VERSION 5.8 ;
BUSBITCHARS "[]" ;
DIVIDERCHAR "/" ;
UNITS
    DATABASE MICRONS 1000 ;
END UNITS

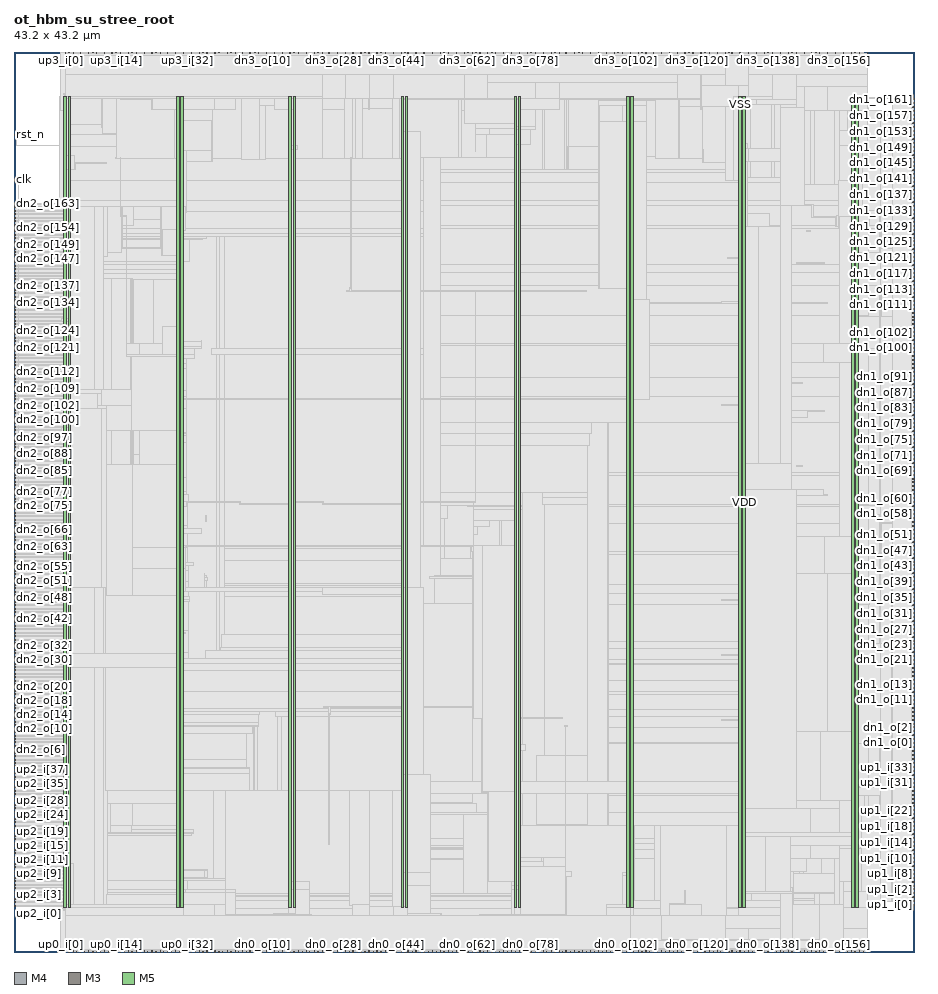
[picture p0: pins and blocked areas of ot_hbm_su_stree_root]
MACRO ot_hbm_su_stree_root
  FOREIGN ot_hbm_su_stree_root 0 0 ;
  CLASS BLOCK ;
  SIZE 43.2 BY 43.2 ;
  PIN clk
    DIRECTION INPUT ;
    USE SIGNAL ;
    PORT
      LAYER M4 ;
        RECT  0 37.056 0.084 37.08 ;
    END
    PORT
      LAYER M4 ;
        RECT  0.06 37.056 0.227 37.08 ;
    END
  END clk
  PIN dn0_o[0]
    DIRECTION OUTPUT ;
    USE SIGNAL ;
    PORT
      LAYER M3 ;
        RECT  10.008 0 10.026 0.038 ;
    END
  END dn0_o[0]
  PIN dn0_o[100]
    DIRECTION OUTPUT ;
    USE SIGNAL ;
    PORT
      LAYER M3 ;
        RECT  28.98 0 28.998 0.038 ;
    END
  END dn0_o[100]
  PIN dn0_o[101]
    DIRECTION OUTPUT ;
    USE SIGNAL ;
    PORT
      LAYER M5 ;
        RECT  29.184 0 29.208 0.084 ;
    END
  END dn0_o[101]
  PIN dn0_o[102]
    DIRECTION OUTPUT ;
    USE SIGNAL ;
    PORT
      LAYER M3 ;
        RECT  29.376 0 29.394 0.038 ;
    END
  END dn0_o[102]
  PIN dn0_o[103]
    DIRECTION OUTPUT ;
    USE SIGNAL ;
    PORT
      LAYER M5 ;
        RECT  29.568 0 29.592 0.084 ;
    END
  END dn0_o[103]
  PIN dn0_o[104]
    DIRECTION OUTPUT ;
    USE SIGNAL ;
    PORT
      LAYER M3 ;
        RECT  29.736 0 29.754 0.038 ;
    END
  END dn0_o[104]
  PIN dn0_o[105]
    DIRECTION OUTPUT ;
    USE SIGNAL ;
    PORT
      LAYER M5 ;
        RECT  29.952 0 29.976 0.084 ;
    END
  END dn0_o[105]
  PIN dn0_o[106]
    DIRECTION OUTPUT ;
    USE SIGNAL ;
    PORT
      LAYER M3 ;
        RECT  30.132 0 30.15 0.038 ;
    END
  END dn0_o[106]
  PIN dn0_o[107]
    DIRECTION OUTPUT ;
    USE SIGNAL ;
    PORT
      LAYER M5 ;
        RECT  30.336 0 30.36 0.084 ;
    END
  END dn0_o[107]
  PIN dn0_o[108]
    DIRECTION OUTPUT ;
    USE SIGNAL ;
    PORT
      LAYER M3 ;
        RECT  30.492 0 30.51 0.038 ;
    END
  END dn0_o[108]
  PIN dn0_o[109]
    DIRECTION OUTPUT ;
    USE SIGNAL ;
    PORT
      LAYER M5 ;
        RECT  30.672 0 30.696 0.084 ;
    END
  END dn0_o[109]
  PIN dn0_o[10]
    DIRECTION OUTPUT ;
    USE SIGNAL ;
    PORT
      LAYER M3 ;
        RECT  11.916 0 11.934 0.038 ;
    END
  END dn0_o[10]
  PIN dn0_o[110]
    DIRECTION OUTPUT ;
    USE SIGNAL ;
    PORT
      LAYER M3 ;
        RECT  30.888 0 30.906 0.038 ;
    END
  END dn0_o[110]
  PIN dn0_o[111]
    DIRECTION OUTPUT ;
    USE SIGNAL ;
    PORT
      LAYER M5 ;
        RECT  31.056 0 31.08 0.084 ;
    END
  END dn0_o[111]
  PIN dn0_o[112]
    DIRECTION OUTPUT ;
    USE SIGNAL ;
    PORT
      LAYER M3 ;
        RECT  31.248 0 31.266 0.038 ;
    END
  END dn0_o[112]
  PIN dn0_o[113]
    DIRECTION OUTPUT ;
    USE SIGNAL ;
    PORT
      LAYER M5 ;
        RECT  31.44 0 31.464 0.084 ;
    END
  END dn0_o[113]
  PIN dn0_o[114]
    DIRECTION OUTPUT ;
    USE SIGNAL ;
    PORT
      LAYER M3 ;
        RECT  31.644 0 31.662 0.038 ;
    END
  END dn0_o[114]
  PIN dn0_o[115]
    DIRECTION OUTPUT ;
    USE SIGNAL ;
    PORT
      LAYER M5 ;
        RECT  31.824 0 31.848 0.084 ;
    END
  END dn0_o[115]
  PIN dn0_o[116]
    DIRECTION OUTPUT ;
    USE SIGNAL ;
    PORT
      LAYER M3 ;
        RECT  32.04 0 32.058 0.038 ;
    END
  END dn0_o[116]
  PIN dn0_o[117]
    DIRECTION OUTPUT ;
    USE SIGNAL ;
    PORT
      LAYER M5 ;
        RECT  32.208 0 32.232 0.084 ;
    END
  END dn0_o[117]
  PIN dn0_o[118]
    DIRECTION OUTPUT ;
    USE SIGNAL ;
    PORT
      LAYER M3 ;
        RECT  32.4 0 32.418 0.038 ;
    END
  END dn0_o[118]
  PIN dn0_o[119]
    DIRECTION OUTPUT ;
    USE SIGNAL ;
    PORT
      LAYER M5 ;
        RECT  32.592 0 32.616 0.084 ;
    END
  END dn0_o[119]
  PIN dn0_o[11]
    DIRECTION OUTPUT ;
    USE SIGNAL ;
    PORT
      LAYER M5 ;
        RECT  12.096 0 12.12 0.084 ;
    END
  END dn0_o[11]
  PIN dn0_o[120]
    DIRECTION OUTPUT ;
    USE SIGNAL ;
    PORT
      LAYER M3 ;
        RECT  32.796 0 32.814 0.038 ;
    END
  END dn0_o[120]
  PIN dn0_o[121]
    DIRECTION OUTPUT ;
    USE SIGNAL ;
    PORT
      LAYER M5 ;
        RECT  32.976 0 33 0.084 ;
    END
  END dn0_o[121]
  PIN dn0_o[122]
    DIRECTION OUTPUT ;
    USE SIGNAL ;
    PORT
      LAYER M3 ;
        RECT  33.156 0 33.174 0.038 ;
    END
  END dn0_o[122]
  PIN dn0_o[123]
    DIRECTION OUTPUT ;
    USE SIGNAL ;
    PORT
      LAYER M5 ;
        RECT  33.36 0 33.384 0.084 ;
    END
  END dn0_o[123]
  PIN dn0_o[124]
    DIRECTION OUTPUT ;
    USE SIGNAL ;
    PORT
      LAYER M3 ;
        RECT  33.552 0 33.57 0.038 ;
    END
  END dn0_o[124]
  PIN dn0_o[125]
    DIRECTION OUTPUT ;
    USE SIGNAL ;
    PORT
      LAYER M5 ;
        RECT  33.744 0 33.768 0.084 ;
    END
  END dn0_o[125]
  PIN dn0_o[126]
    DIRECTION OUTPUT ;
    USE SIGNAL ;
    PORT
      LAYER M3 ;
        RECT  33.912 0 33.93 0.038 ;
    END
  END dn0_o[126]
  PIN dn0_o[127]
    DIRECTION OUTPUT ;
    USE SIGNAL ;
    PORT
      LAYER M5 ;
        RECT  34.128 0 34.152 0.084 ;
    END
  END dn0_o[127]
  PIN dn0_o[128]
    DIRECTION OUTPUT ;
    USE SIGNAL ;
    PORT
      LAYER M3 ;
        RECT  34.308 0 34.326 0.038 ;
    END
  END dn0_o[128]
  PIN dn0_o[129]
    DIRECTION OUTPUT ;
    USE SIGNAL ;
    PORT
      LAYER M5 ;
        RECT  34.464 0 34.488 0.084 ;
    END
  END dn0_o[129]
  PIN dn0_o[12]
    DIRECTION OUTPUT ;
    USE SIGNAL ;
    PORT
      LAYER M3 ;
        RECT  12.312 0 12.33 0.038 ;
    END
  END dn0_o[12]
  PIN dn0_o[130]
    DIRECTION OUTPUT ;
    USE SIGNAL ;
    PORT
      LAYER M3 ;
        RECT  34.668 0 34.686 0.038 ;
    END
  END dn0_o[130]
  PIN dn0_o[131]
    DIRECTION OUTPUT ;
    USE SIGNAL ;
    PORT
      LAYER M5 ;
        RECT  34.848 0 34.872 0.084 ;
    END
  END dn0_o[131]
  PIN dn0_o[132]
    DIRECTION OUTPUT ;
    USE SIGNAL ;
    PORT
      LAYER M3 ;
        RECT  35.064 0 35.082 0.038 ;
    END
  END dn0_o[132]
  PIN dn0_o[133]
    DIRECTION OUTPUT ;
    USE SIGNAL ;
    PORT
      LAYER M5 ;
        RECT  35.232 0 35.256 0.084 ;
    END
  END dn0_o[133]
  PIN dn0_o[134]
    DIRECTION OUTPUT ;
    USE SIGNAL ;
    PORT
      LAYER M3 ;
        RECT  35.424 0 35.442 0.038 ;
    END
  END dn0_o[134]
  PIN dn0_o[135]
    DIRECTION OUTPUT ;
    USE SIGNAL ;
    PORT
      LAYER M5 ;
        RECT  35.616 0 35.64 0.084 ;
    END
  END dn0_o[135]
  PIN dn0_o[136]
    DIRECTION OUTPUT ;
    USE SIGNAL ;
    PORT
      LAYER M3 ;
        RECT  35.82 0 35.838 0.038 ;
    END
  END dn0_o[136]
  PIN dn0_o[137]
    DIRECTION OUTPUT ;
    USE SIGNAL ;
    PORT
      LAYER M5 ;
        RECT  36 0 36.024 0.084 ;
    END
  END dn0_o[137]
  PIN dn0_o[138]
    DIRECTION OUTPUT ;
    USE SIGNAL ;
    PORT
      LAYER M3 ;
        RECT  36.18 0 36.198 0.038 ;
    END
  END dn0_o[138]
  PIN dn0_o[139]
    DIRECTION OUTPUT ;
    USE SIGNAL ;
    PORT
      LAYER M5 ;
        RECT  36.384 0 36.408 0.084 ;
    END
  END dn0_o[139]
  PIN dn0_o[13]
    DIRECTION OUTPUT ;
    USE SIGNAL ;
    PORT
      LAYER M5 ;
        RECT  12.48 0 12.504 0.084 ;
    END
  END dn0_o[13]
  PIN dn0_o[140]
    DIRECTION OUTPUT ;
    USE SIGNAL ;
    PORT
      LAYER M3 ;
        RECT  36.576 0 36.594 0.038 ;
    END
  END dn0_o[140]
  PIN dn0_o[141]
    DIRECTION OUTPUT ;
    USE SIGNAL ;
    PORT
      LAYER M5 ;
        RECT  36.768 0 36.792 0.084 ;
    END
  END dn0_o[141]
  PIN dn0_o[142]
    DIRECTION OUTPUT ;
    USE SIGNAL ;
    PORT
      LAYER M3 ;
        RECT  36.936 0 36.954 0.038 ;
    END
  END dn0_o[142]
  PIN dn0_o[143]
    DIRECTION OUTPUT ;
    USE SIGNAL ;
    PORT
      LAYER M5 ;
        RECT  37.152 0 37.176 0.084 ;
    END
  END dn0_o[143]
  PIN dn0_o[144]
    DIRECTION OUTPUT ;
    USE SIGNAL ;
    PORT
      LAYER M3 ;
        RECT  37.332 0 37.35 0.038 ;
    END
  END dn0_o[144]
  PIN dn0_o[145]
    DIRECTION OUTPUT ;
    USE SIGNAL ;
    PORT
      LAYER M5 ;
        RECT  37.536 0 37.56 0.084 ;
    END
  END dn0_o[145]
  PIN dn0_o[146]
    DIRECTION OUTPUT ;
    USE SIGNAL ;
    PORT
      LAYER M3 ;
        RECT  37.728 0 37.746 0.038 ;
    END
  END dn0_o[146]
  PIN dn0_o[147]
    DIRECTION OUTPUT ;
    USE SIGNAL ;
    PORT
      LAYER M5 ;
        RECT  37.92 0 37.944 0.084 ;
    END
  END dn0_o[147]
  PIN dn0_o[148]
    DIRECTION OUTPUT ;
    USE SIGNAL ;
    PORT
      LAYER M3 ;
        RECT  38.088 0 38.106 0.038 ;
    END
  END dn0_o[148]
  PIN dn0_o[149]
    DIRECTION OUTPUT ;
    USE SIGNAL ;
    PORT
      LAYER M5 ;
        RECT  38.256 0 38.28 0.084 ;
    END
  END dn0_o[149]
  PIN dn0_o[14]
    DIRECTION OUTPUT ;
    USE SIGNAL ;
    PORT
      LAYER M3 ;
        RECT  12.672 0 12.69 0.038 ;
    END
  END dn0_o[14]
  PIN dn0_o[150]
    DIRECTION OUTPUT ;
    USE SIGNAL ;
    PORT
      LAYER M3 ;
        RECT  38.484 0 38.502 0.038 ;
    END
  END dn0_o[150]
  PIN dn0_o[151]
    DIRECTION OUTPUT ;
    USE SIGNAL ;
    PORT
      LAYER M5 ;
        RECT  38.64 0 38.664 0.084 ;
    END
  END dn0_o[151]
  PIN dn0_o[152]
    DIRECTION OUTPUT ;
    USE SIGNAL ;
    PORT
      LAYER M3 ;
        RECT  38.844 0 38.862 0.038 ;
    END
  END dn0_o[152]
  PIN dn0_o[153]
    DIRECTION OUTPUT ;
    USE SIGNAL ;
    PORT
      LAYER M5 ;
        RECT  39.024 0 39.048 0.084 ;
    END
  END dn0_o[153]
  PIN dn0_o[154]
    DIRECTION OUTPUT ;
    USE SIGNAL ;
    PORT
      LAYER M3 ;
        RECT  39.24 0 39.258 0.038 ;
    END
  END dn0_o[154]
  PIN dn0_o[155]
    DIRECTION OUTPUT ;
    USE SIGNAL ;
    PORT
      LAYER M5 ;
        RECT  39.408 0 39.432 0.084 ;
    END
  END dn0_o[155]
  PIN dn0_o[156]
    DIRECTION OUTPUT ;
    USE SIGNAL ;
    PORT
      LAYER M3 ;
        RECT  39.6 0 39.618 0.038 ;
    END
  END dn0_o[156]
  PIN dn0_o[157]
    DIRECTION OUTPUT ;
    USE SIGNAL ;
    PORT
      LAYER M5 ;
        RECT  39.792 0 39.816 0.084 ;
    END
  END dn0_o[157]
  PIN dn0_o[158]
    DIRECTION OUTPUT ;
    USE SIGNAL ;
    PORT
      LAYER M3 ;
        RECT  39.996 0 40.014 0.038 ;
    END
  END dn0_o[158]
  PIN dn0_o[159]
    DIRECTION OUTPUT ;
    USE SIGNAL ;
    PORT
      LAYER M5 ;
        RECT  40.176 0 40.2 0.084 ;
    END
  END dn0_o[159]
  PIN dn0_o[15]
    DIRECTION OUTPUT ;
    USE SIGNAL ;
    PORT
      LAYER M5 ;
        RECT  12.864 0 12.888 0.084 ;
    END
  END dn0_o[15]
  PIN dn0_o[160]
    DIRECTION OUTPUT ;
    USE SIGNAL ;
    PORT
      LAYER M3 ;
        RECT  40.356 0 40.374 0.038 ;
    END
  END dn0_o[160]
  PIN dn0_o[161]
    DIRECTION OUTPUT ;
    USE SIGNAL ;
    PORT
      LAYER M5 ;
        RECT  40.56 0 40.584 0.084 ;
    END
  END dn0_o[161]
  PIN dn0_o[162]
    DIRECTION OUTPUT ;
    USE SIGNAL ;
    PORT
      LAYER M3 ;
        RECT  40.752 0 40.77 0.038 ;
    END
  END dn0_o[162]
  PIN dn0_o[163]
    DIRECTION OUTPUT ;
    USE SIGNAL ;
    PORT
      LAYER M5 ;
        RECT  40.944 0 40.968 0.084 ;
    END
  END dn0_o[163]
  PIN dn0_o[16]
    DIRECTION OUTPUT ;
    USE SIGNAL ;
    PORT
      LAYER M3 ;
        RECT  13.068 0 13.086 0.038 ;
    END
  END dn0_o[16]
  PIN dn0_o[17]
    DIRECTION OUTPUT ;
    USE SIGNAL ;
    PORT
      LAYER M5 ;
        RECT  13.248 0 13.272 0.084 ;
    END
  END dn0_o[17]
  PIN dn0_o[18]
    DIRECTION OUTPUT ;
    USE SIGNAL ;
    PORT
      LAYER M3 ;
        RECT  13.428 0 13.446 0.038 ;
    END
  END dn0_o[18]
  PIN dn0_o[19]
    DIRECTION OUTPUT ;
    USE SIGNAL ;
    PORT
      LAYER M5 ;
        RECT  13.632 0 13.656 0.084 ;
    END
  END dn0_o[19]
  PIN dn0_o[1]
    DIRECTION OUTPUT ;
    USE SIGNAL ;
    PORT
      LAYER M5 ;
        RECT  10.224 0 10.248 0.084 ;
    END
  END dn0_o[1]
  PIN dn0_o[20]
    DIRECTION OUTPUT ;
    USE SIGNAL ;
    PORT
      LAYER M3 ;
        RECT  13.824 0 13.842 0.038 ;
    END
  END dn0_o[20]
  PIN dn0_o[21]
    DIRECTION OUTPUT ;
    USE SIGNAL ;
    PORT
      LAYER M5 ;
        RECT  14.016 0 14.04 0.084 ;
    END
  END dn0_o[21]
  PIN dn0_o[22]
    DIRECTION OUTPUT ;
    USE SIGNAL ;
    PORT
      LAYER M3 ;
        RECT  14.184 0 14.202 0.038 ;
    END
  END dn0_o[22]
  PIN dn0_o[23]
    DIRECTION OUTPUT ;
    USE SIGNAL ;
    PORT
      LAYER M5 ;
        RECT  14.4 0 14.424 0.084 ;
    END
  END dn0_o[23]
  PIN dn0_o[24]
    DIRECTION OUTPUT ;
    USE SIGNAL ;
    PORT
      LAYER M3 ;
        RECT  14.58 0 14.598 0.038 ;
    END
  END dn0_o[24]
  PIN dn0_o[25]
    DIRECTION OUTPUT ;
    USE SIGNAL ;
    PORT
      LAYER M5 ;
        RECT  14.784 0 14.808 0.084 ;
    END
  END dn0_o[25]
  PIN dn0_o[26]
    DIRECTION OUTPUT ;
    USE SIGNAL ;
    PORT
      LAYER M3 ;
        RECT  14.94 0 14.958 0.038 ;
    END
  END dn0_o[26]
  PIN dn0_o[27]
    DIRECTION OUTPUT ;
    USE SIGNAL ;
    PORT
      LAYER M5 ;
        RECT  15.12 0 15.144 0.084 ;
    END
  END dn0_o[27]
  PIN dn0_o[28]
    DIRECTION OUTPUT ;
    USE SIGNAL ;
    PORT
      LAYER M3 ;
        RECT  15.336 0 15.354 0.038 ;
    END
  END dn0_o[28]
  PIN dn0_o[29]
    DIRECTION OUTPUT ;
    USE SIGNAL ;
    PORT
      LAYER M5 ;
        RECT  15.504 0 15.528 0.084 ;
    END
  END dn0_o[29]
  PIN dn0_o[2]
    DIRECTION OUTPUT ;
    USE SIGNAL ;
    PORT
      LAYER M3 ;
        RECT  10.404 0 10.422 0.038 ;
    END
  END dn0_o[2]
  PIN dn0_o[30]
    DIRECTION OUTPUT ;
    USE SIGNAL ;
    PORT
      LAYER M3 ;
        RECT  15.696 0 15.714 0.038 ;
    END
  END dn0_o[30]
  PIN dn0_o[31]
    DIRECTION OUTPUT ;
    USE SIGNAL ;
    PORT
      LAYER M5 ;
        RECT  15.888 0 15.912 0.084 ;
    END
  END dn0_o[31]
  PIN dn0_o[32]
    DIRECTION OUTPUT ;
    USE SIGNAL ;
    PORT
      LAYER M3 ;
        RECT  16.092 0 16.11 0.038 ;
    END
  END dn0_o[32]
  PIN dn0_o[33]
    DIRECTION OUTPUT ;
    USE SIGNAL ;
    PORT
      LAYER M5 ;
        RECT  16.272 0 16.296 0.084 ;
    END
  END dn0_o[33]
  PIN dn0_o[34]
    DIRECTION OUTPUT ;
    USE SIGNAL ;
    PORT
      LAYER M3 ;
        RECT  16.488 0 16.506 0.038 ;
    END
  END dn0_o[34]
  PIN dn0_o[35]
    DIRECTION OUTPUT ;
    USE SIGNAL ;
    PORT
      LAYER M5 ;
        RECT  16.656 0 16.68 0.084 ;
    END
  END dn0_o[35]
  PIN dn0_o[36]
    DIRECTION OUTPUT ;
    USE SIGNAL ;
    PORT
      LAYER M3 ;
        RECT  16.848 0 16.866 0.038 ;
    END
  END dn0_o[36]
  PIN dn0_o[37]
    DIRECTION OUTPUT ;
    USE SIGNAL ;
    PORT
      LAYER M5 ;
        RECT  17.04 0 17.064 0.084 ;
    END
  END dn0_o[37]
  PIN dn0_o[38]
    DIRECTION OUTPUT ;
    USE SIGNAL ;
    PORT
      LAYER M3 ;
        RECT  17.244 0 17.262 0.038 ;
    END
  END dn0_o[38]
  PIN dn0_o[39]
    DIRECTION OUTPUT ;
    USE SIGNAL ;
    PORT
      LAYER M5 ;
        RECT  17.424 0 17.448 0.084 ;
    END
  END dn0_o[39]
  PIN dn0_o[3]
    DIRECTION OUTPUT ;
    USE SIGNAL ;
    PORT
      LAYER M5 ;
        RECT  10.608 0 10.632 0.084 ;
    END
  END dn0_o[3]
  PIN dn0_o[40]
    DIRECTION OUTPUT ;
    USE SIGNAL ;
    PORT
      LAYER M3 ;
        RECT  17.604 0 17.622 0.038 ;
    END
  END dn0_o[40]
  PIN dn0_o[41]
    DIRECTION OUTPUT ;
    USE SIGNAL ;
    PORT
      LAYER M5 ;
        RECT  17.808 0 17.832 0.084 ;
    END
  END dn0_o[41]
  PIN dn0_o[42]
    DIRECTION OUTPUT ;
    USE SIGNAL ;
    PORT
      LAYER M3 ;
        RECT  18 0 18.018 0.038 ;
    END
  END dn0_o[42]
  PIN dn0_o[43]
    DIRECTION OUTPUT ;
    USE SIGNAL ;
    PORT
      LAYER M5 ;
        RECT  18.192 0 18.216 0.084 ;
    END
  END dn0_o[43]
  PIN dn0_o[44]
    DIRECTION OUTPUT ;
    USE SIGNAL ;
    PORT
      LAYER M3 ;
        RECT  18.36 0 18.378 0.038 ;
    END
  END dn0_o[44]
  PIN dn0_o[45]
    DIRECTION OUTPUT ;
    USE SIGNAL ;
    PORT
      LAYER M5 ;
        RECT  18.576 0 18.6 0.084 ;
    END
  END dn0_o[45]
  PIN dn0_o[46]
    DIRECTION OUTPUT ;
    USE SIGNAL ;
    PORT
      LAYER M3 ;
        RECT  18.756 0 18.774 0.038 ;
    END
  END dn0_o[46]
  PIN dn0_o[47]
    DIRECTION OUTPUT ;
    USE SIGNAL ;
    PORT
      LAYER M5 ;
        RECT  18.912 0 18.936 0.084 ;
    END
  END dn0_o[47]
  PIN dn0_o[48]
    DIRECTION OUTPUT ;
    USE SIGNAL ;
    PORT
      LAYER M3 ;
        RECT  19.116 0 19.134 0.038 ;
    END
  END dn0_o[48]
  PIN dn0_o[49]
    DIRECTION OUTPUT ;
    USE SIGNAL ;
    PORT
      LAYER M5 ;
        RECT  19.296 0 19.32 0.084 ;
    END
  END dn0_o[49]
  PIN dn0_o[4]
    DIRECTION OUTPUT ;
    USE SIGNAL ;
    PORT
      LAYER M3 ;
        RECT  10.764 0 10.782 0.038 ;
    END
  END dn0_o[4]
  PIN dn0_o[50]
    DIRECTION OUTPUT ;
    USE SIGNAL ;
    PORT
      LAYER M3 ;
        RECT  19.512 0 19.53 0.038 ;
    END
  END dn0_o[50]
  PIN dn0_o[51]
    DIRECTION OUTPUT ;
    USE SIGNAL ;
    PORT
      LAYER M5 ;
        RECT  19.68 0 19.704 0.084 ;
    END
  END dn0_o[51]
  PIN dn0_o[52]
    DIRECTION OUTPUT ;
    USE SIGNAL ;
    PORT
      LAYER M3 ;
        RECT  19.872 0 19.89 0.038 ;
    END
  END dn0_o[52]
  PIN dn0_o[53]
    DIRECTION OUTPUT ;
    USE SIGNAL ;
    PORT
      LAYER M5 ;
        RECT  20.064 0 20.088 0.084 ;
    END
  END dn0_o[53]
  PIN dn0_o[54]
    DIRECTION OUTPUT ;
    USE SIGNAL ;
    PORT
      LAYER M3 ;
        RECT  20.268 0 20.286 0.038 ;
    END
  END dn0_o[54]
  PIN dn0_o[55]
    DIRECTION OUTPUT ;
    USE SIGNAL ;
    PORT
      LAYER M5 ;
        RECT  20.448 0 20.472 0.084 ;
    END
  END dn0_o[55]
  PIN dn0_o[56]
    DIRECTION OUTPUT ;
    USE SIGNAL ;
    PORT
      LAYER M3 ;
        RECT  20.628 0 20.646 0.038 ;
    END
  END dn0_o[56]
  PIN dn0_o[57]
    DIRECTION OUTPUT ;
    USE SIGNAL ;
    PORT
      LAYER M5 ;
        RECT  20.832 0 20.856 0.084 ;
    END
  END dn0_o[57]
  PIN dn0_o[58]
    DIRECTION OUTPUT ;
    USE SIGNAL ;
    PORT
      LAYER M3 ;
        RECT  21.024 0 21.042 0.038 ;
    END
  END dn0_o[58]
  PIN dn0_o[59]
    DIRECTION OUTPUT ;
    USE SIGNAL ;
    PORT
      LAYER M5 ;
        RECT  21.216 0 21.24 0.084 ;
    END
  END dn0_o[59]
  PIN dn0_o[5]
    DIRECTION OUTPUT ;
    USE SIGNAL ;
    PORT
      LAYER M5 ;
        RECT  10.944 0 10.968 0.084 ;
    END
  END dn0_o[5]
  PIN dn0_o[60]
    DIRECTION OUTPUT ;
    USE SIGNAL ;
    PORT
      LAYER M3 ;
        RECT  21.384 0 21.402 0.038 ;
    END
  END dn0_o[60]
  PIN dn0_o[61]
    DIRECTION OUTPUT ;
    USE SIGNAL ;
    PORT
      LAYER M5 ;
        RECT  21.6 0 21.624 0.084 ;
    END
  END dn0_o[61]
  PIN dn0_o[62]
    DIRECTION OUTPUT ;
    USE SIGNAL ;
    PORT
      LAYER M3 ;
        RECT  21.78 0 21.798 0.038 ;
    END
  END dn0_o[62]
  PIN dn0_o[63]
    DIRECTION OUTPUT ;
    USE SIGNAL ;
    PORT
      LAYER M5 ;
        RECT  21.984 0 22.008 0.084 ;
    END
  END dn0_o[63]
  PIN dn0_o[64]
    DIRECTION OUTPUT ;
    USE SIGNAL ;
    PORT
      LAYER M3 ;
        RECT  22.176 0 22.194 0.038 ;
    END
  END dn0_o[64]
  PIN dn0_o[65]
    DIRECTION OUTPUT ;
    USE SIGNAL ;
    PORT
      LAYER M5 ;
        RECT  22.368 0 22.392 0.084 ;
    END
  END dn0_o[65]
  PIN dn0_o[66]
    DIRECTION OUTPUT ;
    USE SIGNAL ;
    PORT
      LAYER M3 ;
        RECT  22.536 0 22.554 0.038 ;
    END
  END dn0_o[66]
  PIN dn0_o[67]
    DIRECTION OUTPUT ;
    USE SIGNAL ;
    PORT
      LAYER M5 ;
        RECT  22.704 0 22.728 0.084 ;
    END
  END dn0_o[67]
  PIN dn0_o[68]
    DIRECTION OUTPUT ;
    USE SIGNAL ;
    PORT
      LAYER M3 ;
        RECT  22.932 0 22.95 0.038 ;
    END
  END dn0_o[68]
  PIN dn0_o[69]
    DIRECTION OUTPUT ;
    USE SIGNAL ;
    PORT
      LAYER M5 ;
        RECT  23.088 0 23.112 0.084 ;
    END
  END dn0_o[69]
  PIN dn0_o[6]
    DIRECTION OUTPUT ;
    USE SIGNAL ;
    PORT
      LAYER M3 ;
        RECT  11.16 0 11.178 0.038 ;
    END
  END dn0_o[6]
  PIN dn0_o[70]
    DIRECTION OUTPUT ;
    USE SIGNAL ;
    PORT
      LAYER M3 ;
        RECT  23.292 0 23.31 0.038 ;
    END
  END dn0_o[70]
  PIN dn0_o[71]
    DIRECTION OUTPUT ;
    USE SIGNAL ;
    PORT
      LAYER M5 ;
        RECT  23.472 0 23.496 0.084 ;
    END
  END dn0_o[71]
  PIN dn0_o[72]
    DIRECTION OUTPUT ;
    USE SIGNAL ;
    PORT
      LAYER M3 ;
        RECT  23.688 0 23.706 0.038 ;
    END
  END dn0_o[72]
  PIN dn0_o[73]
    DIRECTION OUTPUT ;
    USE SIGNAL ;
    PORT
      LAYER M5 ;
        RECT  23.856 0 23.88 0.084 ;
    END
  END dn0_o[73]
  PIN dn0_o[74]
    DIRECTION OUTPUT ;
    USE SIGNAL ;
    PORT
      LAYER M3 ;
        RECT  24.048 0 24.066 0.038 ;
    END
  END dn0_o[74]
  PIN dn0_o[75]
    DIRECTION OUTPUT ;
    USE SIGNAL ;
    PORT
      LAYER M5 ;
        RECT  24.24 0 24.264 0.084 ;
    END
  END dn0_o[75]
  PIN dn0_o[76]
    DIRECTION OUTPUT ;
    USE SIGNAL ;
    PORT
      LAYER M3 ;
        RECT  24.444 0 24.462 0.038 ;
    END
  END dn0_o[76]
  PIN dn0_o[77]
    DIRECTION OUTPUT ;
    USE SIGNAL ;
    PORT
      LAYER M5 ;
        RECT  24.624 0 24.648 0.084 ;
    END
  END dn0_o[77]
  PIN dn0_o[78]
    DIRECTION OUTPUT ;
    USE SIGNAL ;
    PORT
      LAYER M3 ;
        RECT  24.804 0 24.822 0.038 ;
    END
  END dn0_o[78]
  PIN dn0_o[79]
    DIRECTION OUTPUT ;
    USE SIGNAL ;
    PORT
      LAYER M5 ;
        RECT  25.008 0 25.032 0.084 ;
    END
  END dn0_o[79]
  PIN dn0_o[7]
    DIRECTION OUTPUT ;
    USE SIGNAL ;
    PORT
      LAYER M5 ;
        RECT  11.328 0 11.352 0.084 ;
    END
  END dn0_o[7]
  PIN dn0_o[80]
    DIRECTION OUTPUT ;
    USE SIGNAL ;
    PORT
      LAYER M3 ;
        RECT  25.2 0 25.218 0.038 ;
    END
  END dn0_o[80]
  PIN dn0_o[81]
    DIRECTION OUTPUT ;
    USE SIGNAL ;
    PORT
      LAYER M5 ;
        RECT  25.392 0 25.416 0.084 ;
    END
  END dn0_o[81]
  PIN dn0_o[82]
    DIRECTION OUTPUT ;
    USE SIGNAL ;
    PORT
      LAYER M3 ;
        RECT  25.56 0 25.578 0.038 ;
    END
  END dn0_o[82]
  PIN dn0_o[83]
    DIRECTION OUTPUT ;
    USE SIGNAL ;
    PORT
      LAYER M5 ;
        RECT  25.776 0 25.8 0.084 ;
    END
  END dn0_o[83]
  PIN dn0_o[84]
    DIRECTION OUTPUT ;
    USE SIGNAL ;
    PORT
      LAYER M3 ;
        RECT  25.956 0 25.974 0.038 ;
    END
  END dn0_o[84]
  PIN dn0_o[85]
    DIRECTION OUTPUT ;
    USE SIGNAL ;
    PORT
      LAYER M5 ;
        RECT  26.16 0 26.184 0.084 ;
    END
  END dn0_o[85]
  PIN dn0_o[86]
    DIRECTION OUTPUT ;
    USE SIGNAL ;
    PORT
      LAYER M3 ;
        RECT  26.316 0 26.334 0.038 ;
    END
  END dn0_o[86]
  PIN dn0_o[87]
    DIRECTION OUTPUT ;
    USE SIGNAL ;
    PORT
      LAYER M5 ;
        RECT  26.496 0 26.52 0.084 ;
    END
  END dn0_o[87]
  PIN dn0_o[88]
    DIRECTION OUTPUT ;
    USE SIGNAL ;
    PORT
      LAYER M3 ;
        RECT  26.712 0 26.73 0.038 ;
    END
  END dn0_o[88]
  PIN dn0_o[89]
    DIRECTION OUTPUT ;
    USE SIGNAL ;
    PORT
      LAYER M5 ;
        RECT  26.88 0 26.904 0.084 ;
    END
  END dn0_o[89]
  PIN dn0_o[8]
    DIRECTION OUTPUT ;
    USE SIGNAL ;
    PORT
      LAYER M3 ;
        RECT  11.556 0 11.574 0.038 ;
    END
  END dn0_o[8]
  PIN dn0_o[90]
    DIRECTION OUTPUT ;
    USE SIGNAL ;
    PORT
      LAYER M3 ;
        RECT  27.108 0 27.126 0.038 ;
    END
  END dn0_o[90]
  PIN dn0_o[91]
    DIRECTION OUTPUT ;
    USE SIGNAL ;
    PORT
      LAYER M5 ;
        RECT  27.264 0 27.288 0.084 ;
    END
  END dn0_o[91]
  PIN dn0_o[92]
    DIRECTION OUTPUT ;
    USE SIGNAL ;
    PORT
      LAYER M3 ;
        RECT  27.468 0 27.486 0.038 ;
    END
  END dn0_o[92]
  PIN dn0_o[93]
    DIRECTION OUTPUT ;
    USE SIGNAL ;
    PORT
      LAYER M5 ;
        RECT  27.648 0 27.672 0.084 ;
    END
  END dn0_o[93]
  PIN dn0_o[94]
    DIRECTION OUTPUT ;
    USE SIGNAL ;
    PORT
      LAYER M3 ;
        RECT  27.864 0 27.882 0.038 ;
    END
  END dn0_o[94]
  PIN dn0_o[95]
    DIRECTION OUTPUT ;
    USE SIGNAL ;
    PORT
      LAYER M5 ;
        RECT  28.032 0 28.056 0.084 ;
    END
  END dn0_o[95]
  PIN dn0_o[96]
    DIRECTION OUTPUT ;
    USE SIGNAL ;
    PORT
      LAYER M3 ;
        RECT  28.224 0 28.242 0.038 ;
    END
  END dn0_o[96]
  PIN dn0_o[97]
    DIRECTION OUTPUT ;
    USE SIGNAL ;
    PORT
      LAYER M5 ;
        RECT  28.416 0 28.44 0.084 ;
    END
  END dn0_o[97]
  PIN dn0_o[98]
    DIRECTION OUTPUT ;
    USE SIGNAL ;
    PORT
      LAYER M3 ;
        RECT  28.62 0 28.638 0.038 ;
    END
  END dn0_o[98]
  PIN dn0_o[99]
    DIRECTION OUTPUT ;
    USE SIGNAL ;
    PORT
      LAYER M5 ;
        RECT  28.8 0 28.824 0.084 ;
    END
  END dn0_o[99]
  PIN dn0_o[9]
    DIRECTION OUTPUT ;
    USE SIGNAL ;
    PORT
      LAYER M5 ;
        RECT  11.712 0 11.736 0.084 ;
    END
  END dn0_o[9]
  PIN dn1_o[0]
    DIRECTION OUTPUT ;
    USE SIGNAL ;
    PORT
      LAYER M4 ;
        RECT  43.116 10.032 43.2 10.056 ;
    END
  END dn1_o[0]
  PIN dn1_o[100]
    DIRECTION OUTPUT ;
    USE SIGNAL ;
    PORT
      LAYER M4 ;
        RECT  43.116 28.992 43.2 29.016 ;
    END
  END dn1_o[100]
  PIN dn1_o[101]
    DIRECTION OUTPUT ;
    USE SIGNAL ;
    PORT
      LAYER M4 ;
        RECT  43.116 29.184 43.2 29.208 ;
    END
  END dn1_o[101]
  PIN dn1_o[102]
    DIRECTION OUTPUT ;
    USE SIGNAL ;
    PORT
      LAYER M4 ;
        RECT  43.116 29.376 43.2 29.4 ;
    END
  END dn1_o[102]
  PIN dn1_o[103]
    DIRECTION OUTPUT ;
    USE SIGNAL ;
    PORT
      LAYER M4 ;
        RECT  43.116 29.568 43.2 29.592 ;
    END
  END dn1_o[103]
  PIN dn1_o[104]
    DIRECTION OUTPUT ;
    USE SIGNAL ;
    PORT
      LAYER M4 ;
        RECT  43.116 29.76 43.2 29.784 ;
    END
  END dn1_o[104]
  PIN dn1_o[105]
    DIRECTION OUTPUT ;
    USE SIGNAL ;
    PORT
      LAYER M4 ;
        RECT  43.116 29.952 43.2 29.976 ;
    END
  END dn1_o[105]
  PIN dn1_o[106]
    DIRECTION OUTPUT ;
    USE SIGNAL ;
    PORT
      LAYER M4 ;
        RECT  43.116 30.144 43.2 30.168 ;
    END
  END dn1_o[106]
  PIN dn1_o[107]
    DIRECTION OUTPUT ;
    USE SIGNAL ;
    PORT
      LAYER M4 ;
        RECT  43.116 30.336 43.2 30.36 ;
    END
  END dn1_o[107]
  PIN dn1_o[108]
    DIRECTION OUTPUT ;
    USE SIGNAL ;
    PORT
      LAYER M4 ;
        RECT  43.116 30.48 43.2 30.504 ;
    END
  END dn1_o[108]
  PIN dn1_o[109]
    DIRECTION OUTPUT ;
    USE SIGNAL ;
    PORT
      LAYER M4 ;
        RECT  43.116 30.672 43.2 30.696 ;
    END
  END dn1_o[109]
  PIN dn1_o[10]
    DIRECTION OUTPUT ;
    USE SIGNAL ;
    PORT
      LAYER M4 ;
        RECT  43.116 11.904 43.2 11.928 ;
    END
  END dn1_o[10]
  PIN dn1_o[110]
    DIRECTION OUTPUT ;
    USE SIGNAL ;
    PORT
      LAYER M4 ;
        RECT  43.116 30.864 43.2 30.888 ;
    END
  END dn1_o[110]
  PIN dn1_o[111]
    DIRECTION OUTPUT ;
    USE SIGNAL ;
    PORT
      LAYER M4 ;
        RECT  43.116 31.056 43.2 31.08 ;
    END
  END dn1_o[111]
  PIN dn1_o[112]
    DIRECTION OUTPUT ;
    USE SIGNAL ;
    PORT
      LAYER M4 ;
        RECT  43.116 31.248 43.2 31.272 ;
    END
  END dn1_o[112]
  PIN dn1_o[113]
    DIRECTION OUTPUT ;
    USE SIGNAL ;
    PORT
      LAYER M4 ;
        RECT  43.116 31.44 43.2 31.464 ;
    END
  END dn1_o[113]
  PIN dn1_o[114]
    DIRECTION OUTPUT ;
    USE SIGNAL ;
    PORT
      LAYER M4 ;
        RECT  43.116 31.632 43.2 31.656 ;
    END
  END dn1_o[114]
  PIN dn1_o[115]
    DIRECTION OUTPUT ;
    USE SIGNAL ;
    PORT
      LAYER M4 ;
        RECT  43.116 31.824 43.2 31.848 ;
    END
  END dn1_o[115]
  PIN dn1_o[116]
    DIRECTION OUTPUT ;
    USE SIGNAL ;
    PORT
      LAYER M4 ;
        RECT  43.116 32.016 43.2 32.04 ;
    END
  END dn1_o[116]
  PIN dn1_o[117]
    DIRECTION OUTPUT ;
    USE SIGNAL ;
    PORT
      LAYER M4 ;
        RECT  43.116 32.208 43.2 32.232 ;
    END
  END dn1_o[117]
  PIN dn1_o[118]
    DIRECTION OUTPUT ;
    USE SIGNAL ;
    PORT
      LAYER M4 ;
        RECT  43.116 32.4 43.2 32.424 ;
    END
  END dn1_o[118]
  PIN dn1_o[119]
    DIRECTION OUTPUT ;
    USE SIGNAL ;
    PORT
      LAYER M4 ;
        RECT  43.116 32.592 43.2 32.616 ;
    END
  END dn1_o[119]
  PIN dn1_o[11]
    DIRECTION OUTPUT ;
    USE SIGNAL ;
    PORT
      LAYER M4 ;
        RECT  43.116 12.096 43.2 12.12 ;
    END
  END dn1_o[11]
  PIN dn1_o[120]
    DIRECTION OUTPUT ;
    USE SIGNAL ;
    PORT
      LAYER M4 ;
        RECT  43.116 32.784 43.2 32.808 ;
    END
  END dn1_o[120]
  PIN dn1_o[121]
    DIRECTION OUTPUT ;
    USE SIGNAL ;
    PORT
      LAYER M4 ;
        RECT  43.116 32.976 43.2 33 ;
    END
  END dn1_o[121]
  PIN dn1_o[122]
    DIRECTION OUTPUT ;
    USE SIGNAL ;
    PORT
      LAYER M4 ;
        RECT  43.116 33.168 43.2 33.192 ;
    END
  END dn1_o[122]
  PIN dn1_o[123]
    DIRECTION OUTPUT ;
    USE SIGNAL ;
    PORT
      LAYER M4 ;
        RECT  43.116 33.36 43.2 33.384 ;
    END
  END dn1_o[123]
  PIN dn1_o[124]
    DIRECTION OUTPUT ;
    USE SIGNAL ;
    PORT
      LAYER M4 ;
        RECT  43.116 33.552 43.2 33.576 ;
    END
  END dn1_o[124]
  PIN dn1_o[125]
    DIRECTION OUTPUT ;
    USE SIGNAL ;
    PORT
      LAYER M4 ;
        RECT  43.116 33.744 43.2 33.768 ;
    END
  END dn1_o[125]
  PIN dn1_o[126]
    DIRECTION OUTPUT ;
    USE SIGNAL ;
    PORT
      LAYER M4 ;
        RECT  43.116 33.936 43.2 33.96 ;
    END
  END dn1_o[126]
  PIN dn1_o[127]
    DIRECTION OUTPUT ;
    USE SIGNAL ;
    PORT
      LAYER M4 ;
        RECT  43.116 34.128 43.2 34.152 ;
    END
  END dn1_o[127]
  PIN dn1_o[128]
    DIRECTION OUTPUT ;
    USE SIGNAL ;
    PORT
      LAYER M4 ;
        RECT  43.116 34.272 43.2 34.296 ;
    END
  END dn1_o[128]
  PIN dn1_o[129]
    DIRECTION OUTPUT ;
    USE SIGNAL ;
    PORT
      LAYER M4 ;
        RECT  43.116 34.464 43.2 34.488 ;
    END
  END dn1_o[129]
  PIN dn1_o[12]
    DIRECTION OUTPUT ;
    USE SIGNAL ;
    PORT
      LAYER M4 ;
        RECT  43.116 12.288 43.2 12.312 ;
    END
  END dn1_o[12]
  PIN dn1_o[130]
    DIRECTION OUTPUT ;
    USE SIGNAL ;
    PORT
      LAYER M4 ;
        RECT  43.116 34.656 43.2 34.68 ;
    END
  END dn1_o[130]
  PIN dn1_o[131]
    DIRECTION OUTPUT ;
    USE SIGNAL ;
    PORT
      LAYER M4 ;
        RECT  43.116 34.848 43.2 34.872 ;
    END
  END dn1_o[131]
  PIN dn1_o[132]
    DIRECTION OUTPUT ;
    USE SIGNAL ;
    PORT
      LAYER M4 ;
        RECT  43.116 35.04 43.2 35.064 ;
    END
  END dn1_o[132]
  PIN dn1_o[133]
    DIRECTION OUTPUT ;
    USE SIGNAL ;
    PORT
      LAYER M4 ;
        RECT  43.116 35.232 43.2 35.256 ;
    END
  END dn1_o[133]
  PIN dn1_o[134]
    DIRECTION OUTPUT ;
    USE SIGNAL ;
    PORT
      LAYER M4 ;
        RECT  43.116 35.424 43.2 35.448 ;
    END
  END dn1_o[134]
  PIN dn1_o[135]
    DIRECTION OUTPUT ;
    USE SIGNAL ;
    PORT
      LAYER M4 ;
        RECT  43.116 35.616 43.2 35.64 ;
    END
  END dn1_o[135]
  PIN dn1_o[136]
    DIRECTION OUTPUT ;
    USE SIGNAL ;
    PORT
      LAYER M4 ;
        RECT  43.116 35.808 43.2 35.832 ;
    END
  END dn1_o[136]
  PIN dn1_o[137]
    DIRECTION OUTPUT ;
    USE SIGNAL ;
    PORT
      LAYER M4 ;
        RECT  43.116 36 43.2 36.024 ;
    END
  END dn1_o[137]
  PIN dn1_o[138]
    DIRECTION OUTPUT ;
    USE SIGNAL ;
    PORT
      LAYER M4 ;
        RECT  43.116 36.192 43.2 36.216 ;
    END
  END dn1_o[138]
  PIN dn1_o[139]
    DIRECTION OUTPUT ;
    USE SIGNAL ;
    PORT
      LAYER M4 ;
        RECT  43.116 36.384 43.2 36.408 ;
    END
  END dn1_o[139]
  PIN dn1_o[13]
    DIRECTION OUTPUT ;
    USE SIGNAL ;
    PORT
      LAYER M4 ;
        RECT  43.116 12.48 43.2 12.504 ;
    END
  END dn1_o[13]
  PIN dn1_o[140]
    DIRECTION OUTPUT ;
    USE SIGNAL ;
    PORT
      LAYER M4 ;
        RECT  43.116 36.576 43.2 36.6 ;
    END
  END dn1_o[140]
  PIN dn1_o[141]
    DIRECTION OUTPUT ;
    USE SIGNAL ;
    PORT
      LAYER M4 ;
        RECT  43.116 36.768 43.2 36.792 ;
    END
  END dn1_o[141]
  PIN dn1_o[142]
    DIRECTION OUTPUT ;
    USE SIGNAL ;
    PORT
      LAYER M4 ;
        RECT  43.116 36.96 43.2 36.984 ;
    END
  END dn1_o[142]
  PIN dn1_o[143]
    DIRECTION OUTPUT ;
    USE SIGNAL ;
    PORT
      LAYER M4 ;
        RECT  43.116 37.152 43.2 37.176 ;
    END
  END dn1_o[143]
  PIN dn1_o[144]
    DIRECTION OUTPUT ;
    USE SIGNAL ;
    PORT
      LAYER M4 ;
        RECT  43.116 37.344 43.2 37.368 ;
    END
  END dn1_o[144]
  PIN dn1_o[145]
    DIRECTION OUTPUT ;
    USE SIGNAL ;
    PORT
      LAYER M4 ;
        RECT  43.116 37.536 43.2 37.56 ;
    END
  END dn1_o[145]
  PIN dn1_o[146]
    DIRECTION OUTPUT ;
    USE SIGNAL ;
    PORT
      LAYER M4 ;
        RECT  43.116 37.728 43.2 37.752 ;
    END
  END dn1_o[146]
  PIN dn1_o[147]
    DIRECTION OUTPUT ;
    USE SIGNAL ;
    PORT
      LAYER M4 ;
        RECT  43.116 37.92 43.2 37.944 ;
    END
  END dn1_o[147]
  PIN dn1_o[148]
    DIRECTION OUTPUT ;
    USE SIGNAL ;
    PORT
      LAYER M4 ;
        RECT  43.116 38.112 43.2 38.136 ;
    END
  END dn1_o[148]
  PIN dn1_o[149]
    DIRECTION OUTPUT ;
    USE SIGNAL ;
    PORT
      LAYER M4 ;
        RECT  43.116 38.256 43.2 38.28 ;
    END
  END dn1_o[149]
  PIN dn1_o[14]
    DIRECTION OUTPUT ;
    USE SIGNAL ;
    PORT
      LAYER M4 ;
        RECT  43.116 12.672 43.2 12.696 ;
    END
  END dn1_o[14]
  PIN dn1_o[150]
    DIRECTION OUTPUT ;
    USE SIGNAL ;
    PORT
      LAYER M4 ;
        RECT  43.116 38.448 43.2 38.472 ;
    END
  END dn1_o[150]
  PIN dn1_o[151]
    DIRECTION OUTPUT ;
    USE SIGNAL ;
    PORT
      LAYER M4 ;
        RECT  43.116 38.64 43.2 38.664 ;
    END
  END dn1_o[151]
  PIN dn1_o[152]
    DIRECTION OUTPUT ;
    USE SIGNAL ;
    PORT
      LAYER M4 ;
        RECT  43.116 38.832 43.2 38.856 ;
    END
  END dn1_o[152]
  PIN dn1_o[153]
    DIRECTION OUTPUT ;
    USE SIGNAL ;
    PORT
      LAYER M4 ;
        RECT  43.116 39.024 43.2 39.048 ;
    END
  END dn1_o[153]
  PIN dn1_o[154]
    DIRECTION OUTPUT ;
    USE SIGNAL ;
    PORT
      LAYER M4 ;
        RECT  43.116 39.216 43.2 39.24 ;
    END
  END dn1_o[154]
  PIN dn1_o[155]
    DIRECTION OUTPUT ;
    USE SIGNAL ;
    PORT
      LAYER M4 ;
        RECT  43.116 39.408 43.2 39.432 ;
    END
  END dn1_o[155]
  PIN dn1_o[156]
    DIRECTION OUTPUT ;
    USE SIGNAL ;
    PORT
      LAYER M4 ;
        RECT  43.116 39.6 43.2 39.624 ;
    END
  END dn1_o[156]
  PIN dn1_o[157]
    DIRECTION OUTPUT ;
    USE SIGNAL ;
    PORT
      LAYER M4 ;
        RECT  43.116 39.792 43.2 39.816 ;
    END
  END dn1_o[157]
  PIN dn1_o[158]
    DIRECTION OUTPUT ;
    USE SIGNAL ;
    PORT
      LAYER M4 ;
        RECT  43.116 39.984 43.2 40.008 ;
    END
  END dn1_o[158]
  PIN dn1_o[159]
    DIRECTION OUTPUT ;
    USE SIGNAL ;
    PORT
      LAYER M4 ;
        RECT  43.116 40.176 43.2 40.2 ;
    END
  END dn1_o[159]
  PIN dn1_o[15]
    DIRECTION OUTPUT ;
    USE SIGNAL ;
    PORT
      LAYER M4 ;
        RECT  43.116 12.864 43.2 12.888 ;
    END
  END dn1_o[15]
  PIN dn1_o[160]
    DIRECTION OUTPUT ;
    USE SIGNAL ;
    PORT
      LAYER M4 ;
        RECT  43.116 40.368 43.2 40.392 ;
    END
  END dn1_o[160]
  PIN dn1_o[161]
    DIRECTION OUTPUT ;
    USE SIGNAL ;
    PORT
      LAYER M4 ;
        RECT  43.116 40.56 43.2 40.584 ;
    END
  END dn1_o[161]
  PIN dn1_o[162]
    DIRECTION OUTPUT ;
    USE SIGNAL ;
    PORT
      LAYER M4 ;
        RECT  43.116 40.752 43.2 40.776 ;
    END
  END dn1_o[162]
  PIN dn1_o[163]
    DIRECTION OUTPUT ;
    USE SIGNAL ;
    PORT
      LAYER M4 ;
        RECT  43.116 40.944 43.2 40.968 ;
    END
  END dn1_o[163]
  PIN dn1_o[16]
    DIRECTION OUTPUT ;
    USE SIGNAL ;
    PORT
      LAYER M4 ;
        RECT  43.116 13.056 43.2 13.08 ;
    END
  END dn1_o[16]
  PIN dn1_o[17]
    DIRECTION OUTPUT ;
    USE SIGNAL ;
    PORT
      LAYER M4 ;
        RECT  43.116 13.248 43.2 13.272 ;
    END
  END dn1_o[17]
  PIN dn1_o[18]
    DIRECTION OUTPUT ;
    USE SIGNAL ;
    PORT
      LAYER M4 ;
        RECT  43.116 13.44 43.2 13.464 ;
    END
  END dn1_o[18]
  PIN dn1_o[19]
    DIRECTION OUTPUT ;
    USE SIGNAL ;
    PORT
      LAYER M4 ;
        RECT  43.116 13.632 43.2 13.656 ;
    END
  END dn1_o[19]
  PIN dn1_o[1]
    DIRECTION OUTPUT ;
    USE SIGNAL ;
    PORT
      LAYER M4 ;
        RECT  43.116 10.224 43.2 10.248 ;
    END
  END dn1_o[1]
  PIN dn1_o[20]
    DIRECTION OUTPUT ;
    USE SIGNAL ;
    PORT
      LAYER M4 ;
        RECT  43.116 13.824 43.2 13.848 ;
    END
  END dn1_o[20]
  PIN dn1_o[21]
    DIRECTION OUTPUT ;
    USE SIGNAL ;
    PORT
      LAYER M4 ;
        RECT  43.116 14.016 43.2 14.04 ;
    END
  END dn1_o[21]
  PIN dn1_o[22]
    DIRECTION OUTPUT ;
    USE SIGNAL ;
    PORT
      LAYER M4 ;
        RECT  43.116 14.208 43.2 14.232 ;
    END
  END dn1_o[22]
  PIN dn1_o[23]
    DIRECTION OUTPUT ;
    USE SIGNAL ;
    PORT
      LAYER M4 ;
        RECT  43.116 14.4 43.2 14.424 ;
    END
  END dn1_o[23]
  PIN dn1_o[24]
    DIRECTION OUTPUT ;
    USE SIGNAL ;
    PORT
      LAYER M4 ;
        RECT  43.116 14.592 43.2 14.616 ;
    END
  END dn1_o[24]
  PIN dn1_o[25]
    DIRECTION OUTPUT ;
    USE SIGNAL ;
    PORT
      LAYER M4 ;
        RECT  43.116 14.784 43.2 14.808 ;
    END
  END dn1_o[25]
  PIN dn1_o[26]
    DIRECTION OUTPUT ;
    USE SIGNAL ;
    PORT
      LAYER M4 ;
        RECT  43.116 14.928 43.2 14.952 ;
    END
  END dn1_o[26]
  PIN dn1_o[27]
    DIRECTION OUTPUT ;
    USE SIGNAL ;
    PORT
      LAYER M4 ;
        RECT  43.116 15.12 43.2 15.144 ;
    END
  END dn1_o[27]
  PIN dn1_o[28]
    DIRECTION OUTPUT ;
    USE SIGNAL ;
    PORT
      LAYER M4 ;
        RECT  43.116 15.312 43.2 15.336 ;
    END
  END dn1_o[28]
  PIN dn1_o[29]
    DIRECTION OUTPUT ;
    USE SIGNAL ;
    PORT
      LAYER M4 ;
        RECT  43.116 15.504 43.2 15.528 ;
    END
  END dn1_o[29]
  PIN dn1_o[2]
    DIRECTION OUTPUT ;
    USE SIGNAL ;
    PORT
      LAYER M4 ;
        RECT  43.116 10.416 43.2 10.44 ;
    END
  END dn1_o[2]
  PIN dn1_o[30]
    DIRECTION OUTPUT ;
    USE SIGNAL ;
    PORT
      LAYER M4 ;
        RECT  43.116 15.696 43.2 15.72 ;
    END
  END dn1_o[30]
  PIN dn1_o[31]
    DIRECTION OUTPUT ;
    USE SIGNAL ;
    PORT
      LAYER M4 ;
        RECT  43.116 15.888 43.2 15.912 ;
    END
  END dn1_o[31]
  PIN dn1_o[32]
    DIRECTION OUTPUT ;
    USE SIGNAL ;
    PORT
      LAYER M4 ;
        RECT  43.116 16.08 43.2 16.104 ;
    END
  END dn1_o[32]
  PIN dn1_o[33]
    DIRECTION OUTPUT ;
    USE SIGNAL ;
    PORT
      LAYER M4 ;
        RECT  43.116 16.272 43.2 16.296 ;
    END
  END dn1_o[33]
  PIN dn1_o[34]
    DIRECTION OUTPUT ;
    USE SIGNAL ;
    PORT
      LAYER M4 ;
        RECT  43.116 16.464 43.2 16.488 ;
    END
  END dn1_o[34]
  PIN dn1_o[35]
    DIRECTION OUTPUT ;
    USE SIGNAL ;
    PORT
      LAYER M4 ;
        RECT  43.116 16.656 43.2 16.68 ;
    END
  END dn1_o[35]
  PIN dn1_o[36]
    DIRECTION OUTPUT ;
    USE SIGNAL ;
    PORT
      LAYER M4 ;
        RECT  43.116 16.848 43.2 16.872 ;
    END
  END dn1_o[36]
  PIN dn1_o[37]
    DIRECTION OUTPUT ;
    USE SIGNAL ;
    PORT
      LAYER M4 ;
        RECT  43.116 17.04 43.2 17.064 ;
    END
  END dn1_o[37]
  PIN dn1_o[38]
    DIRECTION OUTPUT ;
    USE SIGNAL ;
    PORT
      LAYER M4 ;
        RECT  43.116 17.232 43.2 17.256 ;
    END
  END dn1_o[38]
  PIN dn1_o[39]
    DIRECTION OUTPUT ;
    USE SIGNAL ;
    PORT
      LAYER M4 ;
        RECT  43.116 17.424 43.2 17.448 ;
    END
  END dn1_o[39]
  PIN dn1_o[3]
    DIRECTION OUTPUT ;
    USE SIGNAL ;
    PORT
      LAYER M4 ;
        RECT  43.116 10.608 43.2 10.632 ;
    END
  END dn1_o[3]
  PIN dn1_o[40]
    DIRECTION OUTPUT ;
    USE SIGNAL ;
    PORT
      LAYER M4 ;
        RECT  43.116 17.616 43.2 17.64 ;
    END
  END dn1_o[40]
  PIN dn1_o[41]
    DIRECTION OUTPUT ;
    USE SIGNAL ;
    PORT
      LAYER M4 ;
        RECT  43.116 17.808 43.2 17.832 ;
    END
  END dn1_o[41]
  PIN dn1_o[42]
    DIRECTION OUTPUT ;
    USE SIGNAL ;
    PORT
      LAYER M4 ;
        RECT  43.116 18 43.2 18.024 ;
    END
  END dn1_o[42]
  PIN dn1_o[43]
    DIRECTION OUTPUT ;
    USE SIGNAL ;
    PORT
      LAYER M4 ;
        RECT  43.116 18.192 43.2 18.216 ;
    END
  END dn1_o[43]
  PIN dn1_o[44]
    DIRECTION OUTPUT ;
    USE SIGNAL ;
    PORT
      LAYER M4 ;
        RECT  43.116 18.384 43.2 18.408 ;
    END
  END dn1_o[44]
  PIN dn1_o[45]
    DIRECTION OUTPUT ;
    USE SIGNAL ;
    PORT
      LAYER M4 ;
        RECT  43.116 18.576 43.2 18.6 ;
    END
  END dn1_o[45]
  PIN dn1_o[46]
    DIRECTION OUTPUT ;
    USE SIGNAL ;
    PORT
      LAYER M4 ;
        RECT  43.116 18.72 43.2 18.744 ;
    END
  END dn1_o[46]
  PIN dn1_o[47]
    DIRECTION OUTPUT ;
    USE SIGNAL ;
    PORT
      LAYER M4 ;
        RECT  43.116 18.912 43.2 18.936 ;
    END
  END dn1_o[47]
  PIN dn1_o[48]
    DIRECTION OUTPUT ;
    USE SIGNAL ;
    PORT
      LAYER M4 ;
        RECT  43.116 19.104 43.2 19.128 ;
    END
  END dn1_o[48]
  PIN dn1_o[49]
    DIRECTION OUTPUT ;
    USE SIGNAL ;
    PORT
      LAYER M4 ;
        RECT  43.116 19.296 43.2 19.32 ;
    END
  END dn1_o[49]
  PIN dn1_o[4]
    DIRECTION OUTPUT ;
    USE SIGNAL ;
    PORT
      LAYER M4 ;
        RECT  43.116 10.8 43.2 10.824 ;
    END
  END dn1_o[4]
  PIN dn1_o[50]
    DIRECTION OUTPUT ;
    USE SIGNAL ;
    PORT
      LAYER M4 ;
        RECT  43.116 19.488 43.2 19.512 ;
    END
  END dn1_o[50]
  PIN dn1_o[51]
    DIRECTION OUTPUT ;
    USE SIGNAL ;
    PORT
      LAYER M4 ;
        RECT  43.116 19.68 43.2 19.704 ;
    END
  END dn1_o[51]
  PIN dn1_o[52]
    DIRECTION OUTPUT ;
    USE SIGNAL ;
    PORT
      LAYER M4 ;
        RECT  43.116 19.872 43.2 19.896 ;
    END
  END dn1_o[52]
  PIN dn1_o[53]
    DIRECTION OUTPUT ;
    USE SIGNAL ;
    PORT
      LAYER M4 ;
        RECT  43.116 20.064 43.2 20.088 ;
    END
  END dn1_o[53]
  PIN dn1_o[54]
    DIRECTION OUTPUT ;
    USE SIGNAL ;
    PORT
      LAYER M4 ;
        RECT  43.116 20.256 43.2 20.28 ;
    END
  END dn1_o[54]
  PIN dn1_o[55]
    DIRECTION OUTPUT ;
    USE SIGNAL ;
    PORT
      LAYER M4 ;
        RECT  43.116 20.448 43.2 20.472 ;
    END
  END dn1_o[55]
  PIN dn1_o[56]
    DIRECTION OUTPUT ;
    USE SIGNAL ;
    PORT
      LAYER M4 ;
        RECT  43.116 20.64 43.2 20.664 ;
    END
  END dn1_o[56]
  PIN dn1_o[57]
    DIRECTION OUTPUT ;
    USE SIGNAL ;
    PORT
      LAYER M4 ;
        RECT  43.116 20.832 43.2 20.856 ;
    END
  END dn1_o[57]
  PIN dn1_o[58]
    DIRECTION OUTPUT ;
    USE SIGNAL ;
    PORT
      LAYER M4 ;
        RECT  43.116 21.024 43.2 21.048 ;
    END
  END dn1_o[58]
  PIN dn1_o[59]
    DIRECTION OUTPUT ;
    USE SIGNAL ;
    PORT
      LAYER M4 ;
        RECT  43.116 21.216 43.2 21.24 ;
    END
  END dn1_o[59]
  PIN dn1_o[5]
    DIRECTION OUTPUT ;
    USE SIGNAL ;
    PORT
      LAYER M4 ;
        RECT  43.116 10.944 43.2 10.968 ;
    END
  END dn1_o[5]
  PIN dn1_o[60]
    DIRECTION OUTPUT ;
    USE SIGNAL ;
    PORT
      LAYER M4 ;
        RECT  43.116 21.408 43.2 21.432 ;
    END
  END dn1_o[60]
  PIN dn1_o[61]
    DIRECTION OUTPUT ;
    USE SIGNAL ;
    PORT
      LAYER M4 ;
        RECT  43.116 21.6 43.2 21.624 ;
    END
  END dn1_o[61]
  PIN dn1_o[62]
    DIRECTION OUTPUT ;
    USE SIGNAL ;
    PORT
      LAYER M4 ;
        RECT  43.116 21.792 43.2 21.816 ;
    END
  END dn1_o[62]
  PIN dn1_o[63]
    DIRECTION OUTPUT ;
    USE SIGNAL ;
    PORT
      LAYER M4 ;
        RECT  43.116 21.984 43.2 22.008 ;
    END
  END dn1_o[63]
  PIN dn1_o[64]
    DIRECTION OUTPUT ;
    USE SIGNAL ;
    PORT
      LAYER M4 ;
        RECT  43.116 22.176 43.2 22.2 ;
    END
  END dn1_o[64]
  PIN dn1_o[65]
    DIRECTION OUTPUT ;
    USE SIGNAL ;
    PORT
      LAYER M4 ;
        RECT  43.116 22.368 43.2 22.392 ;
    END
  END dn1_o[65]
  PIN dn1_o[66]
    DIRECTION OUTPUT ;
    USE SIGNAL ;
    PORT
      LAYER M4 ;
        RECT  43.116 22.56 43.2 22.584 ;
    END
  END dn1_o[66]
  PIN dn1_o[67]
    DIRECTION OUTPUT ;
    USE SIGNAL ;
    PORT
      LAYER M4 ;
        RECT  43.116 22.704 43.2 22.728 ;
    END
  END dn1_o[67]
  PIN dn1_o[68]
    DIRECTION OUTPUT ;
    USE SIGNAL ;
    PORT
      LAYER M4 ;
        RECT  43.116 22.896 43.2 22.92 ;
    END
  END dn1_o[68]
  PIN dn1_o[69]
    DIRECTION OUTPUT ;
    USE SIGNAL ;
    PORT
      LAYER M4 ;
        RECT  43.116 23.088 43.2 23.112 ;
    END
  END dn1_o[69]
  PIN dn1_o[6]
    DIRECTION OUTPUT ;
    USE SIGNAL ;
    PORT
      LAYER M4 ;
        RECT  43.116 11.136 43.2 11.16 ;
    END
  END dn1_o[6]
  PIN dn1_o[70]
    DIRECTION OUTPUT ;
    USE SIGNAL ;
    PORT
      LAYER M4 ;
        RECT  43.116 23.28 43.2 23.304 ;
    END
  END dn1_o[70]
  PIN dn1_o[71]
    DIRECTION OUTPUT ;
    USE SIGNAL ;
    PORT
      LAYER M4 ;
        RECT  43.116 23.472 43.2 23.496 ;
    END
  END dn1_o[71]
  PIN dn1_o[72]
    DIRECTION OUTPUT ;
    USE SIGNAL ;
    PORT
      LAYER M4 ;
        RECT  43.116 23.664 43.2 23.688 ;
    END
  END dn1_o[72]
  PIN dn1_o[73]
    DIRECTION OUTPUT ;
    USE SIGNAL ;
    PORT
      LAYER M4 ;
        RECT  43.116 23.856 43.2 23.88 ;
    END
  END dn1_o[73]
  PIN dn1_o[74]
    DIRECTION OUTPUT ;
    USE SIGNAL ;
    PORT
      LAYER M4 ;
        RECT  43.116 24.048 43.2 24.072 ;
    END
  END dn1_o[74]
  PIN dn1_o[75]
    DIRECTION OUTPUT ;
    USE SIGNAL ;
    PORT
      LAYER M4 ;
        RECT  43.116 24.24 43.2 24.264 ;
    END
  END dn1_o[75]
  PIN dn1_o[76]
    DIRECTION OUTPUT ;
    USE SIGNAL ;
    PORT
      LAYER M4 ;
        RECT  43.116 24.432 43.2 24.456 ;
    END
  END dn1_o[76]
  PIN dn1_o[77]
    DIRECTION OUTPUT ;
    USE SIGNAL ;
    PORT
      LAYER M4 ;
        RECT  43.116 24.624 43.2 24.648 ;
    END
  END dn1_o[77]
  PIN dn1_o[78]
    DIRECTION OUTPUT ;
    USE SIGNAL ;
    PORT
      LAYER M4 ;
        RECT  43.116 24.816 43.2 24.84 ;
    END
  END dn1_o[78]
  PIN dn1_o[79]
    DIRECTION OUTPUT ;
    USE SIGNAL ;
    PORT
      LAYER M4 ;
        RECT  43.116 25.008 43.2 25.032 ;
    END
  END dn1_o[79]
  PIN dn1_o[7]
    DIRECTION OUTPUT ;
    USE SIGNAL ;
    PORT
      LAYER M4 ;
        RECT  43.116 11.328 43.2 11.352 ;
    END
  END dn1_o[7]
  PIN dn1_o[80]
    DIRECTION OUTPUT ;
    USE SIGNAL ;
    PORT
      LAYER M4 ;
        RECT  43.116 25.2 43.2 25.224 ;
    END
  END dn1_o[80]
  PIN dn1_o[81]
    DIRECTION OUTPUT ;
    USE SIGNAL ;
    PORT
      LAYER M4 ;
        RECT  43.116 25.392 43.2 25.416 ;
    END
  END dn1_o[81]
  PIN dn1_o[82]
    DIRECTION OUTPUT ;
    USE SIGNAL ;
    PORT
      LAYER M4 ;
        RECT  43.116 25.584 43.2 25.608 ;
    END
  END dn1_o[82]
  PIN dn1_o[83]
    DIRECTION OUTPUT ;
    USE SIGNAL ;
    PORT
      LAYER M4 ;
        RECT  43.116 25.776 43.2 25.8 ;
    END
  END dn1_o[83]
  PIN dn1_o[84]
    DIRECTION OUTPUT ;
    USE SIGNAL ;
    PORT
      LAYER M4 ;
        RECT  43.116 25.968 43.2 25.992 ;
    END
  END dn1_o[84]
  PIN dn1_o[85]
    DIRECTION OUTPUT ;
    USE SIGNAL ;
    PORT
      LAYER M4 ;
        RECT  43.116 26.16 43.2 26.184 ;
    END
  END dn1_o[85]
  PIN dn1_o[86]
    DIRECTION OUTPUT ;
    USE SIGNAL ;
    PORT
      LAYER M4 ;
        RECT  43.116 26.352 43.2 26.376 ;
    END
  END dn1_o[86]
  PIN dn1_o[87]
    DIRECTION OUTPUT ;
    USE SIGNAL ;
    PORT
      LAYER M4 ;
        RECT  43.116 26.496 43.2 26.52 ;
    END
  END dn1_o[87]
  PIN dn1_o[88]
    DIRECTION OUTPUT ;
    USE SIGNAL ;
    PORT
      LAYER M4 ;
        RECT  43.116 26.688 43.2 26.712 ;
    END
  END dn1_o[88]
  PIN dn1_o[89]
    DIRECTION OUTPUT ;
    USE SIGNAL ;
    PORT
      LAYER M4 ;
        RECT  43.116 26.88 43.2 26.904 ;
    END
  END dn1_o[89]
  PIN dn1_o[8]
    DIRECTION OUTPUT ;
    USE SIGNAL ;
    PORT
      LAYER M4 ;
        RECT  43.116 11.52 43.2 11.544 ;
    END
  END dn1_o[8]
  PIN dn1_o[90]
    DIRECTION OUTPUT ;
    USE SIGNAL ;
    PORT
      LAYER M4 ;
        RECT  43.116 27.072 43.2 27.096 ;
    END
  END dn1_o[90]
  PIN dn1_o[91]
    DIRECTION OUTPUT ;
    USE SIGNAL ;
    PORT
      LAYER M4 ;
        RECT  43.116 27.264 43.2 27.288 ;
    END
  END dn1_o[91]
  PIN dn1_o[92]
    DIRECTION OUTPUT ;
    USE SIGNAL ;
    PORT
      LAYER M4 ;
        RECT  43.116 27.456 43.2 27.48 ;
    END
  END dn1_o[92]
  PIN dn1_o[93]
    DIRECTION OUTPUT ;
    USE SIGNAL ;
    PORT
      LAYER M4 ;
        RECT  43.116 27.648 43.2 27.672 ;
    END
  END dn1_o[93]
  PIN dn1_o[94]
    DIRECTION OUTPUT ;
    USE SIGNAL ;
    PORT
      LAYER M4 ;
        RECT  43.116 27.84 43.2 27.864 ;
    END
  END dn1_o[94]
  PIN dn1_o[95]
    DIRECTION OUTPUT ;
    USE SIGNAL ;
    PORT
      LAYER M4 ;
        RECT  43.116 28.032 43.2 28.056 ;
    END
  END dn1_o[95]
  PIN dn1_o[96]
    DIRECTION OUTPUT ;
    USE SIGNAL ;
    PORT
      LAYER M4 ;
        RECT  43.116 28.224 43.2 28.248 ;
    END
  END dn1_o[96]
  PIN dn1_o[97]
    DIRECTION OUTPUT ;
    USE SIGNAL ;
    PORT
      LAYER M4 ;
        RECT  43.116 28.416 43.2 28.44 ;
    END
  END dn1_o[97]
  PIN dn1_o[98]
    DIRECTION OUTPUT ;
    USE SIGNAL ;
    PORT
      LAYER M4 ;
        RECT  43.116 28.608 43.2 28.632 ;
    END
  END dn1_o[98]
  PIN dn1_o[99]
    DIRECTION OUTPUT ;
    USE SIGNAL ;
    PORT
      LAYER M4 ;
        RECT  43.116 28.8 43.2 28.824 ;
    END
  END dn1_o[99]
  PIN dn1_o[9]
    DIRECTION OUTPUT ;
    USE SIGNAL ;
    PORT
      LAYER M4 ;
        RECT  43.116 11.712 43.2 11.736 ;
    END
  END dn1_o[9]
  PIN dn2_o[0]
    DIRECTION OUTPUT ;
    USE SIGNAL ;
    PORT
      LAYER M4 ;
        RECT  0 9.072 0.084 9.096 ;
    END
  END dn2_o[0]
  PIN dn2_o[100]
    DIRECTION OUTPUT ;
    USE SIGNAL ;
    PORT
      LAYER M4 ;
        RECT  0 25.536 0.084 25.56 ;
    END
  END dn2_o[100]
  PIN dn2_o[101]
    DIRECTION OUTPUT ;
    USE SIGNAL ;
    PORT
      LAYER M4 ;
        RECT  0 25.68 0.084 25.704 ;
    END
  END dn2_o[101]
  PIN dn2_o[102]
    DIRECTION OUTPUT ;
    USE SIGNAL ;
    PORT
      LAYER M4 ;
        RECT  0 25.872 0.084 25.896 ;
    END
  END dn2_o[102]
  PIN dn2_o[103]
    DIRECTION OUTPUT ;
    USE SIGNAL ;
    PORT
      LAYER M4 ;
        RECT  0 26.016 0.084 26.04 ;
    END
  END dn2_o[103]
  PIN dn2_o[104]
    DIRECTION OUTPUT ;
    USE SIGNAL ;
    PORT
      LAYER M4 ;
        RECT  0 26.208 0.084 26.232 ;
    END
  END dn2_o[104]
  PIN dn2_o[105]
    DIRECTION OUTPUT ;
    USE SIGNAL ;
    PORT
      LAYER M4 ;
        RECT  0 26.352 0.084 26.376 ;
    END
  END dn2_o[105]
  PIN dn2_o[106]
    DIRECTION OUTPUT ;
    USE SIGNAL ;
    PORT
      LAYER M4 ;
        RECT  0 26.544 0.084 26.568 ;
    END
  END dn2_o[106]
  PIN dn2_o[107]
    DIRECTION OUTPUT ;
    USE SIGNAL ;
    PORT
      LAYER M4 ;
        RECT  0 26.688 0.084 26.712 ;
    END
  END dn2_o[107]
  PIN dn2_o[108]
    DIRECTION OUTPUT ;
    USE SIGNAL ;
    PORT
      LAYER M4 ;
        RECT  0 26.832 0.084 26.856 ;
    END
  END dn2_o[108]
  PIN dn2_o[109]
    DIRECTION OUTPUT ;
    USE SIGNAL ;
    PORT
      LAYER M4 ;
        RECT  0 27.024 0.084 27.048 ;
    END
  END dn2_o[109]
  PIN dn2_o[10]
    DIRECTION OUTPUT ;
    USE SIGNAL ;
    PORT
      LAYER M4 ;
        RECT  0 10.704 0.084 10.728 ;
    END
  END dn2_o[10]
  PIN dn2_o[110]
    DIRECTION OUTPUT ;
    USE SIGNAL ;
    PORT
      LAYER M4 ;
        RECT  0 27.168 0.084 27.192 ;
    END
  END dn2_o[110]
  PIN dn2_o[111]
    DIRECTION OUTPUT ;
    USE SIGNAL ;
    PORT
      LAYER M4 ;
        RECT  0 27.36 0.084 27.384 ;
    END
  END dn2_o[111]
  PIN dn2_o[112]
    DIRECTION OUTPUT ;
    USE SIGNAL ;
    PORT
      LAYER M4 ;
        RECT  0 27.504 0.084 27.528 ;
    END
  END dn2_o[112]
  PIN dn2_o[113]
    DIRECTION OUTPUT ;
    USE SIGNAL ;
    PORT
      LAYER M4 ;
        RECT  0 27.696 0.084 27.72 ;
    END
  END dn2_o[113]
  PIN dn2_o[114]
    DIRECTION OUTPUT ;
    USE SIGNAL ;
    PORT
      LAYER M4 ;
        RECT  0 27.84 0.084 27.864 ;
    END
  END dn2_o[114]
  PIN dn2_o[115]
    DIRECTION OUTPUT ;
    USE SIGNAL ;
    PORT
      LAYER M4 ;
        RECT  0 27.984 0.084 28.008 ;
    END
  END dn2_o[115]
  PIN dn2_o[116]
    DIRECTION OUTPUT ;
    USE SIGNAL ;
    PORT
      LAYER M4 ;
        RECT  0 28.176 0.084 28.2 ;
    END
  END dn2_o[116]
  PIN dn2_o[117]
    DIRECTION OUTPUT ;
    USE SIGNAL ;
    PORT
      LAYER M4 ;
        RECT  0 28.32 0.084 28.344 ;
    END
  END dn2_o[117]
  PIN dn2_o[118]
    DIRECTION OUTPUT ;
    USE SIGNAL ;
    PORT
      LAYER M4 ;
        RECT  0 28.512 0.084 28.536 ;
    END
  END dn2_o[118]
  PIN dn2_o[119]
    DIRECTION OUTPUT ;
    USE SIGNAL ;
    PORT
      LAYER M4 ;
        RECT  0 28.656 0.084 28.68 ;
    END
  END dn2_o[119]
  PIN dn2_o[11]
    DIRECTION OUTPUT ;
    USE SIGNAL ;
    PORT
      LAYER M4 ;
        RECT  0 10.896 0.084 10.92 ;
    END
  END dn2_o[11]
  PIN dn2_o[120]
    DIRECTION OUTPUT ;
    USE SIGNAL ;
    PORT
      LAYER M4 ;
        RECT  0 28.848 0.084 28.872 ;
    END
  END dn2_o[120]
  PIN dn2_o[121]
    DIRECTION OUTPUT ;
    USE SIGNAL ;
    PORT
      LAYER M4 ;
        RECT  0 28.992 0.084 29.016 ;
    END
  END dn2_o[121]
  PIN dn2_o[122]
    DIRECTION OUTPUT ;
    USE SIGNAL ;
    PORT
      LAYER M4 ;
        RECT  0 29.136 0.084 29.16 ;
    END
  END dn2_o[122]
  PIN dn2_o[123]
    DIRECTION OUTPUT ;
    USE SIGNAL ;
    PORT
      LAYER M4 ;
        RECT  0 29.328 0.084 29.352 ;
    END
  END dn2_o[123]
  PIN dn2_o[124]
    DIRECTION OUTPUT ;
    USE SIGNAL ;
    PORT
      LAYER M4 ;
        RECT  0 29.472 0.084 29.496 ;
    END
  END dn2_o[124]
  PIN dn2_o[125]
    DIRECTION OUTPUT ;
    USE SIGNAL ;
    PORT
      LAYER M4 ;
        RECT  0 29.664 0.084 29.688 ;
    END
  END dn2_o[125]
  PIN dn2_o[126]
    DIRECTION OUTPUT ;
    USE SIGNAL ;
    PORT
      LAYER M4 ;
        RECT  0 29.808 0.084 29.832 ;
    END
  END dn2_o[126]
  PIN dn2_o[127]
    DIRECTION OUTPUT ;
    USE SIGNAL ;
    PORT
      LAYER M4 ;
        RECT  0 30 0.084 30.024 ;
    END
  END dn2_o[127]
  PIN dn2_o[128]
    DIRECTION OUTPUT ;
    USE SIGNAL ;
    PORT
      LAYER M4 ;
        RECT  0 30.144 0.084 30.168 ;
    END
  END dn2_o[128]
  PIN dn2_o[129]
    DIRECTION OUTPUT ;
    USE SIGNAL ;
    PORT
      LAYER M4 ;
        RECT  0 30.288 0.084 30.312 ;
    END
  END dn2_o[129]
  PIN dn2_o[12]
    DIRECTION OUTPUT ;
    USE SIGNAL ;
    PORT
      LAYER M4 ;
        RECT  0 11.04 0.084 11.064 ;
    END
  END dn2_o[12]
  PIN dn2_o[130]
    DIRECTION OUTPUT ;
    USE SIGNAL ;
    PORT
      LAYER M4 ;
        RECT  0 30.48 0.084 30.504 ;
    END
  END dn2_o[130]
  PIN dn2_o[131]
    DIRECTION OUTPUT ;
    USE SIGNAL ;
    PORT
      LAYER M4 ;
        RECT  0 30.624 0.084 30.648 ;
    END
  END dn2_o[131]
  PIN dn2_o[132]
    DIRECTION OUTPUT ;
    USE SIGNAL ;
    PORT
      LAYER M4 ;
        RECT  0 30.816 0.084 30.84 ;
    END
  END dn2_o[132]
  PIN dn2_o[133]
    DIRECTION OUTPUT ;
    USE SIGNAL ;
    PORT
      LAYER M4 ;
        RECT  0 30.96 0.084 30.984 ;
    END
  END dn2_o[133]
  PIN dn2_o[134]
    DIRECTION OUTPUT ;
    USE SIGNAL ;
    PORT
      LAYER M4 ;
        RECT  0 31.152 0.084 31.176 ;
    END
  END dn2_o[134]
  PIN dn2_o[135]
    DIRECTION OUTPUT ;
    USE SIGNAL ;
    PORT
      LAYER M4 ;
        RECT  0 31.296 0.084 31.32 ;
    END
  END dn2_o[135]
  PIN dn2_o[136]
    DIRECTION OUTPUT ;
    USE SIGNAL ;
    PORT
      LAYER M4 ;
        RECT  0 31.44 0.084 31.464 ;
    END
  END dn2_o[136]
  PIN dn2_o[137]
    DIRECTION OUTPUT ;
    USE SIGNAL ;
    PORT
      LAYER M4 ;
        RECT  0 31.632 0.084 31.656 ;
    END
  END dn2_o[137]
  PIN dn2_o[138]
    DIRECTION OUTPUT ;
    USE SIGNAL ;
    PORT
      LAYER M4 ;
        RECT  0 31.776 0.084 31.8 ;
    END
  END dn2_o[138]
  PIN dn2_o[139]
    DIRECTION OUTPUT ;
    USE SIGNAL ;
    PORT
      LAYER M4 ;
        RECT  0 31.968 0.084 31.992 ;
    END
  END dn2_o[139]
  PIN dn2_o[13]
    DIRECTION OUTPUT ;
    USE SIGNAL ;
    PORT
      LAYER M4 ;
        RECT  0 11.232 0.084 11.256 ;
    END
  END dn2_o[13]
  PIN dn2_o[140]
    DIRECTION OUTPUT ;
    USE SIGNAL ;
    PORT
      LAYER M4 ;
        RECT  0 32.112 0.084 32.136 ;
    END
  END dn2_o[140]
  PIN dn2_o[141]
    DIRECTION OUTPUT ;
    USE SIGNAL ;
    PORT
      LAYER M4 ;
        RECT  0 32.304 0.084 32.328 ;
    END
  END dn2_o[141]
  PIN dn2_o[142]
    DIRECTION OUTPUT ;
    USE SIGNAL ;
    PORT
      LAYER M4 ;
        RECT  0 32.448 0.084 32.472 ;
    END
  END dn2_o[142]
  PIN dn2_o[143]
    DIRECTION OUTPUT ;
    USE SIGNAL ;
    PORT
      LAYER M4 ;
        RECT  0 32.592 0.084 32.616 ;
    END
  END dn2_o[143]
  PIN dn2_o[144]
    DIRECTION OUTPUT ;
    USE SIGNAL ;
    PORT
      LAYER M4 ;
        RECT  0 32.784 0.084 32.808 ;
    END
  END dn2_o[144]
  PIN dn2_o[145]
    DIRECTION OUTPUT ;
    USE SIGNAL ;
    PORT
      LAYER M4 ;
        RECT  0 32.928 0.084 32.952 ;
    END
  END dn2_o[145]
  PIN dn2_o[146]
    DIRECTION OUTPUT ;
    USE SIGNAL ;
    PORT
      LAYER M4 ;
        RECT  0 33.12 0.084 33.144 ;
    END
  END dn2_o[146]
  PIN dn2_o[147]
    DIRECTION OUTPUT ;
    USE SIGNAL ;
    PORT
      LAYER M4 ;
        RECT  0 33.264 0.084 33.288 ;
    END
  END dn2_o[147]
  PIN dn2_o[148]
    DIRECTION OUTPUT ;
    USE SIGNAL ;
    PORT
      LAYER M4 ;
        RECT  0 33.456 0.084 33.48 ;
    END
  END dn2_o[148]
  PIN dn2_o[149]
    DIRECTION OUTPUT ;
    USE SIGNAL ;
    PORT
      LAYER M4 ;
        RECT  0 33.6 0.084 33.624 ;
    END
  END dn2_o[149]
  PIN dn2_o[14]
    DIRECTION OUTPUT ;
    USE SIGNAL ;
    PORT
      LAYER M4 ;
        RECT  0 11.376 0.084 11.4 ;
    END
  END dn2_o[14]
  PIN dn2_o[150]
    DIRECTION OUTPUT ;
    USE SIGNAL ;
    PORT
      LAYER M4 ;
        RECT  0 33.744 0.084 33.768 ;
    END
  END dn2_o[150]
  PIN dn2_o[151]
    DIRECTION OUTPUT ;
    USE SIGNAL ;
    PORT
      LAYER M4 ;
        RECT  0 33.936 0.084 33.96 ;
    END
  END dn2_o[151]
  PIN dn2_o[152]
    DIRECTION OUTPUT ;
    USE SIGNAL ;
    PORT
      LAYER M4 ;
        RECT  0 34.08 0.084 34.104 ;
    END
  END dn2_o[152]
  PIN dn2_o[153]
    DIRECTION OUTPUT ;
    USE SIGNAL ;
    PORT
      LAYER M4 ;
        RECT  0 34.272 0.084 34.296 ;
    END
  END dn2_o[153]
  PIN dn2_o[154]
    DIRECTION OUTPUT ;
    USE SIGNAL ;
    PORT
      LAYER M4 ;
        RECT  0 34.416 0.084 34.44 ;
    END
  END dn2_o[154]
  PIN dn2_o[155]
    DIRECTION OUTPUT ;
    USE SIGNAL ;
    PORT
      LAYER M4 ;
        RECT  0 34.608 0.084 34.632 ;
    END
  END dn2_o[155]
  PIN dn2_o[156]
    DIRECTION OUTPUT ;
    USE SIGNAL ;
    PORT
      LAYER M4 ;
        RECT  0 34.752 0.084 34.776 ;
    END
  END dn2_o[156]
  PIN dn2_o[157]
    DIRECTION OUTPUT ;
    USE SIGNAL ;
    PORT
      LAYER M4 ;
        RECT  0 34.896 0.084 34.92 ;
    END
  END dn2_o[157]
  PIN dn2_o[158]
    DIRECTION OUTPUT ;
    USE SIGNAL ;
    PORT
      LAYER M4 ;
        RECT  0 35.088 0.084 35.112 ;
    END
  END dn2_o[158]
  PIN dn2_o[159]
    DIRECTION OUTPUT ;
    USE SIGNAL ;
    PORT
      LAYER M4 ;
        RECT  0 35.232 0.084 35.256 ;
    END
  END dn2_o[159]
  PIN dn2_o[15]
    DIRECTION OUTPUT ;
    USE SIGNAL ;
    PORT
      LAYER M4 ;
        RECT  0 11.52 0.084 11.544 ;
    END
  END dn2_o[15]
  PIN dn2_o[160]
    DIRECTION OUTPUT ;
    USE SIGNAL ;
    PORT
      LAYER M4 ;
        RECT  0 35.424 0.084 35.448 ;
    END
  END dn2_o[160]
  PIN dn2_o[161]
    DIRECTION OUTPUT ;
    USE SIGNAL ;
    PORT
      LAYER M4 ;
        RECT  0 35.568 0.084 35.592 ;
    END
  END dn2_o[161]
  PIN dn2_o[162]
    DIRECTION OUTPUT ;
    USE SIGNAL ;
    PORT
      LAYER M4 ;
        RECT  0 35.76 0.084 35.784 ;
    END
  END dn2_o[162]
  PIN dn2_o[163]
    DIRECTION OUTPUT ;
    USE SIGNAL ;
    PORT
      LAYER M4 ;
        RECT  0 35.904 0.084 35.928 ;
    END
  END dn2_o[163]
  PIN dn2_o[16]
    DIRECTION OUTPUT ;
    USE SIGNAL ;
    PORT
      LAYER M4 ;
        RECT  0 11.712 0.084 11.736 ;
    END
  END dn2_o[16]
  PIN dn2_o[17]
    DIRECTION OUTPUT ;
    USE SIGNAL ;
    PORT
      LAYER M4 ;
        RECT  0 11.856 0.084 11.88 ;
    END
  END dn2_o[17]
  PIN dn2_o[18]
    DIRECTION OUTPUT ;
    USE SIGNAL ;
    PORT
      LAYER M4 ;
        RECT  0 12.048 0.084 12.072 ;
    END
  END dn2_o[18]
  PIN dn2_o[19]
    DIRECTION OUTPUT ;
    USE SIGNAL ;
    PORT
      LAYER M4 ;
        RECT  0 12.192 0.084 12.216 ;
    END
  END dn2_o[19]
  PIN dn2_o[1]
    DIRECTION OUTPUT ;
    USE SIGNAL ;
    PORT
      LAYER M4 ;
        RECT  0 9.216 0.084 9.24 ;
    END
  END dn2_o[1]
  PIN dn2_o[20]
    DIRECTION OUTPUT ;
    USE SIGNAL ;
    PORT
      LAYER M4 ;
        RECT  0 12.384 0.084 12.408 ;
    END
  END dn2_o[20]
  PIN dn2_o[21]
    DIRECTION OUTPUT ;
    USE SIGNAL ;
    PORT
      LAYER M4 ;
        RECT  0 12.528 0.084 12.552 ;
    END
  END dn2_o[21]
  PIN dn2_o[22]
    DIRECTION OUTPUT ;
    USE SIGNAL ;
    PORT
      LAYER M4 ;
        RECT  0 12.672 0.084 12.696 ;
    END
  END dn2_o[22]
  PIN dn2_o[23]
    DIRECTION OUTPUT ;
    USE SIGNAL ;
    PORT
      LAYER M4 ;
        RECT  0 12.864 0.084 12.888 ;
    END
  END dn2_o[23]
  PIN dn2_o[24]
    DIRECTION OUTPUT ;
    USE SIGNAL ;
    PORT
      LAYER M4 ;
        RECT  0 13.008 0.084 13.032 ;
    END
  END dn2_o[24]
  PIN dn2_o[25]
    DIRECTION OUTPUT ;
    USE SIGNAL ;
    PORT
      LAYER M4 ;
        RECT  0 13.2 0.084 13.224 ;
    END
  END dn2_o[25]
  PIN dn2_o[26]
    DIRECTION OUTPUT ;
    USE SIGNAL ;
    PORT
      LAYER M4 ;
        RECT  0 13.344 0.084 13.368 ;
    END
  END dn2_o[26]
  PIN dn2_o[27]
    DIRECTION OUTPUT ;
    USE SIGNAL ;
    PORT
      LAYER M4 ;
        RECT  0 13.536 0.084 13.56 ;
    END
  END dn2_o[27]
  PIN dn2_o[28]
    DIRECTION OUTPUT ;
    USE SIGNAL ;
    PORT
      LAYER M4 ;
        RECT  0 13.68 0.084 13.704 ;
    END
  END dn2_o[28]
  PIN dn2_o[29]
    DIRECTION OUTPUT ;
    USE SIGNAL ;
    PORT
      LAYER M4 ;
        RECT  0 13.824 0.084 13.848 ;
    END
  END dn2_o[29]
  PIN dn2_o[2]
    DIRECTION OUTPUT ;
    USE SIGNAL ;
    PORT
      LAYER M4 ;
        RECT  0 9.408 0.084 9.432 ;
    END
  END dn2_o[2]
  PIN dn2_o[30]
    DIRECTION OUTPUT ;
    USE SIGNAL ;
    PORT
      LAYER M4 ;
        RECT  0 14.016 0.084 14.04 ;
    END
  END dn2_o[30]
  PIN dn2_o[31]
    DIRECTION OUTPUT ;
    USE SIGNAL ;
    PORT
      LAYER M4 ;
        RECT  0 14.16 0.084 14.184 ;
    END
  END dn2_o[31]
  PIN dn2_o[32]
    DIRECTION OUTPUT ;
    USE SIGNAL ;
    PORT
      LAYER M4 ;
        RECT  0 14.352 0.084 14.376 ;
    END
  END dn2_o[32]
  PIN dn2_o[33]
    DIRECTION OUTPUT ;
    USE SIGNAL ;
    PORT
      LAYER M4 ;
        RECT  0 14.496 0.084 14.52 ;
    END
  END dn2_o[33]
  PIN dn2_o[34]
    DIRECTION OUTPUT ;
    USE SIGNAL ;
    PORT
      LAYER M4 ;
        RECT  0 14.688 0.084 14.712 ;
    END
  END dn2_o[34]
  PIN dn2_o[35]
    DIRECTION OUTPUT ;
    USE SIGNAL ;
    PORT
      LAYER M4 ;
        RECT  0 14.832 0.084 14.856 ;
    END
  END dn2_o[35]
  PIN dn2_o[36]
    DIRECTION OUTPUT ;
    USE SIGNAL ;
    PORT
      LAYER M4 ;
        RECT  0 14.976 0.084 15 ;
    END
  END dn2_o[36]
  PIN dn2_o[37]
    DIRECTION OUTPUT ;
    USE SIGNAL ;
    PORT
      LAYER M4 ;
        RECT  0 15.168 0.084 15.192 ;
    END
  END dn2_o[37]
  PIN dn2_o[38]
    DIRECTION OUTPUT ;
    USE SIGNAL ;
    PORT
      LAYER M4 ;
        RECT  0 15.312 0.084 15.336 ;
    END
  END dn2_o[38]
  PIN dn2_o[39]
    DIRECTION OUTPUT ;
    USE SIGNAL ;
    PORT
      LAYER M4 ;
        RECT  0 15.504 0.084 15.528 ;
    END
  END dn2_o[39]
  PIN dn2_o[3]
    DIRECTION OUTPUT ;
    USE SIGNAL ;
    PORT
      LAYER M4 ;
        RECT  0 9.552 0.084 9.576 ;
    END
  END dn2_o[3]
  PIN dn2_o[40]
    DIRECTION OUTPUT ;
    USE SIGNAL ;
    PORT
      LAYER M4 ;
        RECT  0 15.648 0.084 15.672 ;
    END
  END dn2_o[40]
  PIN dn2_o[41]
    DIRECTION OUTPUT ;
    USE SIGNAL ;
    PORT
      LAYER M4 ;
        RECT  0 15.84 0.084 15.864 ;
    END
  END dn2_o[41]
  PIN dn2_o[42]
    DIRECTION OUTPUT ;
    USE SIGNAL ;
    PORT
      LAYER M4 ;
        RECT  0 15.984 0.084 16.008 ;
    END
  END dn2_o[42]
  PIN dn2_o[43]
    DIRECTION OUTPUT ;
    USE SIGNAL ;
    PORT
      LAYER M4 ;
        RECT  0 16.128 0.084 16.152 ;
    END
  END dn2_o[43]
  PIN dn2_o[44]
    DIRECTION OUTPUT ;
    USE SIGNAL ;
    PORT
      LAYER M4 ;
        RECT  0 16.32 0.084 16.344 ;
    END
  END dn2_o[44]
  PIN dn2_o[45]
    DIRECTION OUTPUT ;
    USE SIGNAL ;
    PORT
      LAYER M4 ;
        RECT  0 16.464 0.084 16.488 ;
    END
  END dn2_o[45]
  PIN dn2_o[46]
    DIRECTION OUTPUT ;
    USE SIGNAL ;
    PORT
      LAYER M4 ;
        RECT  0 16.656 0.084 16.68 ;
    END
  END dn2_o[46]
  PIN dn2_o[47]
    DIRECTION OUTPUT ;
    USE SIGNAL ;
    PORT
      LAYER M4 ;
        RECT  0 16.8 0.084 16.824 ;
    END
  END dn2_o[47]
  PIN dn2_o[48]
    DIRECTION OUTPUT ;
    USE SIGNAL ;
    PORT
      LAYER M4 ;
        RECT  0 16.992 0.084 17.016 ;
    END
  END dn2_o[48]
  PIN dn2_o[49]
    DIRECTION OUTPUT ;
    USE SIGNAL ;
    PORT
      LAYER M4 ;
        RECT  0 17.136 0.084 17.16 ;
    END
  END dn2_o[49]
  PIN dn2_o[4]
    DIRECTION OUTPUT ;
    USE SIGNAL ;
    PORT
      LAYER M4 ;
        RECT  0 9.744 0.084 9.768 ;
    END
  END dn2_o[4]
  PIN dn2_o[50]
    DIRECTION OUTPUT ;
    USE SIGNAL ;
    PORT
      LAYER M4 ;
        RECT  0 17.28 0.084 17.304 ;
    END
  END dn2_o[50]
  PIN dn2_o[51]
    DIRECTION OUTPUT ;
    USE SIGNAL ;
    PORT
      LAYER M4 ;
        RECT  0 17.472 0.084 17.496 ;
    END
  END dn2_o[51]
  PIN dn2_o[52]
    DIRECTION OUTPUT ;
    USE SIGNAL ;
    PORT
      LAYER M4 ;
        RECT  0 17.616 0.084 17.64 ;
    END
  END dn2_o[52]
  PIN dn2_o[53]
    DIRECTION OUTPUT ;
    USE SIGNAL ;
    PORT
      LAYER M4 ;
        RECT  0 17.808 0.084 17.832 ;
    END
  END dn2_o[53]
  PIN dn2_o[54]
    DIRECTION OUTPUT ;
    USE SIGNAL ;
    PORT
      LAYER M4 ;
        RECT  0 17.952 0.084 17.976 ;
    END
  END dn2_o[54]
  PIN dn2_o[55]
    DIRECTION OUTPUT ;
    USE SIGNAL ;
    PORT
      LAYER M4 ;
        RECT  0 18.144 0.084 18.168 ;
    END
  END dn2_o[55]
  PIN dn2_o[56]
    DIRECTION OUTPUT ;
    USE SIGNAL ;
    PORT
      LAYER M4 ;
        RECT  0 18.288 0.084 18.312 ;
    END
  END dn2_o[56]
  PIN dn2_o[57]
    DIRECTION OUTPUT ;
    USE SIGNAL ;
    PORT
      LAYER M4 ;
        RECT  0 18.432 0.084 18.456 ;
    END
  END dn2_o[57]
  PIN dn2_o[58]
    DIRECTION OUTPUT ;
    USE SIGNAL ;
    PORT
      LAYER M4 ;
        RECT  0 18.624 0.084 18.648 ;
    END
  END dn2_o[58]
  PIN dn2_o[59]
    DIRECTION OUTPUT ;
    USE SIGNAL ;
    PORT
      LAYER M4 ;
        RECT  0 18.768 0.084 18.792 ;
    END
  END dn2_o[59]
  PIN dn2_o[5]
    DIRECTION OUTPUT ;
    USE SIGNAL ;
    PORT
      LAYER M4 ;
        RECT  0 9.888 0.084 9.912 ;
    END
  END dn2_o[5]
  PIN dn2_o[60]
    DIRECTION OUTPUT ;
    USE SIGNAL ;
    PORT
      LAYER M4 ;
        RECT  0 18.96 0.084 18.984 ;
    END
  END dn2_o[60]
  PIN dn2_o[61]
    DIRECTION OUTPUT ;
    USE SIGNAL ;
    PORT
      LAYER M4 ;
        RECT  0 19.104 0.084 19.128 ;
    END
  END dn2_o[61]
  PIN dn2_o[62]
    DIRECTION OUTPUT ;
    USE SIGNAL ;
    PORT
      LAYER M4 ;
        RECT  0 19.296 0.084 19.32 ;
    END
  END dn2_o[62]
  PIN dn2_o[63]
    DIRECTION OUTPUT ;
    USE SIGNAL ;
    PORT
      LAYER M4 ;
        RECT  0 19.44 0.084 19.464 ;
    END
  END dn2_o[63]
  PIN dn2_o[64]
    DIRECTION OUTPUT ;
    USE SIGNAL ;
    PORT
      LAYER M4 ;
        RECT  0 19.584 0.084 19.608 ;
    END
  END dn2_o[64]
  PIN dn2_o[65]
    DIRECTION OUTPUT ;
    USE SIGNAL ;
    PORT
      LAYER M4 ;
        RECT  0 19.776 0.084 19.8 ;
    END
  END dn2_o[65]
  PIN dn2_o[66]
    DIRECTION OUTPUT ;
    USE SIGNAL ;
    PORT
      LAYER M4 ;
        RECT  0 19.92 0.084 19.944 ;
    END
  END dn2_o[66]
  PIN dn2_o[67]
    DIRECTION OUTPUT ;
    USE SIGNAL ;
    PORT
      LAYER M4 ;
        RECT  0 20.112 0.084 20.136 ;
    END
  END dn2_o[67]
  PIN dn2_o[68]
    DIRECTION OUTPUT ;
    USE SIGNAL ;
    PORT
      LAYER M4 ;
        RECT  0 20.256 0.084 20.28 ;
    END
  END dn2_o[68]
  PIN dn2_o[69]
    DIRECTION OUTPUT ;
    USE SIGNAL ;
    PORT
      LAYER M4 ;
        RECT  0 20.448 0.084 20.472 ;
    END
  END dn2_o[69]
  PIN dn2_o[6]
    DIRECTION OUTPUT ;
    USE SIGNAL ;
    PORT
      LAYER M4 ;
        RECT  0 10.08 0.084 10.104 ;
    END
  END dn2_o[6]
  PIN dn2_o[70]
    DIRECTION OUTPUT ;
    USE SIGNAL ;
    PORT
      LAYER M4 ;
        RECT  0 20.592 0.084 20.616 ;
    END
  END dn2_o[70]
  PIN dn2_o[71]
    DIRECTION OUTPUT ;
    USE SIGNAL ;
    PORT
      LAYER M4 ;
        RECT  0 20.736 0.084 20.76 ;
    END
  END dn2_o[71]
  PIN dn2_o[72]
    DIRECTION OUTPUT ;
    USE SIGNAL ;
    PORT
      LAYER M4 ;
        RECT  0 20.928 0.084 20.952 ;
    END
  END dn2_o[72]
  PIN dn2_o[73]
    DIRECTION OUTPUT ;
    USE SIGNAL ;
    PORT
      LAYER M4 ;
        RECT  0 21.072 0.084 21.096 ;
    END
  END dn2_o[73]
  PIN dn2_o[74]
    DIRECTION OUTPUT ;
    USE SIGNAL ;
    PORT
      LAYER M4 ;
        RECT  0 21.264 0.084 21.288 ;
    END
  END dn2_o[74]
  PIN dn2_o[75]
    DIRECTION OUTPUT ;
    USE SIGNAL ;
    PORT
      LAYER M4 ;
        RECT  0 21.408 0.084 21.432 ;
    END
  END dn2_o[75]
  PIN dn2_o[76]
    DIRECTION OUTPUT ;
    USE SIGNAL ;
    PORT
      LAYER M4 ;
        RECT  0 21.6 0.084 21.624 ;
    END
  END dn2_o[76]
  PIN dn2_o[77]
    DIRECTION OUTPUT ;
    USE SIGNAL ;
    PORT
      LAYER M4 ;
        RECT  0 21.744 0.084 21.768 ;
    END
  END dn2_o[77]
  PIN dn2_o[78]
    DIRECTION OUTPUT ;
    USE SIGNAL ;
    PORT
      LAYER M4 ;
        RECT  0 21.936 0.084 21.96 ;
    END
  END dn2_o[78]
  PIN dn2_o[79]
    DIRECTION OUTPUT ;
    USE SIGNAL ;
    PORT
      LAYER M4 ;
        RECT  0 22.08 0.084 22.104 ;
    END
  END dn2_o[79]
  PIN dn2_o[7]
    DIRECTION OUTPUT ;
    USE SIGNAL ;
    PORT
      LAYER M4 ;
        RECT  0 10.224 0.084 10.248 ;
    END
  END dn2_o[7]
  PIN dn2_o[80]
    DIRECTION OUTPUT ;
    USE SIGNAL ;
    PORT
      LAYER M4 ;
        RECT  0 22.224 0.084 22.248 ;
    END
  END dn2_o[80]
  PIN dn2_o[81]
    DIRECTION OUTPUT ;
    USE SIGNAL ;
    PORT
      LAYER M4 ;
        RECT  0 22.416 0.084 22.44 ;
    END
  END dn2_o[81]
  PIN dn2_o[82]
    DIRECTION OUTPUT ;
    USE SIGNAL ;
    PORT
      LAYER M4 ;
        RECT  0 22.56 0.084 22.584 ;
    END
  END dn2_o[82]
  PIN dn2_o[83]
    DIRECTION OUTPUT ;
    USE SIGNAL ;
    PORT
      LAYER M4 ;
        RECT  0 22.752 0.084 22.776 ;
    END
  END dn2_o[83]
  PIN dn2_o[84]
    DIRECTION OUTPUT ;
    USE SIGNAL ;
    PORT
      LAYER M4 ;
        RECT  0 22.896 0.084 22.92 ;
    END
  END dn2_o[84]
  PIN dn2_o[85]
    DIRECTION OUTPUT ;
    USE SIGNAL ;
    PORT
      LAYER M4 ;
        RECT  0 23.088 0.084 23.112 ;
    END
  END dn2_o[85]
  PIN dn2_o[86]
    DIRECTION OUTPUT ;
    USE SIGNAL ;
    PORT
      LAYER M4 ;
        RECT  0 23.232 0.084 23.256 ;
    END
  END dn2_o[86]
  PIN dn2_o[87]
    DIRECTION OUTPUT ;
    USE SIGNAL ;
    PORT
      LAYER M4 ;
        RECT  0 23.376 0.084 23.4 ;
    END
  END dn2_o[87]
  PIN dn2_o[88]
    DIRECTION OUTPUT ;
    USE SIGNAL ;
    PORT
      LAYER M4 ;
        RECT  0 23.568 0.084 23.592 ;
    END
  END dn2_o[88]
  PIN dn2_o[89]
    DIRECTION OUTPUT ;
    USE SIGNAL ;
    PORT
      LAYER M4 ;
        RECT  0 23.712 0.084 23.736 ;
    END
  END dn2_o[89]
  PIN dn2_o[8]
    DIRECTION OUTPUT ;
    USE SIGNAL ;
    PORT
      LAYER M4 ;
        RECT  0 10.368 0.084 10.392 ;
    END
  END dn2_o[8]
  PIN dn2_o[90]
    DIRECTION OUTPUT ;
    USE SIGNAL ;
    PORT
      LAYER M4 ;
        RECT  0 23.904 0.084 23.928 ;
    END
  END dn2_o[90]
  PIN dn2_o[91]
    DIRECTION OUTPUT ;
    USE SIGNAL ;
    PORT
      LAYER M4 ;
        RECT  0 24.048 0.084 24.072 ;
    END
  END dn2_o[91]
  PIN dn2_o[92]
    DIRECTION OUTPUT ;
    USE SIGNAL ;
    PORT
      LAYER M4 ;
        RECT  0 24.24 0.084 24.264 ;
    END
  END dn2_o[92]
  PIN dn2_o[93]
    DIRECTION OUTPUT ;
    USE SIGNAL ;
    PORT
      LAYER M4 ;
        RECT  0 24.384 0.084 24.408 ;
    END
  END dn2_o[93]
  PIN dn2_o[94]
    DIRECTION OUTPUT ;
    USE SIGNAL ;
    PORT
      LAYER M4 ;
        RECT  0 24.528 0.084 24.552 ;
    END
  END dn2_o[94]
  PIN dn2_o[95]
    DIRECTION OUTPUT ;
    USE SIGNAL ;
    PORT
      LAYER M4 ;
        RECT  0 24.72 0.084 24.744 ;
    END
  END dn2_o[95]
  PIN dn2_o[96]
    DIRECTION OUTPUT ;
    USE SIGNAL ;
    PORT
      LAYER M4 ;
        RECT  0 24.864 0.084 24.888 ;
    END
  END dn2_o[96]
  PIN dn2_o[97]
    DIRECTION OUTPUT ;
    USE SIGNAL ;
    PORT
      LAYER M4 ;
        RECT  0 25.056 0.084 25.08 ;
    END
  END dn2_o[97]
  PIN dn2_o[98]
    DIRECTION OUTPUT ;
    USE SIGNAL ;
    PORT
      LAYER M4 ;
        RECT  0 25.2 0.084 25.224 ;
    END
  END dn2_o[98]
  PIN dn2_o[99]
    DIRECTION OUTPUT ;
    USE SIGNAL ;
    PORT
      LAYER M4 ;
        RECT  0 25.392 0.084 25.416 ;
    END
  END dn2_o[99]
  PIN dn2_o[9]
    DIRECTION OUTPUT ;
    USE SIGNAL ;
    PORT
      LAYER M4 ;
        RECT  0 10.56 0.084 10.584 ;
    END
  END dn2_o[9]
  PIN dn3_o[0]
    DIRECTION OUTPUT ;
    USE SIGNAL ;
    PORT
      LAYER M3 ;
        RECT  10.008 43.162 10.026 43.2 ;
    END
  END dn3_o[0]
  PIN dn3_o[100]
    DIRECTION OUTPUT ;
    USE SIGNAL ;
    PORT
      LAYER M3 ;
        RECT  28.98 43.162 28.998 43.2 ;
    END
  END dn3_o[100]
  PIN dn3_o[101]
    DIRECTION OUTPUT ;
    USE SIGNAL ;
    PORT
      LAYER M5 ;
        RECT  29.184 43.116 29.208 43.2 ;
    END
  END dn3_o[101]
  PIN dn3_o[102]
    DIRECTION OUTPUT ;
    USE SIGNAL ;
    PORT
      LAYER M3 ;
        RECT  29.376 43.162 29.394 43.2 ;
    END
  END dn3_o[102]
  PIN dn3_o[103]
    DIRECTION OUTPUT ;
    USE SIGNAL ;
    PORT
      LAYER M5 ;
        RECT  29.568 43.116 29.592 43.2 ;
    END
  END dn3_o[103]
  PIN dn3_o[104]
    DIRECTION OUTPUT ;
    USE SIGNAL ;
    PORT
      LAYER M3 ;
        RECT  29.736 43.162 29.754 43.2 ;
    END
  END dn3_o[104]
  PIN dn3_o[105]
    DIRECTION OUTPUT ;
    USE SIGNAL ;
    PORT
      LAYER M5 ;
        RECT  29.952 43.116 29.976 43.2 ;
    END
  END dn3_o[105]
  PIN dn3_o[106]
    DIRECTION OUTPUT ;
    USE SIGNAL ;
    PORT
      LAYER M3 ;
        RECT  30.132 43.162 30.15 43.2 ;
    END
  END dn3_o[106]
  PIN dn3_o[107]
    DIRECTION OUTPUT ;
    USE SIGNAL ;
    PORT
      LAYER M5 ;
        RECT  30.336 43.116 30.36 43.2 ;
    END
  END dn3_o[107]
  PIN dn3_o[108]
    DIRECTION OUTPUT ;
    USE SIGNAL ;
    PORT
      LAYER M3 ;
        RECT  30.492 43.162 30.51 43.2 ;
    END
  END dn3_o[108]
  PIN dn3_o[109]
    DIRECTION OUTPUT ;
    USE SIGNAL ;
    PORT
      LAYER M5 ;
        RECT  30.672 43.116 30.696 43.2 ;
    END
  END dn3_o[109]
  PIN dn3_o[10]
    DIRECTION OUTPUT ;
    USE SIGNAL ;
    PORT
      LAYER M3 ;
        RECT  11.916 43.162 11.934 43.2 ;
    END
  END dn3_o[10]
  PIN dn3_o[110]
    DIRECTION OUTPUT ;
    USE SIGNAL ;
    PORT
      LAYER M3 ;
        RECT  30.888 43.162 30.906 43.2 ;
    END
  END dn3_o[110]
  PIN dn3_o[111]
    DIRECTION OUTPUT ;
    USE SIGNAL ;
    PORT
      LAYER M5 ;
        RECT  31.056 43.116 31.08 43.2 ;
    END
  END dn3_o[111]
  PIN dn3_o[112]
    DIRECTION OUTPUT ;
    USE SIGNAL ;
    PORT
      LAYER M3 ;
        RECT  31.248 43.162 31.266 43.2 ;
    END
  END dn3_o[112]
  PIN dn3_o[113]
    DIRECTION OUTPUT ;
    USE SIGNAL ;
    PORT
      LAYER M5 ;
        RECT  31.44 43.116 31.464 43.2 ;
    END
  END dn3_o[113]
  PIN dn3_o[114]
    DIRECTION OUTPUT ;
    USE SIGNAL ;
    PORT
      LAYER M3 ;
        RECT  31.644 43.162 31.662 43.2 ;
    END
  END dn3_o[114]
  PIN dn3_o[115]
    DIRECTION OUTPUT ;
    USE SIGNAL ;
    PORT
      LAYER M5 ;
        RECT  31.824 43.116 31.848 43.2 ;
    END
  END dn3_o[115]
  PIN dn3_o[116]
    DIRECTION OUTPUT ;
    USE SIGNAL ;
    PORT
      LAYER M3 ;
        RECT  32.04 43.162 32.058 43.2 ;
    END
  END dn3_o[116]
  PIN dn3_o[117]
    DIRECTION OUTPUT ;
    USE SIGNAL ;
    PORT
      LAYER M5 ;
        RECT  32.208 43.116 32.232 43.2 ;
    END
  END dn3_o[117]
  PIN dn3_o[118]
    DIRECTION OUTPUT ;
    USE SIGNAL ;
    PORT
      LAYER M3 ;
        RECT  32.4 43.162 32.418 43.2 ;
    END
  END dn3_o[118]
  PIN dn3_o[119]
    DIRECTION OUTPUT ;
    USE SIGNAL ;
    PORT
      LAYER M5 ;
        RECT  32.592 43.116 32.616 43.2 ;
    END
  END dn3_o[119]
  PIN dn3_o[11]
    DIRECTION OUTPUT ;
    USE SIGNAL ;
    PORT
      LAYER M5 ;
        RECT  12.096 43.116 12.12 43.2 ;
    END
  END dn3_o[11]
  PIN dn3_o[120]
    DIRECTION OUTPUT ;
    USE SIGNAL ;
    PORT
      LAYER M3 ;
        RECT  32.796 43.162 32.814 43.2 ;
    END
  END dn3_o[120]
  PIN dn3_o[121]
    DIRECTION OUTPUT ;
    USE SIGNAL ;
    PORT
      LAYER M5 ;
        RECT  32.976 43.116 33 43.2 ;
    END
  END dn3_o[121]
  PIN dn3_o[122]
    DIRECTION OUTPUT ;
    USE SIGNAL ;
    PORT
      LAYER M3 ;
        RECT  33.156 43.162 33.174 43.2 ;
    END
  END dn3_o[122]
  PIN dn3_o[123]
    DIRECTION OUTPUT ;
    USE SIGNAL ;
    PORT
      LAYER M5 ;
        RECT  33.36 43.116 33.384 43.2 ;
    END
  END dn3_o[123]
  PIN dn3_o[124]
    DIRECTION OUTPUT ;
    USE SIGNAL ;
    PORT
      LAYER M3 ;
        RECT  33.552 43.162 33.57 43.2 ;
    END
  END dn3_o[124]
  PIN dn3_o[125]
    DIRECTION OUTPUT ;
    USE SIGNAL ;
    PORT
      LAYER M5 ;
        RECT  33.744 43.116 33.768 43.2 ;
    END
  END dn3_o[125]
  PIN dn3_o[126]
    DIRECTION OUTPUT ;
    USE SIGNAL ;
    PORT
      LAYER M3 ;
        RECT  33.912 43.162 33.93 43.2 ;
    END
  END dn3_o[126]
  PIN dn3_o[127]
    DIRECTION OUTPUT ;
    USE SIGNAL ;
    PORT
      LAYER M5 ;
        RECT  34.128 43.116 34.152 43.2 ;
    END
  END dn3_o[127]
  PIN dn3_o[128]
    DIRECTION OUTPUT ;
    USE SIGNAL ;
    PORT
      LAYER M3 ;
        RECT  34.308 43.162 34.326 43.2 ;
    END
  END dn3_o[128]
  PIN dn3_o[129]
    DIRECTION OUTPUT ;
    USE SIGNAL ;
    PORT
      LAYER M5 ;
        RECT  34.464 43.116 34.488 43.2 ;
    END
  END dn3_o[129]
  PIN dn3_o[12]
    DIRECTION OUTPUT ;
    USE SIGNAL ;
    PORT
      LAYER M3 ;
        RECT  12.312 43.162 12.33 43.2 ;
    END
  END dn3_o[12]
  PIN dn3_o[130]
    DIRECTION OUTPUT ;
    USE SIGNAL ;
    PORT
      LAYER M3 ;
        RECT  34.668 43.162 34.686 43.2 ;
    END
  END dn3_o[130]
  PIN dn3_o[131]
    DIRECTION OUTPUT ;
    USE SIGNAL ;
    PORT
      LAYER M5 ;
        RECT  34.848 43.116 34.872 43.2 ;
    END
  END dn3_o[131]
  PIN dn3_o[132]
    DIRECTION OUTPUT ;
    USE SIGNAL ;
    PORT
      LAYER M3 ;
        RECT  35.064 43.162 35.082 43.2 ;
    END
  END dn3_o[132]
  PIN dn3_o[133]
    DIRECTION OUTPUT ;
    USE SIGNAL ;
    PORT
      LAYER M5 ;
        RECT  35.232 43.116 35.256 43.2 ;
    END
  END dn3_o[133]
  PIN dn3_o[134]
    DIRECTION OUTPUT ;
    USE SIGNAL ;
    PORT
      LAYER M3 ;
        RECT  35.424 43.162 35.442 43.2 ;
    END
  END dn3_o[134]
  PIN dn3_o[135]
    DIRECTION OUTPUT ;
    USE SIGNAL ;
    PORT
      LAYER M5 ;
        RECT  35.616 43.116 35.64 43.2 ;
    END
  END dn3_o[135]
  PIN dn3_o[136]
    DIRECTION OUTPUT ;
    USE SIGNAL ;
    PORT
      LAYER M3 ;
        RECT  35.82 43.162 35.838 43.2 ;
    END
  END dn3_o[136]
  PIN dn3_o[137]
    DIRECTION OUTPUT ;
    USE SIGNAL ;
    PORT
      LAYER M5 ;
        RECT  36 43.116 36.024 43.2 ;
    END
  END dn3_o[137]
  PIN dn3_o[138]
    DIRECTION OUTPUT ;
    USE SIGNAL ;
    PORT
      LAYER M3 ;
        RECT  36.18 43.162 36.198 43.2 ;
    END
  END dn3_o[138]
  PIN dn3_o[139]
    DIRECTION OUTPUT ;
    USE SIGNAL ;
    PORT
      LAYER M5 ;
        RECT  36.384 43.116 36.408 43.2 ;
    END
  END dn3_o[139]
  PIN dn3_o[13]
    DIRECTION OUTPUT ;
    USE SIGNAL ;
    PORT
      LAYER M5 ;
        RECT  12.48 43.116 12.504 43.2 ;
    END
  END dn3_o[13]
  PIN dn3_o[140]
    DIRECTION OUTPUT ;
    USE SIGNAL ;
    PORT
      LAYER M3 ;
        RECT  36.576 43.162 36.594 43.2 ;
    END
  END dn3_o[140]
  PIN dn3_o[141]
    DIRECTION OUTPUT ;
    USE SIGNAL ;
    PORT
      LAYER M5 ;
        RECT  36.768 43.116 36.792 43.2 ;
    END
  END dn3_o[141]
  PIN dn3_o[142]
    DIRECTION OUTPUT ;
    USE SIGNAL ;
    PORT
      LAYER M3 ;
        RECT  36.936 43.162 36.954 43.2 ;
    END
  END dn3_o[142]
  PIN dn3_o[143]
    DIRECTION OUTPUT ;
    USE SIGNAL ;
    PORT
      LAYER M5 ;
        RECT  37.152 43.116 37.176 43.2 ;
    END
  END dn3_o[143]
  PIN dn3_o[144]
    DIRECTION OUTPUT ;
    USE SIGNAL ;
    PORT
      LAYER M3 ;
        RECT  37.332 43.162 37.35 43.2 ;
    END
  END dn3_o[144]
  PIN dn3_o[145]
    DIRECTION OUTPUT ;
    USE SIGNAL ;
    PORT
      LAYER M5 ;
        RECT  37.536 43.116 37.56 43.2 ;
    END
  END dn3_o[145]
  PIN dn3_o[146]
    DIRECTION OUTPUT ;
    USE SIGNAL ;
    PORT
      LAYER M3 ;
        RECT  37.728 43.162 37.746 43.2 ;
    END
  END dn3_o[146]
  PIN dn3_o[147]
    DIRECTION OUTPUT ;
    USE SIGNAL ;
    PORT
      LAYER M5 ;
        RECT  37.92 43.116 37.944 43.2 ;
    END
  END dn3_o[147]
  PIN dn3_o[148]
    DIRECTION OUTPUT ;
    USE SIGNAL ;
    PORT
      LAYER M3 ;
        RECT  38.088 43.162 38.106 43.2 ;
    END
  END dn3_o[148]
  PIN dn3_o[149]
    DIRECTION OUTPUT ;
    USE SIGNAL ;
    PORT
      LAYER M5 ;
        RECT  38.256 43.116 38.28 43.2 ;
    END
  END dn3_o[149]
  PIN dn3_o[14]
    DIRECTION OUTPUT ;
    USE SIGNAL ;
    PORT
      LAYER M3 ;
        RECT  12.672 43.162 12.69 43.2 ;
    END
  END dn3_o[14]
  PIN dn3_o[150]
    DIRECTION OUTPUT ;
    USE SIGNAL ;
    PORT
      LAYER M3 ;
        RECT  38.484 43.162 38.502 43.2 ;
    END
  END dn3_o[150]
  PIN dn3_o[151]
    DIRECTION OUTPUT ;
    USE SIGNAL ;
    PORT
      LAYER M5 ;
        RECT  38.64 43.116 38.664 43.2 ;
    END
  END dn3_o[151]
  PIN dn3_o[152]
    DIRECTION OUTPUT ;
    USE SIGNAL ;
    PORT
      LAYER M3 ;
        RECT  38.844 43.162 38.862 43.2 ;
    END
  END dn3_o[152]
  PIN dn3_o[153]
    DIRECTION OUTPUT ;
    USE SIGNAL ;
    PORT
      LAYER M5 ;
        RECT  39.024 43.116 39.048 43.2 ;
    END
  END dn3_o[153]
  PIN dn3_o[154]
    DIRECTION OUTPUT ;
    USE SIGNAL ;
    PORT
      LAYER M3 ;
        RECT  39.24 43.162 39.258 43.2 ;
    END
  END dn3_o[154]
  PIN dn3_o[155]
    DIRECTION OUTPUT ;
    USE SIGNAL ;
    PORT
      LAYER M5 ;
        RECT  39.408 43.116 39.432 43.2 ;
    END
  END dn3_o[155]
  PIN dn3_o[156]
    DIRECTION OUTPUT ;
    USE SIGNAL ;
    PORT
      LAYER M3 ;
        RECT  39.6 43.162 39.618 43.2 ;
    END
  END dn3_o[156]
  PIN dn3_o[157]
    DIRECTION OUTPUT ;
    USE SIGNAL ;
    PORT
      LAYER M5 ;
        RECT  39.792 43.116 39.816 43.2 ;
    END
  END dn3_o[157]
  PIN dn3_o[158]
    DIRECTION OUTPUT ;
    USE SIGNAL ;
    PORT
      LAYER M3 ;
        RECT  39.996 43.162 40.014 43.2 ;
    END
  END dn3_o[158]
  PIN dn3_o[159]
    DIRECTION OUTPUT ;
    USE SIGNAL ;
    PORT
      LAYER M5 ;
        RECT  40.176 43.116 40.2 43.2 ;
    END
  END dn3_o[159]
  PIN dn3_o[15]
    DIRECTION OUTPUT ;
    USE SIGNAL ;
    PORT
      LAYER M5 ;
        RECT  12.864 43.116 12.888 43.2 ;
    END
  END dn3_o[15]
  PIN dn3_o[160]
    DIRECTION OUTPUT ;
    USE SIGNAL ;
    PORT
      LAYER M3 ;
        RECT  40.356 43.162 40.374 43.2 ;
    END
  END dn3_o[160]
  PIN dn3_o[161]
    DIRECTION OUTPUT ;
    USE SIGNAL ;
    PORT
      LAYER M5 ;
        RECT  40.56 43.116 40.584 43.2 ;
    END
  END dn3_o[161]
  PIN dn3_o[162]
    DIRECTION OUTPUT ;
    USE SIGNAL ;
    PORT
      LAYER M3 ;
        RECT  40.752 43.162 40.77 43.2 ;
    END
  END dn3_o[162]
  PIN dn3_o[163]
    DIRECTION OUTPUT ;
    USE SIGNAL ;
    PORT
      LAYER M5 ;
        RECT  40.944 43.116 40.968 43.2 ;
    END
  END dn3_o[163]
  PIN dn3_o[16]
    DIRECTION OUTPUT ;
    USE SIGNAL ;
    PORT
      LAYER M3 ;
        RECT  13.068 43.162 13.086 43.2 ;
    END
  END dn3_o[16]
  PIN dn3_o[17]
    DIRECTION OUTPUT ;
    USE SIGNAL ;
    PORT
      LAYER M5 ;
        RECT  13.248 43.116 13.272 43.2 ;
    END
  END dn3_o[17]
  PIN dn3_o[18]
    DIRECTION OUTPUT ;
    USE SIGNAL ;
    PORT
      LAYER M3 ;
        RECT  13.428 43.162 13.446 43.2 ;
    END
  END dn3_o[18]
  PIN dn3_o[19]
    DIRECTION OUTPUT ;
    USE SIGNAL ;
    PORT
      LAYER M5 ;
        RECT  13.632 43.116 13.656 43.2 ;
    END
  END dn3_o[19]
  PIN dn3_o[1]
    DIRECTION OUTPUT ;
    USE SIGNAL ;
    PORT
      LAYER M5 ;
        RECT  10.224 43.116 10.248 43.2 ;
    END
  END dn3_o[1]
  PIN dn3_o[20]
    DIRECTION OUTPUT ;
    USE SIGNAL ;
    PORT
      LAYER M3 ;
        RECT  13.824 43.162 13.842 43.2 ;
    END
  END dn3_o[20]
  PIN dn3_o[21]
    DIRECTION OUTPUT ;
    USE SIGNAL ;
    PORT
      LAYER M5 ;
        RECT  14.016 43.116 14.04 43.2 ;
    END
  END dn3_o[21]
  PIN dn3_o[22]
    DIRECTION OUTPUT ;
    USE SIGNAL ;
    PORT
      LAYER M3 ;
        RECT  14.184 43.162 14.202 43.2 ;
    END
  END dn3_o[22]
  PIN dn3_o[23]
    DIRECTION OUTPUT ;
    USE SIGNAL ;
    PORT
      LAYER M5 ;
        RECT  14.4 43.116 14.424 43.2 ;
    END
  END dn3_o[23]
  PIN dn3_o[24]
    DIRECTION OUTPUT ;
    USE SIGNAL ;
    PORT
      LAYER M3 ;
        RECT  14.58 43.162 14.598 43.2 ;
    END
  END dn3_o[24]
  PIN dn3_o[25]
    DIRECTION OUTPUT ;
    USE SIGNAL ;
    PORT
      LAYER M5 ;
        RECT  14.784 43.116 14.808 43.2 ;
    END
  END dn3_o[25]
  PIN dn3_o[26]
    DIRECTION OUTPUT ;
    USE SIGNAL ;
    PORT
      LAYER M3 ;
        RECT  14.94 43.162 14.958 43.2 ;
    END
  END dn3_o[26]
  PIN dn3_o[27]
    DIRECTION OUTPUT ;
    USE SIGNAL ;
    PORT
      LAYER M5 ;
        RECT  15.12 43.116 15.144 43.2 ;
    END
  END dn3_o[27]
  PIN dn3_o[28]
    DIRECTION OUTPUT ;
    USE SIGNAL ;
    PORT
      LAYER M3 ;
        RECT  15.336 43.162 15.354 43.2 ;
    END
  END dn3_o[28]
  PIN dn3_o[29]
    DIRECTION OUTPUT ;
    USE SIGNAL ;
    PORT
      LAYER M5 ;
        RECT  15.504 43.116 15.528 43.2 ;
    END
  END dn3_o[29]
  PIN dn3_o[2]
    DIRECTION OUTPUT ;
    USE SIGNAL ;
    PORT
      LAYER M3 ;
        RECT  10.404 43.162 10.422 43.2 ;
    END
  END dn3_o[2]
  PIN dn3_o[30]
    DIRECTION OUTPUT ;
    USE SIGNAL ;
    PORT
      LAYER M3 ;
        RECT  15.696 43.162 15.714 43.2 ;
    END
  END dn3_o[30]
  PIN dn3_o[31]
    DIRECTION OUTPUT ;
    USE SIGNAL ;
    PORT
      LAYER M5 ;
        RECT  15.888 43.116 15.912 43.2 ;
    END
  END dn3_o[31]
  PIN dn3_o[32]
    DIRECTION OUTPUT ;
    USE SIGNAL ;
    PORT
      LAYER M3 ;
        RECT  16.092 43.162 16.11 43.2 ;
    END
  END dn3_o[32]
  PIN dn3_o[33]
    DIRECTION OUTPUT ;
    USE SIGNAL ;
    PORT
      LAYER M5 ;
        RECT  16.272 43.116 16.296 43.2 ;
    END
  END dn3_o[33]
  PIN dn3_o[34]
    DIRECTION OUTPUT ;
    USE SIGNAL ;
    PORT
      LAYER M3 ;
        RECT  16.488 43.162 16.506 43.2 ;
    END
  END dn3_o[34]
  PIN dn3_o[35]
    DIRECTION OUTPUT ;
    USE SIGNAL ;
    PORT
      LAYER M5 ;
        RECT  16.656 43.116 16.68 43.2 ;
    END
  END dn3_o[35]
  PIN dn3_o[36]
    DIRECTION OUTPUT ;
    USE SIGNAL ;
    PORT
      LAYER M3 ;
        RECT  16.848 43.162 16.866 43.2 ;
    END
  END dn3_o[36]
  PIN dn3_o[37]
    DIRECTION OUTPUT ;
    USE SIGNAL ;
    PORT
      LAYER M5 ;
        RECT  17.04 43.116 17.064 43.2 ;
    END
  END dn3_o[37]
  PIN dn3_o[38]
    DIRECTION OUTPUT ;
    USE SIGNAL ;
    PORT
      LAYER M3 ;
        RECT  17.244 43.162 17.262 43.2 ;
    END
  END dn3_o[38]
  PIN dn3_o[39]
    DIRECTION OUTPUT ;
    USE SIGNAL ;
    PORT
      LAYER M5 ;
        RECT  17.424 43.116 17.448 43.2 ;
    END
  END dn3_o[39]
  PIN dn3_o[3]
    DIRECTION OUTPUT ;
    USE SIGNAL ;
    PORT
      LAYER M5 ;
        RECT  10.608 43.116 10.632 43.2 ;
    END
  END dn3_o[3]
  PIN dn3_o[40]
    DIRECTION OUTPUT ;
    USE SIGNAL ;
    PORT
      LAYER M3 ;
        RECT  17.604 43.162 17.622 43.2 ;
    END
  END dn3_o[40]
  PIN dn3_o[41]
    DIRECTION OUTPUT ;
    USE SIGNAL ;
    PORT
      LAYER M5 ;
        RECT  17.808 43.116 17.832 43.2 ;
    END
  END dn3_o[41]
  PIN dn3_o[42]
    DIRECTION OUTPUT ;
    USE SIGNAL ;
    PORT
      LAYER M3 ;
        RECT  18 43.162 18.018 43.2 ;
    END
  END dn3_o[42]
  PIN dn3_o[43]
    DIRECTION OUTPUT ;
    USE SIGNAL ;
    PORT
      LAYER M5 ;
        RECT  18.192 43.116 18.216 43.2 ;
    END
  END dn3_o[43]
  PIN dn3_o[44]
    DIRECTION OUTPUT ;
    USE SIGNAL ;
    PORT
      LAYER M3 ;
        RECT  18.36 43.162 18.378 43.2 ;
    END
  END dn3_o[44]
  PIN dn3_o[45]
    DIRECTION OUTPUT ;
    USE SIGNAL ;
    PORT
      LAYER M5 ;
        RECT  18.576 43.116 18.6 43.2 ;
    END
  END dn3_o[45]
  PIN dn3_o[46]
    DIRECTION OUTPUT ;
    USE SIGNAL ;
    PORT
      LAYER M3 ;
        RECT  18.756 43.162 18.774 43.2 ;
    END
  END dn3_o[46]
  PIN dn3_o[47]
    DIRECTION OUTPUT ;
    USE SIGNAL ;
    PORT
      LAYER M5 ;
        RECT  18.912 43.116 18.936 43.2 ;
    END
  END dn3_o[47]
  PIN dn3_o[48]
    DIRECTION OUTPUT ;
    USE SIGNAL ;
    PORT
      LAYER M3 ;
        RECT  19.116 43.162 19.134 43.2 ;
    END
  END dn3_o[48]
  PIN dn3_o[49]
    DIRECTION OUTPUT ;
    USE SIGNAL ;
    PORT
      LAYER M5 ;
        RECT  19.296 43.116 19.32 43.2 ;
    END
  END dn3_o[49]
  PIN dn3_o[4]
    DIRECTION OUTPUT ;
    USE SIGNAL ;
    PORT
      LAYER M3 ;
        RECT  10.764 43.162 10.782 43.2 ;
    END
  END dn3_o[4]
  PIN dn3_o[50]
    DIRECTION OUTPUT ;
    USE SIGNAL ;
    PORT
      LAYER M3 ;
        RECT  19.512 43.162 19.53 43.2 ;
    END
  END dn3_o[50]
  PIN dn3_o[51]
    DIRECTION OUTPUT ;
    USE SIGNAL ;
    PORT
      LAYER M5 ;
        RECT  19.68 43.116 19.704 43.2 ;
    END
  END dn3_o[51]
  PIN dn3_o[52]
    DIRECTION OUTPUT ;
    USE SIGNAL ;
    PORT
      LAYER M3 ;
        RECT  19.872 43.162 19.89 43.2 ;
    END
  END dn3_o[52]
  PIN dn3_o[53]
    DIRECTION OUTPUT ;
    USE SIGNAL ;
    PORT
      LAYER M5 ;
        RECT  20.064 43.116 20.088 43.2 ;
    END
  END dn3_o[53]
  PIN dn3_o[54]
    DIRECTION OUTPUT ;
    USE SIGNAL ;
    PORT
      LAYER M3 ;
        RECT  20.268 43.162 20.286 43.2 ;
    END
  END dn3_o[54]
  PIN dn3_o[55]
    DIRECTION OUTPUT ;
    USE SIGNAL ;
    PORT
      LAYER M5 ;
        RECT  20.448 43.116 20.472 43.2 ;
    END
  END dn3_o[55]
  PIN dn3_o[56]
    DIRECTION OUTPUT ;
    USE SIGNAL ;
    PORT
      LAYER M3 ;
        RECT  20.628 43.162 20.646 43.2 ;
    END
  END dn3_o[56]
  PIN dn3_o[57]
    DIRECTION OUTPUT ;
    USE SIGNAL ;
    PORT
      LAYER M5 ;
        RECT  20.832 43.116 20.856 43.2 ;
    END
  END dn3_o[57]
  PIN dn3_o[58]
    DIRECTION OUTPUT ;
    USE SIGNAL ;
    PORT
      LAYER M3 ;
        RECT  21.024 43.162 21.042 43.2 ;
    END
  END dn3_o[58]
  PIN dn3_o[59]
    DIRECTION OUTPUT ;
    USE SIGNAL ;
    PORT
      LAYER M5 ;
        RECT  21.216 43.116 21.24 43.2 ;
    END
  END dn3_o[59]
  PIN dn3_o[5]
    DIRECTION OUTPUT ;
    USE SIGNAL ;
    PORT
      LAYER M5 ;
        RECT  10.944 43.116 10.968 43.2 ;
    END
  END dn3_o[5]
  PIN dn3_o[60]
    DIRECTION OUTPUT ;
    USE SIGNAL ;
    PORT
      LAYER M3 ;
        RECT  21.384 43.162 21.402 43.2 ;
    END
  END dn3_o[60]
  PIN dn3_o[61]
    DIRECTION OUTPUT ;
    USE SIGNAL ;
    PORT
      LAYER M5 ;
        RECT  21.6 43.116 21.624 43.2 ;
    END
  END dn3_o[61]
  PIN dn3_o[62]
    DIRECTION OUTPUT ;
    USE SIGNAL ;
    PORT
      LAYER M3 ;
        RECT  21.78 43.162 21.798 43.2 ;
    END
  END dn3_o[62]
  PIN dn3_o[63]
    DIRECTION OUTPUT ;
    USE SIGNAL ;
    PORT
      LAYER M5 ;
        RECT  21.984 43.116 22.008 43.2 ;
    END
  END dn3_o[63]
  PIN dn3_o[64]
    DIRECTION OUTPUT ;
    USE SIGNAL ;
    PORT
      LAYER M3 ;
        RECT  22.176 43.162 22.194 43.2 ;
    END
  END dn3_o[64]
  PIN dn3_o[65]
    DIRECTION OUTPUT ;
    USE SIGNAL ;
    PORT
      LAYER M5 ;
        RECT  22.368 43.116 22.392 43.2 ;
    END
  END dn3_o[65]
  PIN dn3_o[66]
    DIRECTION OUTPUT ;
    USE SIGNAL ;
    PORT
      LAYER M3 ;
        RECT  22.536 43.162 22.554 43.2 ;
    END
  END dn3_o[66]
  PIN dn3_o[67]
    DIRECTION OUTPUT ;
    USE SIGNAL ;
    PORT
      LAYER M5 ;
        RECT  22.704 43.116 22.728 43.2 ;
    END
  END dn3_o[67]
  PIN dn3_o[68]
    DIRECTION OUTPUT ;
    USE SIGNAL ;
    PORT
      LAYER M3 ;
        RECT  22.932 43.162 22.95 43.2 ;
    END
  END dn3_o[68]
  PIN dn3_o[69]
    DIRECTION OUTPUT ;
    USE SIGNAL ;
    PORT
      LAYER M5 ;
        RECT  23.088 43.116 23.112 43.2 ;
    END
  END dn3_o[69]
  PIN dn3_o[6]
    DIRECTION OUTPUT ;
    USE SIGNAL ;
    PORT
      LAYER M3 ;
        RECT  11.16 43.162 11.178 43.2 ;
    END
  END dn3_o[6]
  PIN dn3_o[70]
    DIRECTION OUTPUT ;
    USE SIGNAL ;
    PORT
      LAYER M3 ;
        RECT  23.292 43.162 23.31 43.2 ;
    END
  END dn3_o[70]
  PIN dn3_o[71]
    DIRECTION OUTPUT ;
    USE SIGNAL ;
    PORT
      LAYER M5 ;
        RECT  23.472 43.116 23.496 43.2 ;
    END
  END dn3_o[71]
  PIN dn3_o[72]
    DIRECTION OUTPUT ;
    USE SIGNAL ;
    PORT
      LAYER M3 ;
        RECT  23.688 43.162 23.706 43.2 ;
    END
  END dn3_o[72]
  PIN dn3_o[73]
    DIRECTION OUTPUT ;
    USE SIGNAL ;
    PORT
      LAYER M5 ;
        RECT  23.856 43.116 23.88 43.2 ;
    END
  END dn3_o[73]
  PIN dn3_o[74]
    DIRECTION OUTPUT ;
    USE SIGNAL ;
    PORT
      LAYER M3 ;
        RECT  24.048 43.162 24.066 43.2 ;
    END
  END dn3_o[74]
  PIN dn3_o[75]
    DIRECTION OUTPUT ;
    USE SIGNAL ;
    PORT
      LAYER M5 ;
        RECT  24.24 43.116 24.264 43.2 ;
    END
  END dn3_o[75]
  PIN dn3_o[76]
    DIRECTION OUTPUT ;
    USE SIGNAL ;
    PORT
      LAYER M3 ;
        RECT  24.444 43.162 24.462 43.2 ;
    END
  END dn3_o[76]
  PIN dn3_o[77]
    DIRECTION OUTPUT ;
    USE SIGNAL ;
    PORT
      LAYER M5 ;
        RECT  24.624 43.116 24.648 43.2 ;
    END
  END dn3_o[77]
  PIN dn3_o[78]
    DIRECTION OUTPUT ;
    USE SIGNAL ;
    PORT
      LAYER M3 ;
        RECT  24.804 43.162 24.822 43.2 ;
    END
  END dn3_o[78]
  PIN dn3_o[79]
    DIRECTION OUTPUT ;
    USE SIGNAL ;
    PORT
      LAYER M5 ;
        RECT  25.008 43.116 25.032 43.2 ;
    END
  END dn3_o[79]
  PIN dn3_o[7]
    DIRECTION OUTPUT ;
    USE SIGNAL ;
    PORT
      LAYER M5 ;
        RECT  11.328 43.116 11.352 43.2 ;
    END
  END dn3_o[7]
  PIN dn3_o[80]
    DIRECTION OUTPUT ;
    USE SIGNAL ;
    PORT
      LAYER M3 ;
        RECT  25.2 43.162 25.218 43.2 ;
    END
  END dn3_o[80]
  PIN dn3_o[81]
    DIRECTION OUTPUT ;
    USE SIGNAL ;
    PORT
      LAYER M5 ;
        RECT  25.392 43.116 25.416 43.2 ;
    END
  END dn3_o[81]
  PIN dn3_o[82]
    DIRECTION OUTPUT ;
    USE SIGNAL ;
    PORT
      LAYER M3 ;
        RECT  25.56 43.162 25.578 43.2 ;
    END
  END dn3_o[82]
  PIN dn3_o[83]
    DIRECTION OUTPUT ;
    USE SIGNAL ;
    PORT
      LAYER M5 ;
        RECT  25.776 43.116 25.8 43.2 ;
    END
  END dn3_o[83]
  PIN dn3_o[84]
    DIRECTION OUTPUT ;
    USE SIGNAL ;
    PORT
      LAYER M3 ;
        RECT  25.956 43.162 25.974 43.2 ;
    END
  END dn3_o[84]
  PIN dn3_o[85]
    DIRECTION OUTPUT ;
    USE SIGNAL ;
    PORT
      LAYER M5 ;
        RECT  26.16 43.116 26.184 43.2 ;
    END
  END dn3_o[85]
  PIN dn3_o[86]
    DIRECTION OUTPUT ;
    USE SIGNAL ;
    PORT
      LAYER M3 ;
        RECT  26.316 43.162 26.334 43.2 ;
    END
  END dn3_o[86]
  PIN dn3_o[87]
    DIRECTION OUTPUT ;
    USE SIGNAL ;
    PORT
      LAYER M5 ;
        RECT  26.496 43.116 26.52 43.2 ;
    END
  END dn3_o[87]
  PIN dn3_o[88]
    DIRECTION OUTPUT ;
    USE SIGNAL ;
    PORT
      LAYER M3 ;
        RECT  26.712 43.162 26.73 43.2 ;
    END
  END dn3_o[88]
  PIN dn3_o[89]
    DIRECTION OUTPUT ;
    USE SIGNAL ;
    PORT
      LAYER M5 ;
        RECT  26.88 43.116 26.904 43.2 ;
    END
  END dn3_o[89]
  PIN dn3_o[8]
    DIRECTION OUTPUT ;
    USE SIGNAL ;
    PORT
      LAYER M3 ;
        RECT  11.556 43.162 11.574 43.2 ;
    END
  END dn3_o[8]
  PIN dn3_o[90]
    DIRECTION OUTPUT ;
    USE SIGNAL ;
    PORT
      LAYER M3 ;
        RECT  27.108 43.162 27.126 43.2 ;
    END
  END dn3_o[90]
  PIN dn3_o[91]
    DIRECTION OUTPUT ;
    USE SIGNAL ;
    PORT
      LAYER M5 ;
        RECT  27.264 43.116 27.288 43.2 ;
    END
  END dn3_o[91]
  PIN dn3_o[92]
    DIRECTION OUTPUT ;
    USE SIGNAL ;
    PORT
      LAYER M3 ;
        RECT  27.468 43.162 27.486 43.2 ;
    END
  END dn3_o[92]
  PIN dn3_o[93]
    DIRECTION OUTPUT ;
    USE SIGNAL ;
    PORT
      LAYER M5 ;
        RECT  27.648 43.116 27.672 43.2 ;
    END
  END dn3_o[93]
  PIN dn3_o[94]
    DIRECTION OUTPUT ;
    USE SIGNAL ;
    PORT
      LAYER M3 ;
        RECT  27.864 43.162 27.882 43.2 ;
    END
  END dn3_o[94]
  PIN dn3_o[95]
    DIRECTION OUTPUT ;
    USE SIGNAL ;
    PORT
      LAYER M5 ;
        RECT  28.032 43.116 28.056 43.2 ;
    END
  END dn3_o[95]
  PIN dn3_o[96]
    DIRECTION OUTPUT ;
    USE SIGNAL ;
    PORT
      LAYER M3 ;
        RECT  28.224 43.162 28.242 43.2 ;
    END
  END dn3_o[96]
  PIN dn3_o[97]
    DIRECTION OUTPUT ;
    USE SIGNAL ;
    PORT
      LAYER M5 ;
        RECT  28.416 43.116 28.44 43.2 ;
    END
  END dn3_o[97]
  PIN dn3_o[98]
    DIRECTION OUTPUT ;
    USE SIGNAL ;
    PORT
      LAYER M3 ;
        RECT  28.62 43.162 28.638 43.2 ;
    END
  END dn3_o[98]
  PIN dn3_o[99]
    DIRECTION OUTPUT ;
    USE SIGNAL ;
    PORT
      LAYER M5 ;
        RECT  28.8 43.116 28.824 43.2 ;
    END
  END dn3_o[99]
  PIN dn3_o[9]
    DIRECTION OUTPUT ;
    USE SIGNAL ;
    PORT
      LAYER M5 ;
        RECT  11.712 43.116 11.736 43.2 ;
    END
  END dn3_o[9]
  PIN rst_n
    DIRECTION INPUT ;
    USE SIGNAL ;
    PORT
      LAYER M4 ;
        RECT  0 39.216 0.084 39.24 ;
    END
    PORT
      LAYER M4 ;
        RECT  0.06 39.216 0.137 39.24 ;
    END
  END rst_n
  PIN up0_i[0]
    DIRECTION INPUT ;
    USE SIGNAL ;
    PORT
      LAYER M3 ;
        RECT  2.232 0 2.25 0.038 ;
    END
  END up0_i[0]
  PIN up0_i[10]
    DIRECTION INPUT ;
    USE SIGNAL ;
    PORT
      LAYER M3 ;
        RECT  4.14 0 4.158 0.038 ;
    END
  END up0_i[10]
  PIN up0_i[11]
    DIRECTION INPUT ;
    USE SIGNAL ;
    PORT
      LAYER M5 ;
        RECT  4.32 0 4.344 0.084 ;
    END
  END up0_i[11]
  PIN up0_i[12]
    DIRECTION INPUT ;
    USE SIGNAL ;
    PORT
      LAYER M3 ;
        RECT  4.536 0 4.554 0.038 ;
    END
  END up0_i[12]
  PIN up0_i[13]
    DIRECTION INPUT ;
    USE SIGNAL ;
    PORT
      LAYER M5 ;
        RECT  4.704 0 4.728 0.084 ;
    END
  END up0_i[13]
  PIN up0_i[14]
    DIRECTION INPUT ;
    USE SIGNAL ;
    PORT
      LAYER M3 ;
        RECT  4.896 0 4.914 0.038 ;
    END
  END up0_i[14]
  PIN up0_i[15]
    DIRECTION INPUT ;
    USE SIGNAL ;
    PORT
      LAYER M5 ;
        RECT  5.088 0 5.112 0.084 ;
    END
  END up0_i[15]
  PIN up0_i[16]
    DIRECTION INPUT ;
    USE SIGNAL ;
    PORT
      LAYER M3 ;
        RECT  5.292 0 5.31 0.038 ;
    END
  END up0_i[16]
  PIN up0_i[17]
    DIRECTION INPUT ;
    USE SIGNAL ;
    PORT
      LAYER M5 ;
        RECT  5.472 0 5.496 0.084 ;
    END
  END up0_i[17]
  PIN up0_i[18]
    DIRECTION INPUT ;
    USE SIGNAL ;
    PORT
      LAYER M3 ;
        RECT  5.652 0 5.67 0.038 ;
    END
  END up0_i[18]
  PIN up0_i[19]
    DIRECTION INPUT ;
    USE SIGNAL ;
    PORT
      LAYER M5 ;
        RECT  5.856 0 5.88 0.084 ;
    END
  END up0_i[19]
  PIN up0_i[1]
    DIRECTION INPUT ;
    USE SIGNAL ;
    PORT
      LAYER M5 ;
        RECT  2.448 0 2.472 0.084 ;
    END
  END up0_i[1]
  PIN up0_i[20]
    DIRECTION INPUT ;
    USE SIGNAL ;
    PORT
      LAYER M3 ;
        RECT  6.048 0 6.066 0.038 ;
    END
  END up0_i[20]
  PIN up0_i[21]
    DIRECTION INPUT ;
    USE SIGNAL ;
    PORT
      LAYER M5 ;
        RECT  6.24 0 6.264 0.084 ;
    END
  END up0_i[21]
  PIN up0_i[22]
    DIRECTION INPUT ;
    USE SIGNAL ;
    PORT
      LAYER M3 ;
        RECT  6.408 0 6.426 0.038 ;
    END
  END up0_i[22]
  PIN up0_i[23]
    DIRECTION INPUT ;
    USE SIGNAL ;
    PORT
      LAYER M5 ;
        RECT  6.624 0 6.648 0.084 ;
    END
  END up0_i[23]
  PIN up0_i[24]
    DIRECTION INPUT ;
    USE SIGNAL ;
    PORT
      LAYER M3 ;
        RECT  6.804 0 6.822 0.038 ;
    END
  END up0_i[24]
  PIN up0_i[25]
    DIRECTION INPUT ;
    USE SIGNAL ;
    PORT
      LAYER M5 ;
        RECT  7.008 0 7.032 0.084 ;
    END
  END up0_i[25]
  PIN up0_i[26]
    DIRECTION INPUT ;
    USE SIGNAL ;
    PORT
      LAYER M3 ;
        RECT  7.164 0 7.182 0.038 ;
    END
  END up0_i[26]
  PIN up0_i[27]
    DIRECTION INPUT ;
    USE SIGNAL ;
    PORT
      LAYER M5 ;
        RECT  7.344 0 7.368 0.084 ;
    END
  END up0_i[27]
  PIN up0_i[28]
    DIRECTION INPUT ;
    USE SIGNAL ;
    PORT
      LAYER M3 ;
        RECT  7.56 0 7.578 0.038 ;
    END
  END up0_i[28]
  PIN up0_i[29]
    DIRECTION INPUT ;
    USE SIGNAL ;
    PORT
      LAYER M5 ;
        RECT  7.728 0 7.752 0.084 ;
    END
  END up0_i[29]
  PIN up0_i[2]
    DIRECTION INPUT ;
    USE SIGNAL ;
    PORT
      LAYER M3 ;
        RECT  2.628 0 2.646 0.038 ;
    END
  END up0_i[2]
  PIN up0_i[30]
    DIRECTION INPUT ;
    USE SIGNAL ;
    PORT
      LAYER M3 ;
        RECT  7.92 0 7.938 0.038 ;
    END
  END up0_i[30]
  PIN up0_i[31]
    DIRECTION INPUT ;
    USE SIGNAL ;
    PORT
      LAYER M5 ;
        RECT  8.112 0 8.136 0.084 ;
    END
  END up0_i[31]
  PIN up0_i[32]
    DIRECTION INPUT ;
    USE SIGNAL ;
    PORT
      LAYER M3 ;
        RECT  8.316 0 8.334 0.038 ;
    END
  END up0_i[32]
  PIN up0_i[33]
    DIRECTION INPUT ;
    USE SIGNAL ;
    PORT
      LAYER M5 ;
        RECT  8.496 0 8.52 0.084 ;
    END
  END up0_i[33]
  PIN up0_i[34]
    DIRECTION INPUT ;
    USE SIGNAL ;
    PORT
      LAYER M3 ;
        RECT  8.712 0 8.73 0.038 ;
    END
  END up0_i[34]
  PIN up0_i[35]
    DIRECTION INPUT ;
    USE SIGNAL ;
    PORT
      LAYER M5 ;
        RECT  8.88 0 8.904 0.084 ;
    END
  END up0_i[35]
  PIN up0_i[36]
    DIRECTION INPUT ;
    USE SIGNAL ;
    PORT
      LAYER M3 ;
        RECT  9.072 0 9.09 0.038 ;
    END
  END up0_i[36]
  PIN up0_i[37]
    DIRECTION INPUT ;
    USE SIGNAL ;
    PORT
      LAYER M5 ;
        RECT  9.264 0 9.288 0.084 ;
    END
  END up0_i[37]
  PIN up0_i[38]
    DIRECTION INPUT ;
    USE SIGNAL ;
    PORT
      LAYER M3 ;
        RECT  9.468 0 9.486 0.038 ;
    END
  END up0_i[38]
  PIN up0_i[39]
    DIRECTION INPUT ;
    USE SIGNAL ;
    PORT
      LAYER M5 ;
        RECT  9.648 0 9.672 0.084 ;
    END
  END up0_i[39]
  PIN up0_i[3]
    DIRECTION INPUT ;
    USE SIGNAL ;
    PORT
      LAYER M5 ;
        RECT  2.832 0 2.856 0.084 ;
    END
  END up0_i[3]
  PIN up0_i[40]
    DIRECTION INPUT ;
    USE SIGNAL ;
    PORT
      LAYER M3 ;
        RECT  9.828 0 9.846 0.038 ;
    END
  END up0_i[40]
  PIN up0_i[4]
    DIRECTION INPUT ;
    USE SIGNAL ;
    PORT
      LAYER M3 ;
        RECT  2.988 0 3.006 0.038 ;
    END
  END up0_i[4]
  PIN up0_i[5]
    DIRECTION INPUT ;
    USE SIGNAL ;
    PORT
      LAYER M5 ;
        RECT  3.168 0 3.192 0.084 ;
    END
  END up0_i[5]
  PIN up0_i[6]
    DIRECTION INPUT ;
    USE SIGNAL ;
    PORT
      LAYER M3 ;
        RECT  3.384 0 3.402 0.038 ;
    END
  END up0_i[6]
  PIN up0_i[7]
    DIRECTION INPUT ;
    USE SIGNAL ;
    PORT
      LAYER M5 ;
        RECT  3.552 0 3.576 0.084 ;
    END
  END up0_i[7]
  PIN up0_i[8]
    DIRECTION INPUT ;
    USE SIGNAL ;
    PORT
      LAYER M3 ;
        RECT  3.78 0 3.798 0.038 ;
    END
  END up0_i[8]
  PIN up0_i[9]
    DIRECTION INPUT ;
    USE SIGNAL ;
    PORT
      LAYER M5 ;
        RECT  3.936 0 3.96 0.084 ;
    END
  END up0_i[9]
  PIN up1_i[0]
    DIRECTION INPUT ;
    USE SIGNAL ;
    PORT
      LAYER M4 ;
        RECT  43.116 2.256 43.2 2.28 ;
    END
  END up1_i[0]
  PIN up1_i[10]
    DIRECTION INPUT ;
    USE SIGNAL ;
    PORT
      LAYER M4 ;
        RECT  43.116 4.128 43.2 4.152 ;
    END
  END up1_i[10]
  PIN up1_i[11]
    DIRECTION INPUT ;
    USE SIGNAL ;
    PORT
      LAYER M4 ;
        RECT  43.116 4.32 43.2 4.344 ;
    END
  END up1_i[11]
  PIN up1_i[12]
    DIRECTION INPUT ;
    USE SIGNAL ;
    PORT
      LAYER M4 ;
        RECT  43.116 4.512 43.2 4.536 ;
    END
  END up1_i[12]
  PIN up1_i[13]
    DIRECTION INPUT ;
    USE SIGNAL ;
    PORT
      LAYER M4 ;
        RECT  43.116 4.704 43.2 4.728 ;
    END
  END up1_i[13]
  PIN up1_i[14]
    DIRECTION INPUT ;
    USE SIGNAL ;
    PORT
      LAYER M4 ;
        RECT  43.116 4.896 43.2 4.92 ;
    END
  END up1_i[14]
  PIN up1_i[15]
    DIRECTION INPUT ;
    USE SIGNAL ;
    PORT
      LAYER M4 ;
        RECT  43.116 5.088 43.2 5.112 ;
    END
  END up1_i[15]
  PIN up1_i[16]
    DIRECTION INPUT ;
    USE SIGNAL ;
    PORT
      LAYER M4 ;
        RECT  43.116 5.28 43.2 5.304 ;
    END
  END up1_i[16]
  PIN up1_i[17]
    DIRECTION INPUT ;
    USE SIGNAL ;
    PORT
      LAYER M4 ;
        RECT  43.116 5.472 43.2 5.496 ;
    END
  END up1_i[17]
  PIN up1_i[18]
    DIRECTION INPUT ;
    USE SIGNAL ;
    PORT
      LAYER M4 ;
        RECT  43.116 5.664 43.2 5.688 ;
    END
  END up1_i[18]
  PIN up1_i[19]
    DIRECTION INPUT ;
    USE SIGNAL ;
    PORT
      LAYER M4 ;
        RECT  43.116 5.856 43.2 5.88 ;
    END
  END up1_i[19]
  PIN up1_i[1]
    DIRECTION INPUT ;
    USE SIGNAL ;
    PORT
      LAYER M4 ;
        RECT  43.116 2.448 43.2 2.472 ;
    END
  END up1_i[1]
  PIN up1_i[20]
    DIRECTION INPUT ;
    USE SIGNAL ;
    PORT
      LAYER M4 ;
        RECT  43.116 6.048 43.2 6.072 ;
    END
  END up1_i[20]
  PIN up1_i[21]
    DIRECTION INPUT ;
    USE SIGNAL ;
    PORT
      LAYER M4 ;
        RECT  43.116 6.24 43.2 6.264 ;
    END
  END up1_i[21]
  PIN up1_i[22]
    DIRECTION INPUT ;
    USE SIGNAL ;
    PORT
      LAYER M4 ;
        RECT  43.116 6.432 43.2 6.456 ;
    END
  END up1_i[22]
  PIN up1_i[23]
    DIRECTION INPUT ;
    USE SIGNAL ;
    PORT
      LAYER M4 ;
        RECT  43.116 6.624 43.2 6.648 ;
    END
  END up1_i[23]
  PIN up1_i[24]
    DIRECTION INPUT ;
    USE SIGNAL ;
    PORT
      LAYER M4 ;
        RECT  43.116 6.816 43.2 6.84 ;
    END
  END up1_i[24]
  PIN up1_i[25]
    DIRECTION INPUT ;
    USE SIGNAL ;
    PORT
      LAYER M4 ;
        RECT  43.116 7.008 43.2 7.032 ;
    END
  END up1_i[25]
  PIN up1_i[26]
    DIRECTION INPUT ;
    USE SIGNAL ;
    PORT
      LAYER M4 ;
        RECT  43.116 7.152 43.2 7.176 ;
    END
  END up1_i[26]
  PIN up1_i[27]
    DIRECTION INPUT ;
    USE SIGNAL ;
    PORT
      LAYER M4 ;
        RECT  43.116 7.344 43.2 7.368 ;
    END
  END up1_i[27]
  PIN up1_i[28]
    DIRECTION INPUT ;
    USE SIGNAL ;
    PORT
      LAYER M4 ;
        RECT  43.116 7.536 43.2 7.56 ;
    END
  END up1_i[28]
  PIN up1_i[29]
    DIRECTION INPUT ;
    USE SIGNAL ;
    PORT
      LAYER M4 ;
        RECT  43.116 7.728 43.2 7.752 ;
    END
  END up1_i[29]
  PIN up1_i[2]
    DIRECTION INPUT ;
    USE SIGNAL ;
    PORT
      LAYER M4 ;
        RECT  43.116 2.64 43.2 2.664 ;
    END
  END up1_i[2]
  PIN up1_i[30]
    DIRECTION INPUT ;
    USE SIGNAL ;
    PORT
      LAYER M4 ;
        RECT  43.116 7.92 43.2 7.944 ;
    END
  END up1_i[30]
  PIN up1_i[31]
    DIRECTION INPUT ;
    USE SIGNAL ;
    PORT
      LAYER M4 ;
        RECT  43.116 8.112 43.2 8.136 ;
    END
  END up1_i[31]
  PIN up1_i[32]
    DIRECTION INPUT ;
    USE SIGNAL ;
    PORT
      LAYER M4 ;
        RECT  43.116 8.304 43.2 8.328 ;
    END
  END up1_i[32]
  PIN up1_i[33]
    DIRECTION INPUT ;
    USE SIGNAL ;
    PORT
      LAYER M4 ;
        RECT  43.116 8.496 43.2 8.52 ;
    END
  END up1_i[33]
  PIN up1_i[34]
    DIRECTION INPUT ;
    USE SIGNAL ;
    PORT
      LAYER M4 ;
        RECT  43.116 8.688 43.2 8.712 ;
    END
  END up1_i[34]
  PIN up1_i[35]
    DIRECTION INPUT ;
    USE SIGNAL ;
    PORT
      LAYER M4 ;
        RECT  43.116 8.88 43.2 8.904 ;
    END
  END up1_i[35]
  PIN up1_i[36]
    DIRECTION INPUT ;
    USE SIGNAL ;
    PORT
      LAYER M4 ;
        RECT  43.116 9.072 43.2 9.096 ;
    END
  END up1_i[36]
  PIN up1_i[37]
    DIRECTION INPUT ;
    USE SIGNAL ;
    PORT
      LAYER M4 ;
        RECT  43.116 9.264 43.2 9.288 ;
    END
  END up1_i[37]
  PIN up1_i[38]
    DIRECTION INPUT ;
    USE SIGNAL ;
    PORT
      LAYER M4 ;
        RECT  43.116 9.456 43.2 9.48 ;
    END
  END up1_i[38]
  PIN up1_i[39]
    DIRECTION INPUT ;
    USE SIGNAL ;
    PORT
      LAYER M4 ;
        RECT  43.116 9.648 43.2 9.672 ;
    END
  END up1_i[39]
  PIN up1_i[3]
    DIRECTION INPUT ;
    USE SIGNAL ;
    PORT
      LAYER M4 ;
        RECT  43.116 2.832 43.2 2.856 ;
    END
  END up1_i[3]
  PIN up1_i[40]
    DIRECTION INPUT ;
    USE SIGNAL ;
    PORT
      LAYER M4 ;
        RECT  43.116 9.84 43.2 9.864 ;
    END
  END up1_i[40]
  PIN up1_i[4]
    DIRECTION INPUT ;
    USE SIGNAL ;
    PORT
      LAYER M4 ;
        RECT  43.116 3.024 43.2 3.048 ;
    END
  END up1_i[4]
  PIN up1_i[5]
    DIRECTION INPUT ;
    USE SIGNAL ;
    PORT
      LAYER M4 ;
        RECT  43.116 3.168 43.2 3.192 ;
    END
  END up1_i[5]
  PIN up1_i[6]
    DIRECTION INPUT ;
    USE SIGNAL ;
    PORT
      LAYER M4 ;
        RECT  43.116 3.36 43.2 3.384 ;
    END
  END up1_i[6]
  PIN up1_i[7]
    DIRECTION INPUT ;
    USE SIGNAL ;
    PORT
      LAYER M4 ;
        RECT  43.116 3.552 43.2 3.576 ;
    END
  END up1_i[7]
  PIN up1_i[8]
    DIRECTION INPUT ;
    USE SIGNAL ;
    PORT
      LAYER M4 ;
        RECT  43.116 3.744 43.2 3.768 ;
    END
  END up1_i[8]
  PIN up1_i[9]
    DIRECTION INPUT ;
    USE SIGNAL ;
    PORT
      LAYER M4 ;
        RECT  43.116 3.936 43.2 3.96 ;
    END
  END up1_i[9]
  PIN up2_i[0]
    DIRECTION INPUT ;
    USE SIGNAL ;
    PORT
      LAYER M4 ;
        RECT  0 2.208 0.084 2.232 ;
    END
  END up2_i[0]
  PIN up2_i[10]
    DIRECTION INPUT ;
    USE SIGNAL ;
    PORT
      LAYER M4 ;
        RECT  0 3.888 0.084 3.912 ;
    END
  END up2_i[10]
  PIN up2_i[11]
    DIRECTION INPUT ;
    USE SIGNAL ;
    PORT
      LAYER M4 ;
        RECT  0 4.08 0.084 4.104 ;
    END
  END up2_i[11]
  PIN up2_i[12]
    DIRECTION INPUT ;
    USE SIGNAL ;
    PORT
      LAYER M4 ;
        RECT  0 4.224 0.084 4.248 ;
    END
  END up2_i[12]
  PIN up2_i[13]
    DIRECTION INPUT ;
    USE SIGNAL ;
    PORT
      LAYER M4 ;
        RECT  0 4.416 0.084 4.44 ;
    END
  END up2_i[13]
  PIN up2_i[14]
    DIRECTION INPUT ;
    USE SIGNAL ;
    PORT
      LAYER M4 ;
        RECT  0 4.56 0.084 4.584 ;
    END
  END up2_i[14]
  PIN up2_i[15]
    DIRECTION INPUT ;
    USE SIGNAL ;
    PORT
      LAYER M4 ;
        RECT  0 4.752 0.084 4.776 ;
    END
  END up2_i[15]
  PIN up2_i[16]
    DIRECTION INPUT ;
    USE SIGNAL ;
    PORT
      LAYER M4 ;
        RECT  0 4.896 0.084 4.92 ;
    END
  END up2_i[16]
  PIN up2_i[17]
    DIRECTION INPUT ;
    USE SIGNAL ;
    PORT
      LAYER M4 ;
        RECT  0 5.088 0.084 5.112 ;
    END
  END up2_i[17]
  PIN up2_i[18]
    DIRECTION INPUT ;
    USE SIGNAL ;
    PORT
      LAYER M4 ;
        RECT  0 5.232 0.084 5.256 ;
    END
  END up2_i[18]
  PIN up2_i[19]
    DIRECTION INPUT ;
    USE SIGNAL ;
    PORT
      LAYER M4 ;
        RECT  0 5.424 0.084 5.448 ;
    END
  END up2_i[19]
  PIN up2_i[1]
    DIRECTION INPUT ;
    USE SIGNAL ;
    PORT
      LAYER M4 ;
        RECT  0 2.4 0.084 2.424 ;
    END
  END up2_i[1]
  PIN up2_i[20]
    DIRECTION INPUT ;
    USE SIGNAL ;
    PORT
      LAYER M4 ;
        RECT  0 5.568 0.084 5.592 ;
    END
  END up2_i[20]
  PIN up2_i[21]
    DIRECTION INPUT ;
    USE SIGNAL ;
    PORT
      LAYER M4 ;
        RECT  0 5.712 0.084 5.736 ;
    END
  END up2_i[21]
  PIN up2_i[22]
    DIRECTION INPUT ;
    USE SIGNAL ;
    PORT
      LAYER M4 ;
        RECT  0 5.904 0.084 5.928 ;
    END
  END up2_i[22]
  PIN up2_i[23]
    DIRECTION INPUT ;
    USE SIGNAL ;
    PORT
      LAYER M4 ;
        RECT  0 6.048 0.084 6.072 ;
    END
  END up2_i[23]
  PIN up2_i[24]
    DIRECTION INPUT ;
    USE SIGNAL ;
    PORT
      LAYER M4 ;
        RECT  0 6.24 0.084 6.264 ;
    END
  END up2_i[24]
  PIN up2_i[25]
    DIRECTION INPUT ;
    USE SIGNAL ;
    PORT
      LAYER M4 ;
        RECT  0 6.384 0.084 6.408 ;
    END
  END up2_i[25]
  PIN up2_i[26]
    DIRECTION INPUT ;
    USE SIGNAL ;
    PORT
      LAYER M4 ;
        RECT  0 6.576 0.084 6.6 ;
    END
  END up2_i[26]
  PIN up2_i[27]
    DIRECTION INPUT ;
    USE SIGNAL ;
    PORT
      LAYER M4 ;
        RECT  0 6.72 0.084 6.744 ;
    END
  END up2_i[27]
  PIN up2_i[28]
    DIRECTION INPUT ;
    USE SIGNAL ;
    PORT
      LAYER M4 ;
        RECT  0 6.912 0.084 6.936 ;
    END
  END up2_i[28]
  PIN up2_i[29]
    DIRECTION INPUT ;
    USE SIGNAL ;
    PORT
      LAYER M4 ;
        RECT  0 7.056 0.084 7.08 ;
    END
  END up2_i[29]
  PIN up2_i[2]
    DIRECTION INPUT ;
    USE SIGNAL ;
    PORT
      LAYER M4 ;
        RECT  0 2.544 0.084 2.568 ;
    END
  END up2_i[2]
  PIN up2_i[30]
    DIRECTION INPUT ;
    USE SIGNAL ;
    PORT
      LAYER M4 ;
        RECT  0 7.248 0.084 7.272 ;
    END
  END up2_i[30]
  PIN up2_i[31]
    DIRECTION INPUT ;
    USE SIGNAL ;
    PORT
      LAYER M4 ;
        RECT  0 7.392 0.084 7.416 ;
    END
  END up2_i[31]
  PIN up2_i[32]
    DIRECTION INPUT ;
    USE SIGNAL ;
    PORT
      LAYER M4 ;
        RECT  0 7.584 0.084 7.608 ;
    END
  END up2_i[32]
  PIN up2_i[33]
    DIRECTION INPUT ;
    USE SIGNAL ;
    PORT
      LAYER M4 ;
        RECT  0 7.728 0.084 7.752 ;
    END
  END up2_i[33]
  PIN up2_i[34]
    DIRECTION INPUT ;
    USE SIGNAL ;
    PORT
      LAYER M4 ;
        RECT  0 7.92 0.084 7.944 ;
    END
  END up2_i[34]
  PIN up2_i[35]
    DIRECTION INPUT ;
    USE SIGNAL ;
    PORT
      LAYER M4 ;
        RECT  0 8.064 0.084 8.088 ;
    END
  END up2_i[35]
  PIN up2_i[36]
    DIRECTION INPUT ;
    USE SIGNAL ;
    PORT
      LAYER M4 ;
        RECT  0 8.256 0.084 8.28 ;
    END
  END up2_i[36]
  PIN up2_i[37]
    DIRECTION INPUT ;
    USE SIGNAL ;
    PORT
      LAYER M4 ;
        RECT  0 8.4 0.084 8.424 ;
    END
  END up2_i[37]
  PIN up2_i[38]
    DIRECTION INPUT ;
    USE SIGNAL ;
    PORT
      LAYER M4 ;
        RECT  0 8.592 0.084 8.616 ;
    END
  END up2_i[38]
  PIN up2_i[39]
    DIRECTION INPUT ;
    USE SIGNAL ;
    PORT
      LAYER M4 ;
        RECT  0 8.736 0.084 8.76 ;
    END
  END up2_i[39]
  PIN up2_i[3]
    DIRECTION INPUT ;
    USE SIGNAL ;
    PORT
      LAYER M4 ;
        RECT  0 2.736 0.084 2.76 ;
    END
  END up2_i[3]
  PIN up2_i[40]
    DIRECTION INPUT ;
    USE SIGNAL ;
    PORT
      LAYER M4 ;
        RECT  0 8.928 0.084 8.952 ;
    END
  END up2_i[40]
  PIN up2_i[4]
    DIRECTION INPUT ;
    USE SIGNAL ;
    PORT
      LAYER M4 ;
        RECT  0 2.88 0.084 2.904 ;
    END
  END up2_i[4]
  PIN up2_i[5]
    DIRECTION INPUT ;
    USE SIGNAL ;
    PORT
      LAYER M4 ;
        RECT  0 3.072 0.084 3.096 ;
    END
  END up2_i[5]
  PIN up2_i[6]
    DIRECTION INPUT ;
    USE SIGNAL ;
    PORT
      LAYER M4 ;
        RECT  0 3.216 0.084 3.24 ;
    END
  END up2_i[6]
  PIN up2_i[7]
    DIRECTION INPUT ;
    USE SIGNAL ;
    PORT
      LAYER M4 ;
        RECT  0 3.408 0.084 3.432 ;
    END
  END up2_i[7]
  PIN up2_i[8]
    DIRECTION INPUT ;
    USE SIGNAL ;
    PORT
      LAYER M4 ;
        RECT  0 3.552 0.084 3.576 ;
    END
  END up2_i[8]
  PIN up2_i[9]
    DIRECTION INPUT ;
    USE SIGNAL ;
    PORT
      LAYER M4 ;
        RECT  0 3.744 0.084 3.768 ;
    END
  END up2_i[9]
  PIN up3_i[0]
    DIRECTION INPUT ;
    USE SIGNAL ;
    PORT
      LAYER M3 ;
        RECT  2.232 43.162 2.25 43.2 ;
    END
  END up3_i[0]
  PIN up3_i[10]
    DIRECTION INPUT ;
    USE SIGNAL ;
    PORT
      LAYER M3 ;
        RECT  4.14 43.162 4.158 43.2 ;
    END
  END up3_i[10]
  PIN up3_i[11]
    DIRECTION INPUT ;
    USE SIGNAL ;
    PORT
      LAYER M5 ;
        RECT  4.32 43.116 4.344 43.2 ;
    END
  END up3_i[11]
  PIN up3_i[12]
    DIRECTION INPUT ;
    USE SIGNAL ;
    PORT
      LAYER M3 ;
        RECT  4.536 43.162 4.554 43.2 ;
    END
  END up3_i[12]
  PIN up3_i[13]
    DIRECTION INPUT ;
    USE SIGNAL ;
    PORT
      LAYER M5 ;
        RECT  4.704 43.116 4.728 43.2 ;
    END
  END up3_i[13]
  PIN up3_i[14]
    DIRECTION INPUT ;
    USE SIGNAL ;
    PORT
      LAYER M3 ;
        RECT  4.896 43.162 4.914 43.2 ;
    END
  END up3_i[14]
  PIN up3_i[15]
    DIRECTION INPUT ;
    USE SIGNAL ;
    PORT
      LAYER M5 ;
        RECT  5.088 43.116 5.112 43.2 ;
    END
  END up3_i[15]
  PIN up3_i[16]
    DIRECTION INPUT ;
    USE SIGNAL ;
    PORT
      LAYER M3 ;
        RECT  5.292 43.162 5.31 43.2 ;
    END
  END up3_i[16]
  PIN up3_i[17]
    DIRECTION INPUT ;
    USE SIGNAL ;
    PORT
      LAYER M5 ;
        RECT  5.472 43.116 5.496 43.2 ;
    END
  END up3_i[17]
  PIN up3_i[18]
    DIRECTION INPUT ;
    USE SIGNAL ;
    PORT
      LAYER M3 ;
        RECT  5.652 43.162 5.67 43.2 ;
    END
  END up3_i[18]
  PIN up3_i[19]
    DIRECTION INPUT ;
    USE SIGNAL ;
    PORT
      LAYER M5 ;
        RECT  5.856 43.116 5.88 43.2 ;
    END
  END up3_i[19]
  PIN up3_i[1]
    DIRECTION INPUT ;
    USE SIGNAL ;
    PORT
      LAYER M5 ;
        RECT  2.448 43.116 2.472 43.2 ;
    END
  END up3_i[1]
  PIN up3_i[20]
    DIRECTION INPUT ;
    USE SIGNAL ;
    PORT
      LAYER M3 ;
        RECT  6.048 43.162 6.066 43.2 ;
    END
  END up3_i[20]
  PIN up3_i[21]
    DIRECTION INPUT ;
    USE SIGNAL ;
    PORT
      LAYER M5 ;
        RECT  6.24 43.116 6.264 43.2 ;
    END
  END up3_i[21]
  PIN up3_i[22]
    DIRECTION INPUT ;
    USE SIGNAL ;
    PORT
      LAYER M3 ;
        RECT  6.408 43.162 6.426 43.2 ;
    END
  END up3_i[22]
  PIN up3_i[23]
    DIRECTION INPUT ;
    USE SIGNAL ;
    PORT
      LAYER M5 ;
        RECT  6.624 43.116 6.648 43.2 ;
    END
  END up3_i[23]
  PIN up3_i[24]
    DIRECTION INPUT ;
    USE SIGNAL ;
    PORT
      LAYER M3 ;
        RECT  6.804 43.162 6.822 43.2 ;
    END
  END up3_i[24]
  PIN up3_i[25]
    DIRECTION INPUT ;
    USE SIGNAL ;
    PORT
      LAYER M5 ;
        RECT  7.008 43.116 7.032 43.2 ;
    END
  END up3_i[25]
  PIN up3_i[26]
    DIRECTION INPUT ;
    USE SIGNAL ;
    PORT
      LAYER M3 ;
        RECT  7.164 43.162 7.182 43.2 ;
    END
  END up3_i[26]
  PIN up3_i[27]
    DIRECTION INPUT ;
    USE SIGNAL ;
    PORT
      LAYER M5 ;
        RECT  7.344 43.116 7.368 43.2 ;
    END
  END up3_i[27]
  PIN up3_i[28]
    DIRECTION INPUT ;
    USE SIGNAL ;
    PORT
      LAYER M3 ;
        RECT  7.56 43.162 7.578 43.2 ;
    END
  END up3_i[28]
  PIN up3_i[29]
    DIRECTION INPUT ;
    USE SIGNAL ;
    PORT
      LAYER M5 ;
        RECT  7.728 43.116 7.752 43.2 ;
    END
  END up3_i[29]
  PIN up3_i[2]
    DIRECTION INPUT ;
    USE SIGNAL ;
    PORT
      LAYER M3 ;
        RECT  2.628 43.162 2.646 43.2 ;
    END
  END up3_i[2]
  PIN up3_i[30]
    DIRECTION INPUT ;
    USE SIGNAL ;
    PORT
      LAYER M3 ;
        RECT  7.92 43.162 7.938 43.2 ;
    END
  END up3_i[30]
  PIN up3_i[31]
    DIRECTION INPUT ;
    USE SIGNAL ;
    PORT
      LAYER M5 ;
        RECT  8.112 43.116 8.136 43.2 ;
    END
  END up3_i[31]
  PIN up3_i[32]
    DIRECTION INPUT ;
    USE SIGNAL ;
    PORT
      LAYER M3 ;
        RECT  8.316 43.162 8.334 43.2 ;
    END
  END up3_i[32]
  PIN up3_i[33]
    DIRECTION INPUT ;
    USE SIGNAL ;
    PORT
      LAYER M5 ;
        RECT  8.496 43.116 8.52 43.2 ;
    END
  END up3_i[33]
  PIN up3_i[34]
    DIRECTION INPUT ;
    USE SIGNAL ;
    PORT
      LAYER M3 ;
        RECT  8.712 43.162 8.73 43.2 ;
    END
  END up3_i[34]
  PIN up3_i[35]
    DIRECTION INPUT ;
    USE SIGNAL ;
    PORT
      LAYER M5 ;
        RECT  8.88 43.116 8.904 43.2 ;
    END
  END up3_i[35]
  PIN up3_i[36]
    DIRECTION INPUT ;
    USE SIGNAL ;
    PORT
      LAYER M3 ;
        RECT  9.072 43.162 9.09 43.2 ;
    END
  END up3_i[36]
  PIN up3_i[37]
    DIRECTION INPUT ;
    USE SIGNAL ;
    PORT
      LAYER M5 ;
        RECT  9.264 43.116 9.288 43.2 ;
    END
  END up3_i[37]
  PIN up3_i[38]
    DIRECTION INPUT ;
    USE SIGNAL ;
    PORT
      LAYER M3 ;
        RECT  9.468 43.162 9.486 43.2 ;
    END
  END up3_i[38]
  PIN up3_i[39]
    DIRECTION INPUT ;
    USE SIGNAL ;
    PORT
      LAYER M5 ;
        RECT  9.648 43.116 9.672 43.2 ;
    END
  END up3_i[39]
  PIN up3_i[3]
    DIRECTION INPUT ;
    USE SIGNAL ;
    PORT
      LAYER M5 ;
        RECT  2.832 43.116 2.856 43.2 ;
    END
  END up3_i[3]
  PIN up3_i[40]
    DIRECTION INPUT ;
    USE SIGNAL ;
    PORT
      LAYER M3 ;
        RECT  9.828 43.162 9.846 43.2 ;
    END
  END up3_i[40]
  PIN up3_i[4]
    DIRECTION INPUT ;
    USE SIGNAL ;
    PORT
      LAYER M3 ;
        RECT  2.988 43.162 3.006 43.2 ;
    END
  END up3_i[4]
  PIN up3_i[5]
    DIRECTION INPUT ;
    USE SIGNAL ;
    PORT
      LAYER M5 ;
        RECT  3.168 43.116 3.192 43.2 ;
    END
  END up3_i[5]
  PIN up3_i[6]
    DIRECTION INPUT ;
    USE SIGNAL ;
    PORT
      LAYER M3 ;
        RECT  3.384 43.162 3.402 43.2 ;
    END
  END up3_i[6]
  PIN up3_i[7]
    DIRECTION INPUT ;
    USE SIGNAL ;
    PORT
      LAYER M5 ;
        RECT  3.552 43.116 3.576 43.2 ;
    END
  END up3_i[7]
  PIN up3_i[8]
    DIRECTION INPUT ;
    USE SIGNAL ;
    PORT
      LAYER M3 ;
        RECT  3.78 43.162 3.798 43.2 ;
    END
  END up3_i[8]
  PIN up3_i[9]
    DIRECTION INPUT ;
    USE SIGNAL ;
    PORT
      LAYER M5 ;
        RECT  3.936 43.116 3.96 43.2 ;
    END
  END up3_i[9]
  PIN VDD
    DIRECTION INOUT ;
    USE POWER ;
    PORT
      LAYER M5 ;
        RECT  40.392 2.151 40.512 41.049 ;
        RECT  34.992 2.151 35.112 41.049 ;
        RECT  29.592 2.151 29.712 41.049 ;
        RECT  24.192 2.151 24.312 41.049 ;
        RECT  18.792 2.151 18.912 41.049 ;
        RECT  13.392 2.151 13.512 41.049 ;
        RECT  7.992 2.151 8.112 41.049 ;
        RECT  2.592 2.151 2.712 41.049 ;
    END
  END VDD
  PIN VSS
    DIRECTION INOUT ;
    USE GROUND ;
    PORT
      LAYER M5 ;
        RECT  40.2 2.137 40.32 41.063 ;
        RECT  34.8 2.137 34.92 41.063 ;
        RECT  29.4 2.137 29.52 41.063 ;
        RECT  24 2.137 24.12 41.063 ;
        RECT  18.6 2.137 18.72 41.063 ;
        RECT  13.2 2.137 13.32 41.063 ;
        RECT  7.8 2.137 7.92 41.063 ;
        RECT  2.4 2.137 2.52 41.063 ;
    END
  END VSS
  # OT_OBS_CLOSED layer=M5 d_um=1.536 added=99
  OBS
    LAYER RVTN ;
     RECT  2.16 2.16 41.04 2.295 ;
     RECT  2.16 2.565 41.04 2.835 ;
     RECT  2.16 3.105 41.04 3.375 ;
     RECT  2.16 3.645 41.04 3.915 ;
     RECT  2.16 4.185 41.04 4.455 ;
     RECT  2.16 4.725 41.04 4.995 ;
     RECT  2.16 5.265 41.04 5.535 ;
     RECT  2.16 5.805 41.04 6.075 ;
     RECT  2.16 6.345 41.04 6.615 ;
     RECT  2.16 6.885 41.04 7.155 ;
     RECT  2.16 7.425 41.04 7.695 ;
     RECT  2.16 7.965 41.04 8.235 ;
     RECT  2.16 8.505 41.04 8.775 ;
     RECT  2.16 9.045 41.04 9.315 ;
     RECT  2.16 9.585 41.04 9.855 ;
     RECT  2.16 10.125 41.04 10.395 ;
     RECT  2.16 10.665 41.04 10.935 ;
     RECT  2.16 11.205 41.04 11.475 ;
     RECT  2.16 11.745 41.04 12.015 ;
     RECT  2.16 12.285 41.04 12.555 ;
     RECT  2.16 12.825 41.04 13.095 ;
     RECT  2.16 13.365 41.04 13.635 ;
     RECT  2.16 13.905 41.04 14.175 ;
     RECT  2.16 14.445 41.04 14.715 ;
     RECT  2.16 14.985 41.04 15.255 ;
     RECT  2.16 15.525 41.04 15.795 ;
     RECT  2.16 16.065 41.04 16.335 ;
     RECT  2.16 16.605 41.04 16.875 ;
     RECT  2.16 17.145 41.04 17.415 ;
     RECT  2.16 17.685 41.04 17.955 ;
     RECT  2.16 18.225 41.04 18.495 ;
     RECT  2.16 18.765 41.04 19.035 ;
     RECT  2.16 19.305 41.04 19.575 ;
     RECT  2.16 19.845 41.04 20.115 ;
     RECT  2.16 20.385 41.04 20.655 ;
     RECT  2.16 20.925 41.04 21.195 ;
     RECT  2.16 21.465 41.04 21.735 ;
     RECT  2.16 22.005 41.04 22.275 ;
     RECT  2.16 22.545 41.04 22.815 ;
     RECT  2.16 23.085 41.04 23.355 ;
     RECT  2.16 23.625 41.04 23.895 ;
     RECT  2.16 24.165 41.04 24.435 ;
     RECT  2.16 24.705 41.04 24.975 ;
     RECT  2.16 25.245 41.04 25.515 ;
     RECT  2.16 25.785 41.04 26.055 ;
     RECT  2.16 26.325 41.04 26.595 ;
     RECT  2.16 26.865 41.04 27.135 ;
     RECT  2.16 27.405 41.04 27.675 ;
     RECT  2.16 27.945 41.04 28.215 ;
     RECT  2.16 28.485 41.04 28.755 ;
     RECT  2.16 29.025 41.04 29.295 ;
     RECT  2.16 29.565 41.04 29.835 ;
     RECT  2.16 30.105 41.04 30.375 ;
     RECT  2.16 30.645 41.04 30.915 ;
     RECT  2.16 31.185 41.04 31.455 ;
     RECT  2.16 31.725 41.04 31.995 ;
     RECT  2.16 32.265 41.04 32.535 ;
     RECT  2.16 32.805 41.04 33.075 ;
     RECT  2.16 33.345 41.04 33.615 ;
     RECT  2.16 33.885 41.04 34.155 ;
     RECT  2.16 34.425 41.04 34.695 ;
     RECT  2.16 34.965 41.04 35.235 ;
     RECT  2.16 35.505 41.04 35.775 ;
     RECT  2.16 36.045 41.04 36.315 ;
     RECT  2.16 36.585 41.04 36.855 ;
     RECT  2.16 37.125 41.04 37.395 ;
     RECT  2.16 37.665 41.04 37.935 ;
     RECT  2.16 38.205 41.04 38.475 ;
     RECT  2.16 38.745 41.04 39.015 ;
     RECT  2.16 39.285 41.04 39.555 ;
     RECT  2.16 39.825 41.04 40.095 ;
     RECT  2.16 40.365 41.04 40.635 ;
     RECT  2.16 40.905 41.04 41.04 ;
    LAYER RVTP ;
     RECT  2.16 2.295 41.04 2.565 ;
     RECT  2.16 2.835 41.04 3.105 ;
     RECT  2.16 3.375 41.04 3.645 ;
     RECT  2.16 3.915 41.04 4.185 ;
     RECT  2.16 4.455 41.04 4.725 ;
     RECT  2.16 4.995 41.04 5.265 ;
     RECT  2.16 5.535 41.04 5.805 ;
     RECT  2.16 6.075 41.04 6.345 ;
     RECT  2.16 6.615 41.04 6.885 ;
     RECT  2.16 7.155 41.04 7.425 ;
     RECT  2.16 7.695 41.04 7.965 ;
     RECT  2.16 8.235 41.04 8.505 ;
     RECT  2.16 8.775 41.04 9.045 ;
     RECT  2.16 9.315 41.04 9.585 ;
     RECT  2.16 9.855 41.04 10.125 ;
     RECT  2.16 10.395 41.04 10.665 ;
     RECT  2.16 10.935 41.04 11.205 ;
     RECT  2.16 11.475 41.04 11.745 ;
     RECT  2.16 12.015 41.04 12.285 ;
     RECT  2.16 12.555 41.04 12.825 ;
     RECT  2.16 13.095 41.04 13.365 ;
     RECT  2.16 13.635 41.04 13.905 ;
     RECT  2.16 14.175 41.04 14.445 ;
     RECT  2.16 14.715 41.04 14.985 ;
     RECT  2.16 15.255 41.04 15.525 ;
     RECT  2.16 15.795 41.04 16.065 ;
     RECT  2.16 16.335 41.04 16.605 ;
     RECT  2.16 16.875 41.04 17.145 ;
     RECT  2.16 17.415 41.04 17.685 ;
     RECT  2.16 17.955 41.04 18.225 ;
     RECT  2.16 18.495 41.04 18.765 ;
     RECT  2.16 19.035 41.04 19.305 ;
     RECT  2.16 19.575 41.04 19.845 ;
     RECT  2.16 20.115 41.04 20.385 ;
     RECT  2.16 20.655 41.04 20.925 ;
     RECT  2.16 21.195 41.04 21.465 ;
     RECT  2.16 21.735 41.04 22.005 ;
     RECT  2.16 22.275 41.04 22.545 ;
     RECT  2.16 22.815 41.04 23.085 ;
     RECT  2.16 23.355 41.04 23.625 ;
     RECT  2.16 23.895 41.04 24.165 ;
     RECT  2.16 24.435 41.04 24.705 ;
     RECT  2.16 24.975 41.04 25.245 ;
     RECT  2.16 25.515 41.04 25.785 ;
     RECT  2.16 26.055 41.04 26.325 ;
     RECT  2.16 26.595 41.04 26.865 ;
     RECT  2.16 27.135 41.04 27.405 ;
     RECT  2.16 27.675 41.04 27.945 ;
     RECT  2.16 28.215 41.04 28.485 ;
     RECT  2.16 28.755 41.04 29.025 ;
     RECT  2.16 29.295 41.04 29.565 ;
     RECT  2.16 29.835 41.04 30.105 ;
     RECT  2.16 30.375 41.04 30.645 ;
     RECT  2.16 30.915 41.04 31.185 ;
     RECT  2.16 31.455 41.04 31.725 ;
     RECT  2.16 31.995 41.04 32.265 ;
     RECT  2.16 32.535 41.04 32.805 ;
     RECT  2.16 33.075 41.04 33.345 ;
     RECT  2.16 33.615 41.04 33.885 ;
     RECT  2.16 34.155 41.04 34.425 ;
     RECT  2.16 34.695 41.04 34.965 ;
     RECT  2.16 35.235 41.04 35.505 ;
     RECT  2.16 35.775 41.04 36.045 ;
     RECT  2.16 36.315 41.04 36.585 ;
     RECT  2.16 36.855 41.04 37.125 ;
     RECT  2.16 37.395 41.04 37.665 ;
     RECT  2.16 37.935 41.04 38.205 ;
     RECT  2.16 38.475 41.04 38.745 ;
     RECT  2.16 39.015 41.04 39.285 ;
     RECT  2.16 39.555 41.04 39.825 ;
     RECT  2.16 40.095 41.04 40.365 ;
     RECT  2.16 40.635 41.04 40.905 ;
    LAYER M1 ;
     RECT  2.16 2.151 41.04 41.049 ;
    LAYER M2 ;
     RECT  0.103 25.866 0.203 26.244 ;
     RECT  0.175 18.468 0.275 18.486 ;
     RECT  0.499 2.574 0.535 2.592 ;
     RECT  0.103 23.796 0.535 23.814 ;
     RECT  0.103 27.576 0.535 27.594 ;
     RECT  0.103 31.734 0.535 31.752 ;
     RECT  0.535 2.268 2.16 2.826 ;
     RECT  0.103 9.756 2.16 9.774 ;
     RECT  0.535 11.286 2.16 11.304 ;
     RECT  0.103 13.446 2.16 13.464 ;
     RECT  0.103 14.256 2.16 14.274 ;
     RECT  0.535 17.046 2.16 17.064 ;
     RECT  0.103 20.286 2.16 20.304 ;
     RECT  0.535 23.256 2.16 23.814 ;
     RECT  0.203 26.226 2.16 26.244 ;
     RECT  0.535 27.306 2.16 28.476 ;
     RECT  0.535 31.734 2.16 31.914 ;
     RECT  0.535 33.048 2.16 33.066 ;
     RECT  0.103 38.718 2.16 38.736 ;
     RECT  2.623 0.036 2.759 0.054 ;
     RECT  2.623 43.146 2.795 43.164 ;
     RECT  2.16 2.151 2.947 41.049 ;
     RECT  4.063 43.146 4.163 43.164 ;
     RECT  2.947 2.106 4.523 41.049 ;
     RECT  4.523 2.151 5.467 41.049 ;
     RECT  5.575 43.146 5.675 43.164 ;
     RECT  5.467 2.106 6.259 41.049 ;
     RECT  6.331 0.036 6.431 0.054 ;
     RECT  6.259 2.07 6.727 41.049 ;
     RECT  6.727 1.728 6.827 41.049 ;
     RECT  6.827 2.106 7.771 41.049 ;
     RECT  7.771 1.728 7.915 41.049 ;
     RECT  7.915 1.728 7.943 41.13 ;
     RECT  7.943 2.151 8.015 41.13 ;
     RECT  8.311 0.036 8.411 0.054 ;
     RECT  8.015 2.151 9.715 41.049 ;
     RECT  9.715 1.728 9.851 41.049 ;
     RECT  10.363 0.036 10.427 0.054 ;
     RECT  11.155 0.036 11.255 0.054 ;
     RECT  9.851 2.151 11.515 41.049 ;
     RECT  11.515 2.106 11.551 41.049 ;
     RECT  11.551 1.728 11.687 41.049 ;
     RECT  11.687 2.106 12.667 41.049 ;
     RECT  13.423 0.036 13.559 0.054 ;
     RECT  12.667 2.034 13.819 41.049 ;
     RECT  13.819 1.728 13.991 41.049 ;
     RECT  14.935 0.036 15.035 0.054 ;
     RECT  13.991 2.106 15.151 41.049 ;
     RECT  15.151 2.034 16.583 41.049 ;
     RECT  16.583 2.106 17.123 41.049 ;
     RECT  17.123 2.151 18.355 41.049 ;
     RECT  19.111 43.146 19.211 43.164 ;
     RECT  18.355 1.728 19.247 41.049 ;
     RECT  17.167 0.036 19.535 0.054 ;
     RECT  20.263 0.036 20.363 0.054 ;
     RECT  20.263 43.146 20.363 43.164 ;
     RECT  19.247 2.106 20.623 41.049 ;
     RECT  21.775 0.036 21.875 0.054 ;
     RECT  22.099 43.146 22.199 43.164 ;
     RECT  20.623 2.034 23.287 41.049 ;
     RECT  23.287 2.034 23.387 41.094 ;
     RECT  23.387 2.106 24.043 41.094 ;
     RECT  24.043 0.036 24.359 0.054 ;
     RECT  24.043 2.106 24.395 41.13 ;
     RECT  24.331 43.146 24.467 43.164 ;
     RECT  24.395 2.106 25.951 41.049 ;
     RECT  25.951 1.728 26.195 41.049 ;
     RECT  26.195 2.034 27.463 41.049 ;
     RECT  27.463 43.146 27.779 43.164 ;
     RECT  27.463 1.728 28.499 41.049 ;
     RECT  28.507 0.036 29.399 0.054 ;
     RECT  28.499 2.106 29.731 41.049 ;
     RECT  29.731 2.034 30.055 41.049 ;
     RECT  30.883 0.036 31.091 0.054 ;
     RECT  30.055 1.962 31.235 41.049 ;
     RECT  31.235 2.106 32.035 41.049 ;
     RECT  32.035 1.728 32.243 41.049 ;
     RECT  35.059 43.146 35.231 43.164 ;
     RECT  32.243 2.151 35.671 41.049 ;
     RECT  33.547 0.036 36.311 0.054 ;
     RECT  35.671 2.106 36.491 41.049 ;
     RECT  36.491 2.151 36.571 41.049 ;
     RECT  36.571 2.151 36.707 41.094 ;
     RECT  36.707 2.151 38.083 41.049 ;
     RECT  38.083 2.151 38.219 41.094 ;
     RECT  38.219 2.151 38.407 41.049 ;
     RECT  38.479 0.036 38.839 0.054 ;
     RECT  38.839 0.036 39.235 0.09 ;
     RECT  38.407 2.106 39.235 41.049 ;
     RECT  39.235 2.106 39.335 41.094 ;
     RECT  39.335 2.106 39.515 41.049 ;
     RECT  39.235 0.036 40.019 0.279 ;
     RECT  40.019 0.036 40.055 0.234 ;
     RECT  40.171 43.146 40.379 43.164 ;
     RECT  40.055 0.036 40.847 0.198 ;
     RECT  40.847 0.18 40.991 0.198 ;
     RECT  39.515 2.151 41.04 41.049 ;
     RECT  41.04 4.932 41.567 37.458 ;
     RECT  41.567 5.706 41.603 37.458 ;
     RECT  41.04 2.466 41.639 3.402 ;
     RECT  41.603 5.706 41.639 13.662 ;
     RECT  41.603 17.856 41.639 37.458 ;
     RECT  41.639 2.646 41.675 3.402 ;
     RECT  41.567 4.932 42.179 4.95 ;
     RECT  41.639 5.706 42.179 7.722 ;
     RECT  41.639 8.478 42.179 9.306 ;
     RECT  41.639 10.296 42.179 11.232 ;
     RECT  41.639 12.366 42.179 13.662 ;
     RECT  41.603 14.418 42.179 16.794 ;
     RECT  41.639 17.856 42.179 20.574 ;
     RECT  41.639 21.366 42.179 28.134 ;
     RECT  41.639 28.926 42.179 37.458 ;
     RECT  41.04 40.986 42.179 41.004 ;
     RECT  41.675 2.736 42.215 3.402 ;
     RECT  42.179 5.976 42.215 7.722 ;
     RECT  42.179 8.478 42.215 9.072 ;
     RECT  42.179 12.366 42.215 13.464 ;
     RECT  42.179 15.426 42.215 16.164 ;
     RECT  42.179 21.546 42.215 21.564 ;
     RECT  42.179 23.166 42.215 24.93 ;
     RECT  42.179 26.064 42.215 27.504 ;
     RECT  42.179 30.42 42.215 32.868 ;
     RECT  42.179 33.93 42.215 35.154 ;
     RECT  41.04 39.366 42.215 40.194 ;
     RECT  42.215 6.39 42.287 6.84 ;
     RECT  42.179 36.018 42.287 37.458 ;
     RECT  42.215 3.15 43.079 3.402 ;
     RECT  42.287 36.018 43.079 36.774 ;
     RECT  43.079 3.15 43.115 3.168 ;
     RECT  42.287 6.822 43.115 6.84 ;
     RECT  42.215 7.632 43.115 7.65 ;
     RECT  42.215 9.054 43.115 9.072 ;
     RECT  42.179 10.476 43.115 11.232 ;
     RECT  42.215 12.726 43.115 13.464 ;
     RECT  42.179 14.616 43.115 14.634 ;
     RECT  42.215 15.426 43.115 15.444 ;
     RECT  42.179 18.396 43.115 18.414 ;
     RECT  42.179 20.016 43.115 20.484 ;
     RECT  42.215 23.796 43.115 24.93 ;
     RECT  42.215 26.676 43.115 27.162 ;
     RECT  42.179 29.466 43.115 29.484 ;
     RECT  42.215 31.356 43.115 31.374 ;
     RECT  42.215 32.436 43.115 32.832 ;
     RECT  42.215 34.326 43.115 34.344 ;
     RECT  42.215 35.136 43.115 35.154 ;
     RECT  42.215 40.104 43.115 40.122 ;
     RECT  43.079 36.756 43.151 36.774 ;
    LAYER M3 ;
     RECT  2.25 0.012 2.628 0.031 ;
     RECT  2.646 0.012 2.988 0.031 ;
     RECT  3.006 0.012 3.384 0.031 ;
     RECT  3.402 0.012 3.78 0.031 ;
     RECT  3.798 0.012 4.14 0.031 ;
     RECT  4.158 0.012 4.536 0.031 ;
     RECT  4.554 0.012 4.896 0.031 ;
     RECT  4.914 0.012 5.292 0.031 ;
     RECT  5.31 0.012 5.652 0.031 ;
     RECT  5.67 0.012 6.048 0.031 ;
     RECT  6.066 0.012 6.408 0.031 ;
     RECT  6.426 0.012 6.804 0.031 ;
     RECT  6.822 0.012 7.164 0.031 ;
     RECT  7.182 0.012 7.56 0.031 ;
     RECT  7.578 0.012 7.92 0.031 ;
     RECT  7.938 0.012 8.316 0.031 ;
     RECT  8.334 0.012 8.712 0.031 ;
     RECT  8.73 0.012 9.072 0.031 ;
     RECT  9.09 0.012 9.468 0.031 ;
     RECT  9.486 0.012 9.828 0.031 ;
     RECT  9.846 0.012 10.008 0.031 ;
     RECT  10.026 0.012 10.404 0.031 ;
     RECT  10.422 0.012 10.764 0.031 ;
     RECT  10.782 0.012 11.16 0.031 ;
     RECT  11.178 0.012 11.556 0.031 ;
     RECT  11.574 0.012 11.916 0.031 ;
     RECT  11.934 0.012 12.312 0.031 ;
     RECT  12.33 0.012 12.672 0.031 ;
     RECT  12.69 0.012 13.068 0.031 ;
     RECT  13.086 0.012 13.428 0.031 ;
     RECT  13.446 0.012 13.824 0.031 ;
     RECT  13.842 0.012 14.184 0.031 ;
     RECT  14.202 0.012 14.58 0.031 ;
     RECT  14.598 0.012 14.94 0.031 ;
     RECT  14.958 0.012 15.336 0.031 ;
     RECT  15.354 0.012 15.696 0.031 ;
     RECT  15.714 0.012 16.092 0.031 ;
     RECT  16.11 0.012 16.488 0.031 ;
     RECT  16.506 0.012 16.848 0.031 ;
     RECT  16.866 0.012 17.244 0.031 ;
     RECT  17.262 0.012 17.604 0.031 ;
     RECT  17.622 0.012 18 0.031 ;
     RECT  18.018 0.012 18.36 0.031 ;
     RECT  18.378 0.012 18.756 0.031 ;
     RECT  18.774 0.012 19.116 0.031 ;
     RECT  19.134 0.012 19.512 0.031 ;
     RECT  19.53 0.012 19.872 0.031 ;
     RECT  19.89 0.012 20.268 0.031 ;
     RECT  20.286 0.012 20.628 0.031 ;
     RECT  20.646 0.012 21.024 0.031 ;
     RECT  21.042 0.012 21.384 0.031 ;
     RECT  21.402 0.012 21.78 0.031 ;
     RECT  21.798 0.012 22.176 0.031 ;
     RECT  22.194 0.012 22.536 0.031 ;
     RECT  22.554 0.012 22.932 0.031 ;
     RECT  22.95 0.012 23.292 0.031 ;
     RECT  23.31 0.012 23.688 0.031 ;
     RECT  23.706 0.012 24.048 0.031 ;
     RECT  24.066 0.012 24.444 0.031 ;
     RECT  24.462 0.012 24.804 0.031 ;
     RECT  24.822 0.012 25.2 0.031 ;
     RECT  25.218 0.012 25.56 0.031 ;
     RECT  25.578 0.012 25.956 0.031 ;
     RECT  25.974 0.012 26.316 0.031 ;
     RECT  26.334 0.012 26.712 0.031 ;
     RECT  26.73 0.012 27.108 0.031 ;
     RECT  27.126 0.012 27.468 0.031 ;
     RECT  27.486 0.012 27.864 0.031 ;
     RECT  27.882 0.012 28.224 0.031 ;
     RECT  28.242 0.012 28.62 0.031 ;
     RECT  28.638 0.012 28.98 0.031 ;
     RECT  28.998 0.012 29.376 0.031 ;
     RECT  29.394 0.012 29.736 0.031 ;
     RECT  29.754 0.012 30.132 0.031 ;
     RECT  30.15 0.012 30.492 0.031 ;
     RECT  30.51 0.012 30.888 0.031 ;
     RECT  30.906 0.012 31.248 0.031 ;
     RECT  31.266 0.012 31.644 0.031 ;
     RECT  31.662 0.012 32.04 0.031 ;
     RECT  32.058 0.012 32.4 0.031 ;
     RECT  32.418 0.012 32.796 0.031 ;
     RECT  32.814 0.012 33.156 0.031 ;
     RECT  33.174 0.012 33.552 0.031 ;
     RECT  33.57 0.012 33.912 0.031 ;
     RECT  33.93 0.012 34.308 0.031 ;
     RECT  34.326 0.012 34.668 0.031 ;
     RECT  34.686 0.012 35.064 0.031 ;
     RECT  35.082 0.012 35.424 0.031 ;
     RECT  35.442 0.012 35.82 0.031 ;
     RECT  35.838 0.012 36.18 0.031 ;
     RECT  36.198 0.012 36.576 0.031 ;
     RECT  36.594 0.012 36.936 0.031 ;
     RECT  36.954 0.012 37.332 0.031 ;
     RECT  37.35 0.012 37.728 0.031 ;
     RECT  37.746 0.012 38.088 0.031 ;
     RECT  38.106 0.012 38.484 0.031 ;
     RECT  38.502 0.012 38.844 0.031 ;
     RECT  38.862 0.012 39.24 0.031 ;
     RECT  39.258 0.012 39.6 0.031 ;
     RECT  39.618 0.012 39.996 0.031 ;
     RECT  40.014 0.012 40.356 0.031 ;
     RECT  40.374 0.012 40.752 0.031 ;
     RECT  2.25 0.031 2.628 0.038 ;
     RECT  2.646 0.031 2.988 0.038 ;
     RECT  3.006 0.031 3.384 0.038 ;
     RECT  3.402 0.031 3.78 0.038 ;
     RECT  3.798 0.031 4.14 0.038 ;
     RECT  4.158 0.031 4.536 0.038 ;
     RECT  4.554 0.031 4.896 0.038 ;
     RECT  4.914 0.031 5.292 0.038 ;
     RECT  5.31 0.031 5.652 0.038 ;
     RECT  5.67 0.031 6.048 0.038 ;
     RECT  6.066 0.031 6.408 0.038 ;
     RECT  6.426 0.031 6.804 0.038 ;
     RECT  6.822 0.031 7.164 0.038 ;
     RECT  7.182 0.031 7.56 0.038 ;
     RECT  7.578 0.031 7.92 0.038 ;
     RECT  7.938 0.031 8.316 0.038 ;
     RECT  8.334 0.031 8.712 0.038 ;
     RECT  8.73 0.031 9.072 0.038 ;
     RECT  9.09 0.031 9.468 0.038 ;
     RECT  9.486 0.031 9.828 0.038 ;
     RECT  9.846 0.031 10.008 0.038 ;
     RECT  10.026 0.031 10.404 0.038 ;
     RECT  10.422 0.031 10.764 0.038 ;
     RECT  10.782 0.031 11.16 0.038 ;
     RECT  11.178 0.031 11.556 0.038 ;
     RECT  11.574 0.031 11.916 0.038 ;
     RECT  11.934 0.031 12.312 0.038 ;
     RECT  12.33 0.031 12.672 0.038 ;
     RECT  12.69 0.031 13.068 0.038 ;
     RECT  13.086 0.031 13.428 0.038 ;
     RECT  13.446 0.031 13.824 0.038 ;
     RECT  13.842 0.031 14.184 0.038 ;
     RECT  14.202 0.031 14.58 0.038 ;
     RECT  14.598 0.031 14.94 0.038 ;
     RECT  14.958 0.031 15.336 0.038 ;
     RECT  15.354 0.031 15.696 0.038 ;
     RECT  15.714 0.031 16.092 0.038 ;
     RECT  16.11 0.031 16.488 0.038 ;
     RECT  16.506 0.031 16.848 0.038 ;
     RECT  16.866 0.031 17.244 0.038 ;
     RECT  17.262 0.031 17.604 0.038 ;
     RECT  17.622 0.031 18 0.038 ;
     RECT  18.018 0.031 18.36 0.038 ;
     RECT  18.378 0.031 18.756 0.038 ;
     RECT  18.774 0.031 19.116 0.038 ;
     RECT  19.134 0.031 19.512 0.038 ;
     RECT  19.53 0.031 19.872 0.038 ;
     RECT  19.89 0.031 20.268 0.038 ;
     RECT  20.286 0.031 20.628 0.038 ;
     RECT  20.646 0.031 21.024 0.038 ;
     RECT  21.042 0.031 21.384 0.038 ;
     RECT  21.402 0.031 21.78 0.038 ;
     RECT  21.798 0.031 22.176 0.038 ;
     RECT  22.194 0.031 22.536 0.038 ;
     RECT  22.554 0.031 22.932 0.038 ;
     RECT  22.95 0.031 23.292 0.038 ;
     RECT  23.31 0.031 23.688 0.038 ;
     RECT  23.706 0.031 24.048 0.038 ;
     RECT  24.066 0.031 24.444 0.038 ;
     RECT  24.462 0.031 24.804 0.038 ;
     RECT  24.822 0.031 25.2 0.038 ;
     RECT  25.218 0.031 25.56 0.038 ;
     RECT  25.578 0.031 25.956 0.038 ;
     RECT  25.974 0.031 26.316 0.038 ;
     RECT  26.334 0.031 26.712 0.038 ;
     RECT  26.73 0.031 27.108 0.038 ;
     RECT  27.126 0.031 27.468 0.038 ;
     RECT  27.486 0.031 27.864 0.038 ;
     RECT  27.882 0.031 28.224 0.038 ;
     RECT  28.242 0.031 28.62 0.038 ;
     RECT  28.638 0.031 28.98 0.038 ;
     RECT  28.998 0.031 29.376 0.038 ;
     RECT  29.394 0.031 29.736 0.038 ;
     RECT  29.754 0.031 30.132 0.038 ;
     RECT  30.15 0.031 30.492 0.038 ;
     RECT  30.51 0.031 30.888 0.038 ;
     RECT  30.906 0.031 31.248 0.038 ;
     RECT  31.266 0.031 31.644 0.038 ;
     RECT  31.662 0.031 32.04 0.038 ;
     RECT  32.058 0.031 32.4 0.038 ;
     RECT  32.418 0.031 32.796 0.038 ;
     RECT  32.814 0.031 33.156 0.038 ;
     RECT  33.174 0.031 33.552 0.038 ;
     RECT  33.57 0.031 33.912 0.038 ;
     RECT  33.93 0.031 34.308 0.038 ;
     RECT  34.326 0.031 34.668 0.038 ;
     RECT  34.686 0.031 35.064 0.038 ;
     RECT  35.082 0.031 35.424 0.038 ;
     RECT  35.442 0.031 35.82 0.038 ;
     RECT  35.838 0.031 36.18 0.038 ;
     RECT  36.198 0.031 36.576 0.038 ;
     RECT  36.594 0.031 36.936 0.038 ;
     RECT  36.954 0.031 37.332 0.038 ;
     RECT  37.35 0.031 37.728 0.038 ;
     RECT  37.746 0.031 38.088 0.038 ;
     RECT  38.106 0.031 38.484 0.038 ;
     RECT  38.502 0.031 38.844 0.038 ;
     RECT  38.862 0.031 39.24 0.038 ;
     RECT  39.258 0.031 39.6 0.038 ;
     RECT  39.618 0.031 39.996 0.038 ;
     RECT  40.014 0.031 40.356 0.038 ;
     RECT  40.374 0.031 40.752 0.038 ;
     RECT  40.77 0.031 40.842 0.038 ;
     RECT  2.232 0.038 40.842 0.095 ;
     RECT  39.06 0.095 40.842 0.175 ;
     RECT  2.232 0.095 38.286 2.101 ;
     RECT  39.06 0.175 40.986 2.101 ;
     RECT  2.232 2.101 40.986 2.461 ;
     RECT  0.54 2.263 0.558 2.569 ;
     RECT  2.232 2.461 41.634 2.641 ;
     RECT  0.504 2.569 0.558 2.731 ;
     RECT  2.232 2.641 41.67 2.731 ;
     RECT  2.232 2.731 42.21 2.861 ;
     RECT  0.144 2.731 0.558 2.909 ;
     RECT  43.092 2.251 43.11 3.019 ;
     RECT  43.056 3.019 43.11 3.173 ;
     RECT  0.144 2.909 0.522 3.245 ;
     RECT  43.056 3.173 43.074 3.407 ;
     RECT  0.144 3.245 0.198 3.869 ;
     RECT  2.232 2.861 41.67 3.931 ;
     RECT  2.232 3.931 42.174 3.983 ;
     RECT  0.144 3.869 0.162 4.205 ;
     RECT  43.092 4.315 43.11 4.445 ;
     RECT  2.304 3.983 42.174 4.507 ;
     RECT  0.108 4.555 0.126 4.685 ;
     RECT  2.304 4.507 42.21 4.919 ;
     RECT  2.304 4.919 24.318 4.925 ;
     RECT  2.304 4.925 24.297 4.991 ;
     RECT  12.78 4.991 24.297 5.021 ;
     RECT  2.304 4.991 12.006 5.099 ;
     RECT  12.816 5.021 24.297 5.099 ;
     RECT  2.304 5.099 11.826 5.189 ;
     RECT  25.092 4.919 42.21 5.213 ;
     RECT  2.304 5.189 11.754 5.645 ;
     RECT  26.928 5.213 42.21 5.837 ;
     RECT  28.332 5.837 42.21 5.851 ;
     RECT  28.332 5.851 42.93 6.029 ;
     RECT  28.548 6.029 42.93 6.043 ;
     RECT  28.548 6.043 43.11 6.071 ;
     RECT  42.156 6.071 43.11 6.077 ;
     RECT  25.092 5.213 26.082 6.115 ;
     RECT  26.928 5.837 27.522 6.115 ;
     RECT  42.156 6.077 42.282 6.173 ;
     RECT  28.548 6.071 40.986 6.683 ;
     RECT  12.816 5.099 23.13 6.719 ;
     RECT  0.144 5.419 0.162 6.749 ;
     RECT  42.192 6.173 42.282 7.037 ;
     RECT  42.192 7.037 42.21 7.147 ;
     RECT  12.816 6.719 22.194 7.151 ;
     RECT  12.816 7.151 22.014 7.181 ;
     RECT  28.548 6.683 40.842 7.501 ;
     RECT  41.58 7.147 42.21 7.501 ;
     RECT  23.112 6.719 23.13 7.529 ;
     RECT  43.092 6.077 43.11 7.655 ;
     RECT  0.144 7.675 0.162 7.949 ;
     RECT  28.548 7.501 42.21 7.949 ;
     RECT  41.58 7.949 42.21 8.525 ;
     RECT  2.304 5.645 11.322 8.587 ;
     RECT  2.196 8.587 11.322 8.807 ;
     RECT  2.304 8.807 11.322 8.879 ;
     RECT  43.092 8.875 43.11 9.077 ;
     RECT  2.304 8.879 11.142 9.248 ;
     RECT  41.58 8.525 42.174 9.311 ;
     RECT  25.092 6.115 27.522 9.419 ;
     RECT  24.015 5.099 24.297 9.661 ;
     RECT  0.144 9.403 0.162 9.739 ;
     RECT  0.108 9.739 0.162 9.779 ;
     RECT  24.015 9.661 24.534 9.959 ;
     RECT  41.58 9.311 41.634 9.959 ;
     RECT  28.548 7.949 40.497 10.021 ;
     RECT  28.548 10.021 41.022 10.061 ;
     RECT  0.144 9.779 0.162 10.253 ;
     RECT  2.415 9.248 11.142 10.471 ;
     RECT  42.156 10.219 42.174 10.637 ;
     RECT  28.548 10.061 40.497 10.795 ;
     RECT  2.415 10.471 11.466 10.831 ;
     RECT  2.415 10.831 11.718 10.891 ;
     RECT  2.34 10.891 11.718 11.035 ;
     RECT  43.092 10.411 43.11 11.237 ;
     RECT  12.816 7.181 18.897 11.281 ;
     RECT  28.548 10.795 41.022 11.323 ;
     RECT  2.304 11.035 11.718 11.407 ;
     RECT  0.54 11.281 0.558 11.549 ;
     RECT  2.304 11.407 11.79 11.551 ;
     RECT  12.528 11.281 18.897 11.551 ;
     RECT  28.548 11.323 41.598 11.641 ;
     RECT  2.304 11.551 18.897 11.669 ;
     RECT  28.548 11.641 41.634 12.361 ;
     RECT  2.304 11.669 2.697 12.487 ;
     RECT  3.456 11.669 18.897 12.487 ;
     RECT  2.304 12.487 18.897 12.509 ;
     RECT  28.548 12.361 42.21 12.509 ;
     RECT  28.548 12.509 41.598 13.019 ;
     RECT  0.108 12.667 0.126 13.469 ;
     RECT  43.092 12.667 43.11 13.469 ;
     RECT  2.415 12.509 18.897 13.525 ;
     RECT  42.156 13.627 42.174 13.667 ;
     RECT  28.548 13.019 41.058 13.819 ;
     RECT  2.304 13.525 18.897 13.865 ;
     RECT  28.548 13.819 41.598 13.865 ;
     RECT  28.548 13.865 41.058 14.045 ;
     RECT  3.42 13.865 18.897 14.099 ;
     RECT  2.304 13.865 2.697 14.207 ;
     RECT  0.144 14.011 0.162 14.251 ;
     RECT  3.42 14.099 8.37 14.369 ;
     RECT  0.108 14.251 0.162 14.381 ;
     RECT  9.18 14.099 18.897 14.477 ;
     RECT  28.548 14.045 41.022 14.549 ;
     RECT  9.9 14.477 18.897 14.639 ;
     RECT  28.548 14.549 40.59 14.909 ;
     RECT  0.144 14.381 0.162 14.957 ;
     RECT  2.415 14.207 2.697 14.971 ;
     RECT  42.156 14.395 42.174 15.115 ;
     RECT  42.12 15.115 42.174 15.179 ;
     RECT  9.936 14.639 18.897 15.251 ;
     RECT  2.304 14.971 2.697 15.421 ;
     RECT  3.456 14.369 8.37 15.421 ;
     RECT  43.092 14.587 43.11 15.449 ;
     RECT  42.156 15.179 42.174 15.601 ;
     RECT  42.156 15.601 42.21 16.075 ;
     RECT  41.58 16.075 42.21 16.259 ;
     RECT  42.156 16.259 42.21 16.493 ;
     RECT  28.548 14.909 40.497 16.681 ;
     RECT  19.656 7.181 22.014 16.709 ;
     RECT  42.156 16.493 42.174 16.799 ;
     RECT  2.304 15.421 8.37 16.807 ;
     RECT  2.304 16.807 8.442 16.907 ;
     RECT  2.415 16.907 8.442 17.069 ;
     RECT  10.116 15.251 18.897 17.077 ;
     RECT  0.54 17.041 0.558 17.165 ;
     RECT  28.548 16.681 41.058 17.227 ;
     RECT  9.216 17.419 9.234 17.491 ;
     RECT  10.116 17.077 18.954 17.581 ;
     RECT  0.144 17.179 0.162 17.645 ;
     RECT  28.548 17.227 41.598 17.645 ;
     RECT  10.116 17.581 18.99 17.681 ;
     RECT  2.415 17.069 8.37 17.761 ;
     RECT  41.58 17.645 41.598 17.803 ;
     RECT  9.144 17.491 9.234 17.851 ;
     RECT  20.196 16.709 22.014 17.923 ;
     RECT  9.144 17.851 9.306 17.987 ;
     RECT  19.944 17.923 22.014 18.023 ;
     RECT  9.144 17.987 9.234 18.059 ;
     RECT  20.196 18.023 22.014 18.059 ;
     RECT  9.144 18.059 9.162 18.149 ;
     RECT  2.304 17.761 8.37 18.329 ;
     RECT  43.092 18.379 43.11 18.419 ;
     RECT  0.18 18.427 0.198 18.463 ;
     RECT  0.18 18.463 0.27 18.509 ;
     RECT  2.415 18.329 8.37 18.571 ;
     RECT  0.18 18.509 0.198 18.653 ;
     RECT  2.415 18.571 8.622 18.689 ;
     RECT  41.58 17.803 42.174 18.749 ;
     RECT  10.116 17.681 18.954 18.805 ;
     RECT  20.448 18.059 22.014 18.869 ;
     RECT  28.548 17.645 40.497 19.099 ;
     RECT  21.924 18.869 22.014 19.229 ;
     RECT  28.548 19.099 41.022 19.229 ;
     RECT  10.116 18.805 19.026 19.345 ;
     RECT  21.924 19.229 21.942 19.409 ;
     RECT  2.415 18.689 8.334 19.435 ;
     RECT  10.116 19.345 19.422 19.471 ;
     RECT  2.304 19.435 8.334 20.083 ;
     RECT  0.108 20.251 0.126 20.309 ;
     RECT  2.304 20.083 8.982 20.309 ;
     RECT  22.032 20.047 22.266 20.425 ;
     RECT  2.304 20.309 8.334 20.489 ;
     RECT  43.092 19.867 43.11 20.489 ;
     RECT  28.548 19.229 40.497 20.551 ;
     RECT  42.156 18.749 42.174 20.635 ;
     RECT  22.032 20.425 22.842 20.731 ;
     RECT  24.015 9.959 24.297 20.731 ;
     RECT  20.448 18.869 20.682 20.821 ;
     RECT  9.216 20.659 9.234 20.957 ;
     RECT  41.58 20.635 42.174 20.993 ;
     RECT  0.144 20.971 0.162 21.101 ;
     RECT  22.032 20.731 24.297 21.235 ;
     RECT  2.304 20.489 2.697 21.361 ;
     RECT  3.456 20.489 8.334 21.361 ;
     RECT  22.032 21.235 24.426 21.361 ;
     RECT  28.548 20.551 40.518 21.403 ;
     RECT  20.448 20.821 20.79 21.433 ;
     RECT  21.78 21.361 24.426 21.433 ;
     RECT  25.452 9.419 27.522 21.469 ;
     RECT  28.548 21.403 41.022 21.497 ;
     RECT  42.156 20.993 42.174 21.541 ;
     RECT  42.156 21.541 42.21 21.629 ;
     RECT  2.304 21.361 8.334 21.631 ;
     RECT  25.38 21.469 27.522 21.811 ;
     RECT  2.304 21.631 8.37 21.965 ;
     RECT  42.156 21.629 42.174 21.973 ;
     RECT  20.448 21.433 24.426 22.045 ;
     RECT  25.344 21.811 27.522 22.045 ;
     RECT  0.144 21.931 0.162 22.061 ;
     RECT  2.304 21.965 8.262 22.109 ;
     RECT  42.12 21.973 42.174 22.165 ;
     RECT  41.616 22.165 42.174 22.555 ;
     RECT  41.58 22.555 42.174 22.613 ;
     RECT  2.415 22.109 8.262 22.781 ;
     RECT  2.415 22.781 2.697 22.891 ;
     RECT  28.548 21.497 40.497 22.891 ;
     RECT  28.548 22.891 41.022 23.009 ;
     RECT  2.412 22.891 2.697 23.117 ;
     RECT  42.156 22.613 42.174 23.161 ;
     RECT  42.156 23.161 42.21 23.309 ;
     RECT  0.54 23.251 0.558 23.405 ;
     RECT  41.58 23.467 41.634 23.549 ;
     RECT  2.415 23.117 2.697 24.043 ;
     RECT  41.616 23.549 41.634 24.043 ;
     RECT  20.448 22.045 27.522 24.331 ;
     RECT  2.304 24.043 2.697 24.475 ;
     RECT  3.456 22.781 8.262 24.475 ;
     RECT  0.108 23.707 0.126 24.653 ;
     RECT  41.616 24.043 42.174 24.653 ;
     RECT  2.304 24.475 8.262 24.781 ;
     RECT  2.268 24.781 8.262 24.893 ;
     RECT  20.448 24.331 27.63 24.907 ;
     RECT  2.304 24.893 8.262 24.935 ;
     RECT  43.092 23.659 43.11 24.935 ;
     RECT  2.304 24.935 2.826 25.205 ;
     RECT  2.304 25.205 2.754 25.229 ;
     RECT  41.796 24.653 42.174 25.387 ;
     RECT  20.448 24.907 27.738 25.411 ;
     RECT  28.548 23.009 40.497 25.411 ;
     RECT  2.304 25.229 2.697 25.619 ;
     RECT  0.108 25.675 0.126 25.819 ;
     RECT  0.108 25.819 0.198 25.889 ;
     RECT  41.58 25.387 42.174 25.963 ;
     RECT  41.58 25.963 42.21 25.979 ;
     RECT  42.156 25.979 42.21 26.087 ;
     RECT  2.415 25.619 2.697 26.095 ;
     RECT  3.636 24.935 8.262 26.095 ;
     RECT  0.108 25.889 0.126 26.249 ;
     RECT  2.415 26.095 8.262 26.683 ;
     RECT  20.448 25.411 40.497 26.683 ;
     RECT  2.304 26.683 8.262 26.933 ;
     RECT  2.304 26.933 3.654 27.053 ;
     RECT  43.092 26.347 43.11 27.167 ;
     RECT  2.415 27.053 3.654 27.329 ;
     RECT  42.156 26.087 42.174 27.481 ;
     RECT  0.54 27.301 0.558 27.499 ;
     RECT  0.108 27.499 0.558 27.599 ;
     RECT  20.448 26.683 41.022 27.599 ;
     RECT  42.156 27.481 42.21 27.869 ;
     RECT  2.415 27.329 2.862 28.021 ;
     RECT  3.636 27.329 3.654 28.021 ;
     RECT  4.5 26.933 8.262 28.021 ;
     RECT  42.156 27.869 42.174 28.219 ;
     RECT  2.376 28.021 2.862 28.255 ;
     RECT  3.636 28.021 8.262 28.255 ;
     RECT  0.144 27.599 0.558 28.445 ;
     RECT  2.376 28.255 8.262 28.489 ;
     RECT  2.376 28.489 8.658 28.493 ;
     RECT  0.54 28.445 0.558 28.541 ;
     RECT  41.58 28.219 42.174 28.603 ;
     RECT  2.376 28.493 2.697 28.651 ;
     RECT  3.996 28.493 8.658 28.679 ;
     RECT  10.116 19.471 19.674 28.687 ;
     RECT  3.996 28.679 4.518 28.688 ;
     RECT  41.544 28.603 42.174 28.787 ;
     RECT  4.356 28.688 4.518 28.949 ;
     RECT  9.504 28.687 19.674 28.949 ;
     RECT  5.292 28.679 8.658 28.957 ;
     RECT  5.292 28.957 9.018 29.057 ;
     RECT  20.448 27.599 40.497 29.101 ;
     RECT  20.448 29.101 41.058 29.213 ;
     RECT  7.815 29.057 9.018 29.291 ;
     RECT  9 29.291 9.018 29.363 ;
     RECT  2.304 28.651 2.697 29.371 ;
     RECT  2.304 29.371 3.078 29.461 ;
     RECT  5.292 29.057 6.966 29.461 ;
     RECT  43.092 29.371 43.11 29.489 ;
     RECT  5.184 29.461 6.966 29.851 ;
     RECT  0.144 29.659 0.162 29.885 ;
     RECT  4.356 28.949 4.41 29.911 ;
     RECT  5.148 29.851 6.966 29.911 ;
     RECT  4.356 29.911 6.966 29.995 ;
     RECT  7.815 29.291 8.097 29.995 ;
     RECT  2.304 29.461 3.582 30.139 ;
     RECT  4.356 29.995 8.097 30.139 ;
     RECT  42.156 28.787 42.174 30.139 ;
     RECT  2.304 30.139 8.097 30.569 ;
     RECT  20.448 29.213 41.022 30.569 ;
     RECT  2.304 30.569 5.994 30.605 ;
     RECT  42.156 30.139 42.21 30.893 ;
     RECT  6.804 30.569 8.097 30.947 ;
     RECT  43.092 31.243 43.11 31.379 ;
     RECT  3.564 30.605 5.994 31.423 ;
     RECT  2.304 30.605 2.697 31.495 ;
     RECT  3.42 31.423 5.994 31.495 ;
     RECT  2.304 31.495 5.994 31.559 ;
     RECT  42.156 30.893 42.174 31.621 ;
     RECT  2.415 31.559 5.994 31.729 ;
     RECT  0.108 31.627 0.126 31.757 ;
     RECT  2.415 31.729 6.138 31.801 ;
     RECT  6.912 30.947 8.097 31.801 ;
     RECT  0.144 31.891 0.558 31.997 ;
     RECT  20.448 30.569 40.497 32.011 ;
     RECT  2.415 31.801 8.097 32.071 ;
     RECT  0.144 31.997 0.162 32.477 ;
     RECT  2.415 32.071 8.154 32.587 ;
     RECT  20.448 32.011 41.022 32.611 ;
     RECT  2.304 32.587 8.154 32.765 ;
     RECT  43.092 32.395 43.11 32.837 ;
     RECT  3.42 32.765 8.154 32.999 ;
     RECT  20.448 32.611 41.058 33.005 ;
     RECT  0.54 33.043 0.558 33.149 ;
     RECT  3.564 32.999 8.154 33.151 ;
     RECT  42.156 31.621 42.21 33.197 ;
     RECT  0.144 33.451 0.162 33.581 ;
     RECT  42.156 33.197 42.174 33.739 ;
     RECT  2.304 32.765 2.697 33.781 ;
     RECT  41.58 33.739 42.174 33.925 ;
     RECT  41.58 33.925 42.21 33.989 ;
     RECT  3.564 33.151 8.406 34.195 ;
     RECT  3.564 34.195 9.054 34.231 ;
     RECT  43.092 34.267 43.11 34.349 ;
     RECT  3.564 34.231 9.234 34.357 ;
     RECT  10.116 28.949 19.674 34.357 ;
     RECT  2.304 33.781 2.79 34.465 ;
     RECT  3.564 34.357 19.674 34.465 ;
     RECT  41.616 33.989 42.21 34.685 ;
     RECT  2.304 34.465 19.674 34.727 ;
     RECT  20.448 33.005 40.497 34.735 ;
     RECT  41.616 34.685 42.174 34.735 ;
     RECT  20.448 34.735 42.174 34.877 ;
     RECT  42.12 34.877 42.174 35.069 ;
     RECT  0.144 35.083 0.162 35.213 ;
     RECT  43.092 35.131 43.11 35.261 ;
     RECT  2.415 34.727 19.674 35.563 ;
     RECT  20.448 34.877 41.058 35.851 ;
     RECT  42.156 35.069 42.174 35.851 ;
     RECT  20.448 35.851 42.174 36.049 ;
     RECT  2.304 35.563 19.674 36.077 ;
     RECT  43.056 36.013 43.074 36.751 ;
     RECT  20.448 36.049 42.21 36.931 ;
     RECT  2.376 36.077 19.674 37.049 ;
     RECT  20.448 36.931 42.246 37.435 ;
     RECT  20.448 37.435 42.282 37.565 ;
     RECT  42.156 37.565 42.282 38.141 ;
     RECT  20.448 37.565 41.058 38.479 ;
     RECT  2.415 37.049 19.674 38.641 ;
     RECT  20.412 38.479 41.058 38.641 ;
     RECT  2.415 38.641 41.058 39.217 ;
     RECT  0.108 38.713 0.126 39.245 ;
     RECT  42.192 38.141 42.282 39.245 ;
     RECT  2.376 39.217 41.058 39.821 ;
     RECT  43.056 36.751 43.146 39.917 ;
     RECT  43.056 39.917 43.11 40.205 ;
     RECT  2.376 39.821 40.77 40.405 ;
     RECT  42.192 39.245 42.21 40.555 ;
     RECT  42.156 40.555 42.21 40.781 ;
     RECT  43.092 40.205 43.11 40.973 ;
     RECT  42.156 40.781 42.174 41.009 ;
     RECT  2.232 40.405 40.77 43.162 ;
     RECT  2.25 43.162 2.628 43.181 ;
     RECT  2.646 43.162 2.988 43.181 ;
     RECT  3.006 43.162 3.384 43.181 ;
     RECT  3.402 43.162 3.78 43.181 ;
     RECT  3.798 43.162 4.14 43.181 ;
     RECT  4.158 43.162 4.536 43.181 ;
     RECT  4.554 43.162 4.896 43.181 ;
     RECT  4.914 43.162 5.292 43.181 ;
     RECT  5.31 43.162 5.652 43.181 ;
     RECT  5.67 43.162 6.048 43.181 ;
     RECT  6.066 43.162 6.408 43.181 ;
     RECT  6.426 43.162 6.804 43.181 ;
     RECT  6.822 43.162 7.164 43.181 ;
     RECT  7.182 43.162 7.56 43.181 ;
     RECT  7.578 43.162 7.92 43.181 ;
     RECT  7.938 43.162 8.316 43.181 ;
     RECT  8.334 43.162 8.712 43.181 ;
     RECT  8.73 43.162 9.072 43.181 ;
     RECT  9.09 43.162 9.468 43.181 ;
     RECT  9.486 43.162 9.828 43.181 ;
     RECT  9.846 43.162 10.008 43.181 ;
     RECT  10.026 43.162 10.404 43.181 ;
     RECT  10.422 43.162 10.764 43.181 ;
     RECT  10.782 43.162 11.16 43.181 ;
     RECT  11.178 43.162 11.556 43.181 ;
     RECT  11.574 43.162 11.916 43.181 ;
     RECT  11.934 43.162 12.312 43.181 ;
     RECT  12.33 43.162 12.672 43.181 ;
     RECT  12.69 43.162 13.068 43.181 ;
     RECT  13.086 43.162 13.428 43.181 ;
     RECT  13.446 43.162 13.824 43.181 ;
     RECT  13.842 43.162 14.184 43.181 ;
     RECT  14.202 43.162 14.58 43.181 ;
     RECT  14.598 43.162 14.94 43.181 ;
     RECT  14.958 43.162 15.336 43.181 ;
     RECT  15.354 43.162 15.696 43.181 ;
     RECT  15.714 43.162 16.092 43.181 ;
     RECT  16.11 43.162 16.488 43.181 ;
     RECT  16.506 43.162 16.848 43.181 ;
     RECT  16.866 43.162 17.244 43.181 ;
     RECT  17.262 43.162 17.604 43.181 ;
     RECT  17.622 43.162 18 43.181 ;
     RECT  18.018 43.162 18.36 43.181 ;
     RECT  18.378 43.162 18.756 43.181 ;
     RECT  18.774 43.162 19.116 43.181 ;
     RECT  19.134 43.162 19.512 43.181 ;
     RECT  19.53 43.162 19.872 43.181 ;
     RECT  19.89 43.162 20.268 43.181 ;
     RECT  20.286 43.162 20.628 43.181 ;
     RECT  20.646 43.162 21.024 43.181 ;
     RECT  21.042 43.162 21.384 43.181 ;
     RECT  21.402 43.162 21.78 43.181 ;
     RECT  21.798 43.162 22.176 43.181 ;
     RECT  22.194 43.162 22.536 43.181 ;
     RECT  22.554 43.162 22.932 43.181 ;
     RECT  22.95 43.162 23.292 43.181 ;
     RECT  23.31 43.162 23.688 43.181 ;
     RECT  23.706 43.162 24.048 43.181 ;
     RECT  24.066 43.162 24.444 43.181 ;
     RECT  24.462 43.162 24.804 43.181 ;
     RECT  24.822 43.162 25.2 43.181 ;
     RECT  25.218 43.162 25.56 43.181 ;
     RECT  25.578 43.162 25.956 43.181 ;
     RECT  25.974 43.162 26.316 43.181 ;
     RECT  26.334 43.162 26.712 43.181 ;
     RECT  26.73 43.162 27.108 43.181 ;
     RECT  27.126 43.162 27.468 43.181 ;
     RECT  27.486 43.162 27.864 43.181 ;
     RECT  27.882 43.162 28.224 43.181 ;
     RECT  28.242 43.162 28.62 43.181 ;
     RECT  28.638 43.162 28.98 43.181 ;
     RECT  28.998 43.162 29.376 43.181 ;
     RECT  29.394 43.162 29.736 43.181 ;
     RECT  29.754 43.162 30.132 43.181 ;
     RECT  30.15 43.162 30.492 43.181 ;
     RECT  30.51 43.162 30.888 43.181 ;
     RECT  30.906 43.162 31.248 43.181 ;
     RECT  31.266 43.162 31.644 43.181 ;
     RECT  31.662 43.162 32.04 43.181 ;
     RECT  32.058 43.162 32.4 43.181 ;
     RECT  32.418 43.162 32.796 43.181 ;
     RECT  32.814 43.162 33.156 43.181 ;
     RECT  33.174 43.162 33.552 43.181 ;
     RECT  33.57 43.162 33.912 43.181 ;
     RECT  33.93 43.162 34.308 43.181 ;
     RECT  34.326 43.162 34.668 43.181 ;
     RECT  34.686 43.162 35.064 43.181 ;
     RECT  35.082 43.162 35.424 43.181 ;
     RECT  35.442 43.162 35.82 43.181 ;
     RECT  35.838 43.162 36.18 43.181 ;
     RECT  36.198 43.162 36.576 43.181 ;
     RECT  36.594 43.162 36.936 43.181 ;
     RECT  36.954 43.162 37.332 43.181 ;
     RECT  37.35 43.162 37.728 43.181 ;
     RECT  37.746 43.162 38.088 43.181 ;
     RECT  38.106 43.162 38.484 43.181 ;
     RECT  38.502 43.162 38.844 43.181 ;
     RECT  38.862 43.162 39.24 43.181 ;
     RECT  39.258 43.162 39.6 43.181 ;
     RECT  39.618 43.162 39.996 43.181 ;
     RECT  40.014 43.162 40.356 43.181 ;
     RECT  40.374 43.162 40.752 43.181 ;
    LAYER M4 ;
     RECT  0.084 2.208 2.365 2.232 ;
     RECT  0.06 2.232 2.365 2.4 ;
     RECT  0.084 2.4 2.365 2.424 ;
     RECT  0.06 2.424 2.365 2.544 ;
     RECT  0.084 2.544 2.365 2.568 ;
     RECT  0.06 2.568 2.365 2.736 ;
     RECT  0.084 2.736 2.365 2.76 ;
     RECT  0.06 2.76 2.365 2.88 ;
     RECT  0.084 2.88 2.365 2.904 ;
     RECT  0.06 2.904 2.365 3.072 ;
     RECT  0.084 3.072 2.365 3.096 ;
     RECT  0.06 3.096 2.365 3.216 ;
     RECT  0.084 3.216 2.365 3.24 ;
     RECT  0.06 3.24 2.365 3.408 ;
     RECT  0.084 3.408 2.365 3.432 ;
     RECT  0.06 3.432 2.365 3.552 ;
     RECT  0.084 3.552 2.365 3.576 ;
     RECT  0.06 3.576 2.365 3.744 ;
     RECT  0.084 3.744 2.365 3.768 ;
     RECT  0.06 3.768 2.365 3.888 ;
     RECT  0.084 3.888 2.365 3.912 ;
     RECT  0.06 3.912 2.365 4.08 ;
     RECT  0.084 4.08 2.365 4.104 ;
     RECT  0.06 4.104 2.365 4.224 ;
     RECT  0.084 4.224 2.365 4.248 ;
     RECT  0.06 4.248 2.365 4.416 ;
     RECT  0.084 4.416 2.365 4.44 ;
     RECT  0.06 4.44 2.365 4.56 ;
     RECT  0.084 4.56 2.365 4.584 ;
     RECT  0.06 4.584 2.365 4.752 ;
     RECT  0.084 4.752 2.365 4.776 ;
     RECT  0.06 4.776 2.365 4.896 ;
     RECT  0.084 4.896 2.365 4.92 ;
     RECT  0.06 4.92 2.365 5.088 ;
     RECT  0.084 5.088 2.365 5.112 ;
     RECT  0.06 5.112 2.365 5.232 ;
     RECT  0.084 5.232 2.365 5.256 ;
     RECT  0.06 5.256 2.365 5.424 ;
     RECT  0.084 5.424 2.365 5.448 ;
     RECT  0.06 5.448 2.365 5.568 ;
     RECT  0.084 5.568 2.365 5.592 ;
     RECT  0.06 5.592 2.365 5.712 ;
     RECT  0.084 5.712 2.365 5.736 ;
     RECT  0.06 5.736 2.365 5.904 ;
     RECT  0.084 5.904 2.365 5.928 ;
     RECT  0.06 5.928 2.365 6.048 ;
     RECT  0.084 6.048 2.365 6.072 ;
     RECT  0.06 6.072 2.365 6.24 ;
     RECT  0.084 6.24 2.365 6.264 ;
     RECT  0.06 6.264 2.365 6.384 ;
     RECT  0.084 6.384 2.365 6.408 ;
     RECT  0.06 6.408 2.365 6.576 ;
     RECT  0.084 6.576 2.365 6.6 ;
     RECT  0.06 6.6 2.365 6.72 ;
     RECT  0.084 6.72 2.365 6.744 ;
     RECT  0.06 6.744 2.365 6.912 ;
     RECT  0.084 6.912 2.365 6.936 ;
     RECT  0.06 6.936 2.365 7.056 ;
     RECT  0.084 7.056 2.365 7.08 ;
     RECT  0.06 7.08 2.365 7.248 ;
     RECT  0.084 7.248 2.365 7.272 ;
     RECT  0.06 7.272 2.365 7.392 ;
     RECT  0.084 7.392 2.365 7.416 ;
     RECT  0.06 7.416 2.365 7.584 ;
     RECT  0.084 7.584 2.365 7.608 ;
     RECT  0.06 7.608 2.365 7.728 ;
     RECT  0.084 7.728 2.365 7.752 ;
     RECT  0.06 7.752 2.365 7.92 ;
     RECT  0.084 7.92 2.365 7.944 ;
     RECT  0.06 7.944 2.365 8.064 ;
     RECT  0.084 8.064 2.365 8.088 ;
     RECT  0.06 8.088 2.365 8.256 ;
     RECT  0.084 8.256 2.365 8.28 ;
     RECT  0.06 8.28 2.365 8.4 ;
     RECT  0.084 8.4 2.365 8.424 ;
     RECT  0.06 8.424 2.365 8.592 ;
     RECT  0.084 8.592 2.365 8.616 ;
     RECT  0.06 8.616 2.365 8.736 ;
     RECT  0.084 8.736 2.365 8.76 ;
     RECT  0.06 8.76 2.365 8.928 ;
     RECT  0.084 8.928 2.365 8.952 ;
     RECT  0.06 8.952 2.365 9.072 ;
     RECT  0.084 9.072 2.365 9.096 ;
     RECT  0.06 9.096 2.365 9.216 ;
     RECT  0.084 9.216 2.365 9.24 ;
     RECT  0.06 9.24 2.365 9.408 ;
     RECT  0.084 9.408 2.365 9.432 ;
     RECT  0.06 9.432 2.365 9.552 ;
     RECT  0.084 9.552 2.365 9.576 ;
     RECT  0.06 9.576 2.365 9.744 ;
     RECT  0.084 9.744 2.365 9.768 ;
     RECT  0.06 9.768 2.365 9.888 ;
     RECT  0.084 9.888 2.365 9.912 ;
     RECT  0.06 9.912 2.365 10.08 ;
     RECT  0.084 10.08 2.365 10.104 ;
     RECT  0.06 10.104 2.365 10.224 ;
     RECT  0.084 10.224 2.365 10.248 ;
     RECT  0.06 10.248 2.365 10.368 ;
     RECT  0.084 10.368 2.365 10.392 ;
     RECT  0.06 10.392 2.365 10.56 ;
     RECT  0.084 10.56 2.365 10.584 ;
     RECT  0.06 10.584 2.365 10.704 ;
     RECT  0.084 10.704 2.365 10.728 ;
     RECT  0.06 10.728 2.365 10.896 ;
     RECT  0.084 10.896 2.365 10.92 ;
     RECT  0.06 10.92 2.365 11.04 ;
     RECT  0.084 11.04 2.365 11.064 ;
     RECT  0.06 11.064 2.365 11.232 ;
     RECT  0.084 11.232 2.365 11.256 ;
     RECT  0.06 11.256 2.365 11.376 ;
     RECT  0.084 11.376 2.365 11.4 ;
     RECT  0.06 11.4 2.365 11.52 ;
     RECT  0.084 11.52 2.365 11.544 ;
     RECT  0.06 11.544 2.365 11.712 ;
     RECT  0.084 11.712 2.365 11.736 ;
     RECT  0.06 11.736 2.365 11.856 ;
     RECT  0.084 11.856 2.365 11.88 ;
     RECT  0.06 11.88 2.365 12.048 ;
     RECT  0.084 12.048 2.365 12.072 ;
     RECT  0.06 12.072 2.365 12.192 ;
     RECT  0.084 12.192 2.365 12.216 ;
     RECT  0.06 12.216 2.365 12.384 ;
     RECT  0.084 12.384 2.365 12.408 ;
     RECT  0.06 12.408 2.365 12.528 ;
     RECT  0.084 12.528 2.365 12.552 ;
     RECT  0.06 12.552 2.365 12.672 ;
     RECT  0.084 12.672 2.365 12.696 ;
     RECT  0.06 12.696 2.365 12.864 ;
     RECT  0.084 12.864 2.365 12.888 ;
     RECT  0.06 12.888 2.365 13.008 ;
     RECT  0.084 13.008 2.365 13.032 ;
     RECT  0.06 13.032 2.365 13.2 ;
     RECT  0.084 13.2 2.365 13.224 ;
     RECT  0.06 13.224 2.365 13.344 ;
     RECT  0.084 13.344 2.365 13.368 ;
     RECT  0.06 13.368 2.365 13.536 ;
     RECT  0.084 13.536 2.365 13.56 ;
     RECT  0.06 13.56 2.365 13.68 ;
     RECT  0.084 13.68 2.365 13.704 ;
     RECT  0.06 13.704 2.365 13.824 ;
     RECT  0.084 13.824 2.365 13.848 ;
     RECT  0.06 13.848 2.365 14.016 ;
     RECT  0.084 14.016 2.365 14.04 ;
     RECT  0.06 14.04 2.365 14.16 ;
     RECT  0.084 14.16 2.365 14.184 ;
     RECT  0.06 14.184 2.365 14.352 ;
     RECT  0.084 14.352 2.365 14.376 ;
     RECT  0.06 14.376 2.365 14.496 ;
     RECT  0.084 14.496 2.365 14.52 ;
     RECT  0.06 14.52 2.365 14.688 ;
     RECT  0.084 14.688 2.365 14.712 ;
     RECT  0.06 14.712 2.365 14.832 ;
     RECT  0.084 14.832 2.365 14.856 ;
     RECT  0.06 14.856 2.365 14.976 ;
     RECT  0.084 14.976 2.365 15 ;
     RECT  0.06 15 2.365 15.168 ;
     RECT  0.084 15.168 2.365 15.192 ;
     RECT  0.06 15.192 2.365 15.312 ;
     RECT  0.084 15.312 2.365 15.336 ;
     RECT  0.06 15.336 2.365 15.504 ;
     RECT  0.084 15.504 2.365 15.528 ;
     RECT  0.06 15.528 2.365 15.648 ;
     RECT  0.084 15.648 2.365 15.672 ;
     RECT  0.06 15.672 2.365 15.84 ;
     RECT  0.084 15.84 2.365 15.864 ;
     RECT  0.06 15.864 2.365 15.984 ;
     RECT  0.084 15.984 2.365 16.008 ;
     RECT  0.06 16.008 2.365 16.128 ;
     RECT  0.084 16.128 2.365 16.152 ;
     RECT  0.06 16.152 2.365 16.32 ;
     RECT  0.084 16.32 2.365 16.344 ;
     RECT  0.06 16.344 2.365 16.464 ;
     RECT  0.084 16.464 2.365 16.488 ;
     RECT  0.06 16.488 2.365 16.656 ;
     RECT  0.084 16.656 2.365 16.68 ;
     RECT  0.06 16.68 2.365 16.8 ;
     RECT  0.084 16.8 2.365 16.824 ;
     RECT  0.06 16.824 2.365 16.992 ;
     RECT  0.084 16.992 2.365 17.016 ;
     RECT  0.06 17.016 2.365 17.136 ;
     RECT  0.084 17.136 2.365 17.16 ;
     RECT  0.06 17.16 2.365 17.28 ;
     RECT  0.084 17.28 2.365 17.304 ;
     RECT  0.06 17.304 2.365 17.472 ;
     RECT  0.084 17.472 2.365 17.496 ;
     RECT  0.06 17.496 2.365 17.616 ;
     RECT  0.084 17.616 2.365 17.64 ;
     RECT  0.06 17.64 2.365 17.808 ;
     RECT  0.084 17.808 2.365 17.832 ;
     RECT  0.06 17.832 2.365 17.952 ;
     RECT  0.084 17.952 2.365 17.976 ;
     RECT  0.06 17.976 2.365 18.144 ;
     RECT  0.084 18.144 2.365 18.168 ;
     RECT  0.06 18.168 2.365 18.288 ;
     RECT  0.084 18.288 2.365 18.312 ;
     RECT  0.06 18.312 2.365 18.432 ;
     RECT  0.084 18.432 2.365 18.456 ;
     RECT  0.06 18.456 2.365 18.624 ;
     RECT  0.084 18.624 2.365 18.648 ;
     RECT  0.06 18.648 2.365 18.768 ;
     RECT  0.084 18.768 2.365 18.792 ;
     RECT  0.06 18.792 2.365 18.96 ;
     RECT  0.084 18.96 2.365 18.984 ;
     RECT  0.06 18.984 2.365 19.104 ;
     RECT  0.084 19.104 2.365 19.128 ;
     RECT  0.06 19.128 2.365 19.296 ;
     RECT  0.084 19.296 2.365 19.32 ;
     RECT  0.06 19.32 2.365 19.44 ;
     RECT  0.084 19.44 2.365 19.464 ;
     RECT  0.06 19.464 2.365 19.584 ;
     RECT  0.084 19.584 2.365 19.608 ;
     RECT  0.06 19.608 2.365 19.776 ;
     RECT  0.084 19.776 2.365 19.8 ;
     RECT  0.06 19.8 2.365 19.92 ;
     RECT  0.084 19.92 2.365 19.944 ;
     RECT  0.06 19.944 2.365 20.112 ;
     RECT  0.084 20.112 2.365 20.136 ;
     RECT  0.06 20.136 2.365 20.256 ;
     RECT  0.084 20.256 2.365 20.28 ;
     RECT  0.06 20.28 2.365 20.448 ;
     RECT  0.084 20.448 2.365 20.472 ;
     RECT  0.06 20.472 2.365 20.592 ;
     RECT  0.084 20.592 2.365 20.616 ;
     RECT  0.06 20.616 2.365 20.736 ;
     RECT  0.084 20.736 2.365 20.76 ;
     RECT  0.06 20.76 2.365 20.928 ;
     RECT  0.084 20.928 2.365 20.952 ;
     RECT  0.06 20.952 2.365 21.072 ;
     RECT  0.084 21.072 2.365 21.096 ;
     RECT  0.06 21.096 2.365 21.264 ;
     RECT  0.084 21.264 2.365 21.288 ;
     RECT  0.06 21.288 2.365 21.408 ;
     RECT  0.084 21.408 2.365 21.432 ;
     RECT  0.06 21.432 2.365 21.6 ;
     RECT  0.084 21.6 2.365 21.624 ;
     RECT  0.06 21.624 2.365 21.744 ;
     RECT  0.084 21.744 2.365 21.768 ;
     RECT  0.06 21.768 2.365 21.936 ;
     RECT  0.084 21.936 2.365 21.96 ;
     RECT  0.06 21.96 2.365 22.08 ;
     RECT  0.084 22.08 2.365 22.104 ;
     RECT  0.06 22.104 2.365 22.224 ;
     RECT  0.084 22.224 2.365 22.248 ;
     RECT  0.06 22.248 2.365 22.416 ;
     RECT  0.084 22.416 2.365 22.44 ;
     RECT  0.06 22.44 2.365 22.56 ;
     RECT  0.084 22.56 2.365 22.584 ;
     RECT  0.06 22.584 2.365 22.752 ;
     RECT  0.084 22.752 2.365 22.776 ;
     RECT  0.06 22.776 2.365 22.896 ;
     RECT  0.084 22.896 2.365 22.92 ;
     RECT  0.06 22.92 2.365 23.088 ;
     RECT  0.084 23.088 2.365 23.112 ;
     RECT  0.06 23.112 2.365 23.232 ;
     RECT  0.084 23.232 2.365 23.256 ;
     RECT  0.06 23.256 2.365 23.376 ;
     RECT  0.084 23.376 2.365 23.4 ;
     RECT  0.06 23.4 2.365 23.568 ;
     RECT  0.084 23.568 2.365 23.592 ;
     RECT  0.06 23.592 2.365 23.712 ;
     RECT  0.084 23.712 2.365 23.736 ;
     RECT  0.06 23.736 2.365 23.904 ;
     RECT  0.084 23.904 2.365 23.928 ;
     RECT  0.06 23.928 2.365 24.048 ;
     RECT  0.084 24.048 2.365 24.072 ;
     RECT  0.06 24.072 2.365 24.24 ;
     RECT  0.084 24.24 2.365 24.264 ;
     RECT  0.06 24.264 2.365 24.384 ;
     RECT  0.084 24.384 2.365 24.408 ;
     RECT  0.06 24.408 2.365 24.528 ;
     RECT  0.084 24.528 2.365 24.552 ;
     RECT  0.06 24.552 2.365 24.72 ;
     RECT  0.084 24.72 2.365 24.744 ;
     RECT  0.06 24.744 2.365 24.864 ;
     RECT  0.084 24.864 2.365 24.888 ;
     RECT  0.06 24.888 2.365 25.056 ;
     RECT  0.084 25.056 2.365 25.08 ;
     RECT  0.06 25.08 2.365 25.2 ;
     RECT  0.084 25.2 2.365 25.224 ;
     RECT  0.06 25.224 2.365 25.392 ;
     RECT  0.084 25.392 2.365 25.416 ;
     RECT  0.06 25.416 2.365 25.536 ;
     RECT  0.084 25.536 2.365 25.56 ;
     RECT  0.06 25.56 2.365 25.68 ;
     RECT  0.084 25.68 2.365 25.704 ;
     RECT  0.06 25.704 2.365 25.872 ;
     RECT  0.084 25.872 2.365 25.896 ;
     RECT  0.06 25.896 2.365 26.016 ;
     RECT  0.084 26.016 2.365 26.04 ;
     RECT  0.06 26.04 2.365 26.208 ;
     RECT  0.084 26.208 2.365 26.232 ;
     RECT  0.06 26.232 2.365 26.352 ;
     RECT  0.084 26.352 2.365 26.376 ;
     RECT  0.06 26.376 2.365 26.544 ;
     RECT  0.084 26.544 2.365 26.568 ;
     RECT  0.06 26.568 2.365 26.688 ;
     RECT  0.084 26.688 2.365 26.712 ;
     RECT  0.06 26.712 2.365 26.832 ;
     RECT  0.084 26.832 2.365 26.856 ;
     RECT  0.06 26.856 2.365 27.024 ;
     RECT  0.084 27.024 2.365 27.048 ;
     RECT  0.06 27.048 2.365 27.168 ;
     RECT  0.084 27.168 2.365 27.192 ;
     RECT  0.06 27.192 2.365 27.36 ;
     RECT  0.084 27.36 2.365 27.384 ;
     RECT  0.06 27.384 2.365 27.504 ;
     RECT  0.084 27.504 2.365 27.528 ;
     RECT  0.06 27.528 2.365 27.696 ;
     RECT  0.084 27.696 2.365 27.72 ;
     RECT  0.06 27.72 2.365 27.84 ;
     RECT  0.084 27.84 2.365 27.864 ;
     RECT  0.06 27.864 2.365 27.984 ;
     RECT  0.084 27.984 2.365 28.008 ;
     RECT  0.06 28.008 2.365 28.176 ;
     RECT  0.084 28.176 2.365 28.2 ;
     RECT  0.06 28.2 2.365 28.32 ;
     RECT  0.084 28.32 2.365 28.344 ;
     RECT  0.06 28.344 2.365 28.512 ;
     RECT  0.084 28.512 2.365 28.536 ;
     RECT  0.06 28.536 2.365 28.656 ;
     RECT  0.084 28.656 2.365 28.68 ;
     RECT  0.06 28.68 2.365 28.848 ;
     RECT  0.084 28.848 2.365 28.872 ;
     RECT  0.06 28.872 2.365 28.992 ;
     RECT  0.084 28.992 2.365 29.016 ;
     RECT  0.06 29.016 2.365 29.136 ;
     RECT  0.084 29.136 2.365 29.16 ;
     RECT  0.06 29.16 2.365 29.328 ;
     RECT  0.084 29.328 2.365 29.352 ;
     RECT  0.06 29.352 2.365 29.472 ;
     RECT  0.084 29.472 2.365 29.496 ;
     RECT  0.06 29.496 2.365 29.664 ;
     RECT  0.084 29.664 2.365 29.688 ;
     RECT  0.06 29.688 2.365 29.808 ;
     RECT  0.084 29.808 2.365 29.832 ;
     RECT  0.06 29.832 2.365 30 ;
     RECT  0.084 30 2.365 30.024 ;
     RECT  0.06 30.024 2.365 30.144 ;
     RECT  0.084 30.144 2.365 30.168 ;
     RECT  0.06 30.168 2.365 30.288 ;
     RECT  0.084 30.288 2.365 30.312 ;
     RECT  0.06 30.312 2.365 30.48 ;
     RECT  0.084 30.48 2.365 30.504 ;
     RECT  0.06 30.504 2.365 30.624 ;
     RECT  0.084 30.624 2.365 30.648 ;
     RECT  0.06 30.648 2.365 30.816 ;
     RECT  0.084 30.816 2.365 30.84 ;
     RECT  0.06 30.84 2.365 30.96 ;
     RECT  0.084 30.96 2.365 30.984 ;
     RECT  0.06 30.984 2.365 31.152 ;
     RECT  0.084 31.152 2.365 31.176 ;
     RECT  0.06 31.176 2.365 31.296 ;
     RECT  0.084 31.296 2.365 31.32 ;
     RECT  0.06 31.32 2.365 31.44 ;
     RECT  0.084 31.44 2.365 31.464 ;
     RECT  0.06 31.464 2.365 31.632 ;
     RECT  0.084 31.632 2.365 31.656 ;
     RECT  0.06 31.656 2.365 31.776 ;
     RECT  0.084 31.776 2.365 31.8 ;
     RECT  0.06 31.8 2.365 31.968 ;
     RECT  0.084 31.968 2.365 31.992 ;
     RECT  0.06 31.992 2.365 32.112 ;
     RECT  0.084 32.112 2.365 32.136 ;
     RECT  0.06 32.136 2.365 32.304 ;
     RECT  0.084 32.304 2.365 32.328 ;
     RECT  0.06 32.328 2.365 32.448 ;
     RECT  0.084 32.448 2.365 32.472 ;
     RECT  0.06 32.472 2.365 32.592 ;
     RECT  0.084 32.592 2.365 32.616 ;
     RECT  0.06 32.616 2.365 32.784 ;
     RECT  0.084 32.784 2.365 32.808 ;
     RECT  0.06 32.808 2.365 32.928 ;
     RECT  0.084 32.928 2.365 32.952 ;
     RECT  0.06 32.952 2.365 33.12 ;
     RECT  0.084 33.12 2.365 33.144 ;
     RECT  0.06 33.144 2.365 33.264 ;
     RECT  0.084 33.264 2.365 33.288 ;
     RECT  0.06 33.288 2.365 33.456 ;
     RECT  0.084 33.456 2.365 33.48 ;
     RECT  0.06 33.48 2.365 33.6 ;
     RECT  0.084 33.6 2.365 33.624 ;
     RECT  0.06 33.624 2.365 33.744 ;
     RECT  0.084 33.744 2.365 33.768 ;
     RECT  0.06 33.768 2.365 33.936 ;
     RECT  0.084 33.936 2.365 33.96 ;
     RECT  0.06 33.96 2.365 34.08 ;
     RECT  0.084 34.08 2.365 34.104 ;
     RECT  0.06 34.104 2.365 34.272 ;
     RECT  0.084 34.272 2.365 34.296 ;
     RECT  0.06 34.296 2.365 34.416 ;
     RECT  0.084 34.416 2.365 34.44 ;
     RECT  0.06 34.44 2.365 34.608 ;
     RECT  0.084 34.608 2.365 34.632 ;
     RECT  0.06 34.632 2.365 34.752 ;
     RECT  0.084 34.752 2.365 34.776 ;
     RECT  0.06 34.776 2.365 34.896 ;
     RECT  0.084 34.896 2.365 34.92 ;
     RECT  0.06 34.92 2.365 35.088 ;
     RECT  0.084 35.088 2.365 35.112 ;
     RECT  0.06 35.112 2.365 35.232 ;
     RECT  0.084 35.232 2.365 35.256 ;
     RECT  0.06 35.256 2.365 35.424 ;
     RECT  0.084 35.424 2.365 35.448 ;
     RECT  0.06 35.448 2.365 35.568 ;
     RECT  0.084 35.568 2.365 35.592 ;
     RECT  0.06 35.592 2.365 35.76 ;
     RECT  0.084 35.76 2.365 35.784 ;
     RECT  0.06 35.784 2.365 35.904 ;
     RECT  0.084 35.904 2.365 35.928 ;
     RECT  2.365 2.016 2.408 35.928 ;
     RECT  2.365 41.184 2.408 41.208 ;
     RECT  2.408 2.016 2.483 41.208 ;
     RECT  2.483 2.148 2.512 41.052 ;
     RECT  2.512 2.208 2.704 41.016 ;
     RECT  2.704 37.584 2.915 38.232 ;
     RECT  2.915 37.584 2.953 37.896 ;
     RECT  2.704 2.208 3.841 35.784 ;
     RECT  2.704 39.744 4.201 41.016 ;
     RECT  4.201 39.6 4.237 41.016 ;
     RECT  3.841 2.112 4.277 35.784 ;
     RECT  2.953 37.872 4.421 37.896 ;
     RECT  4.277 33.408 4.493 35.784 ;
     RECT  4.277 2.112 4.693 32.328 ;
     RECT  4.885 38.112 4.921 38.136 ;
     RECT  4.237 39.312 4.921 41.016 ;
     RECT  4.493 33.6 5.177 35.784 ;
     RECT  5.177 33.792 5.213 35.784 ;
     RECT  4.693 1.728 5.609 32.328 ;
     RECT  5.609 2.256 5.645 32.328 ;
     RECT  5.645 9.024 5.681 32.328 ;
     RECT  5.681 9.024 5.717 32.28 ;
     RECT  5.213 34.896 5.717 35.784 ;
     RECT  5.717 9.024 5.725 27.864 ;
     RECT  5.677 43.056 5.891 43.08 ;
     RECT  5.645 2.256 6.613 7.896 ;
     RECT  5.725 23.904 6.685 27.864 ;
     RECT  5.717 29.088 6.685 32.28 ;
     RECT  6.613 1.728 6.709 7.896 ;
     RECT  5.725 9.024 6.709 22.584 ;
     RECT  6.709 1.728 6.761 22.584 ;
     RECT  6.761 2.832 6.796 22.584 ;
     RECT  6.796 9.648 6.853 22.584 ;
     RECT  5.213 33.792 7.055 33.816 ;
     RECT  5.717 35.184 7.055 35.784 ;
     RECT  7.055 33.792 7.093 35.784 ;
     RECT  7.189 0.096 7.379 0.12 ;
     RECT  4.921 38.112 7.685 41.016 ;
     RECT  7.685 38.112 7.693 41.16 ;
     RECT  6.761 1.728 7.808 1.752 ;
     RECT  6.796 2.832 7.808 8.328 ;
     RECT  6.853 9.648 7.808 22.824 ;
     RECT  6.685 23.904 7.808 32.28 ;
     RECT  7.093 33.456 7.808 35.784 ;
     RECT  7.693 38.112 7.808 41.256 ;
     RECT  7.808 1.728 8.104 41.256 ;
     RECT  8.104 37.968 8.147 41.256 ;
     RECT  8.104 15.312 8.237 15.336 ;
     RECT  8.104 34.656 8.237 35.832 ;
     RECT  8.104 17.328 8.243 19.512 ;
     RECT  8.243 19.392 8.245 19.512 ;
     RECT  8.104 21.408 8.273 21.624 ;
     RECT  8.237 35.52 8.273 35.832 ;
     RECT  8.273 35.808 8.291 35.832 ;
     RECT  8.147 37.968 9.539 41.016 ;
     RECT  8.104 1.728 9.596 1.752 ;
     RECT  8.104 2.832 9.596 7.752 ;
     RECT  9.596 1.728 10.163 7.752 ;
     RECT  8.273 21.6 10.825 21.624 ;
     RECT  10.825 21.504 10.865 21.624 ;
     RECT  9.539 38.112 10.933 41.016 ;
     RECT  10.163 1.728 11.317 1.752 ;
     RECT  10.933 38.064 11.765 41.016 ;
     RECT  11.765 38.064 12.089 40.632 ;
     RECT  11.317 1.728 12.469 1.8 ;
     RECT  12.077 42.144 13.025 42.168 ;
     RECT  12.469 1.728 13.208 1.848 ;
     RECT  10.163 2.832 13.208 7.752 ;
     RECT  8.243 17.328 13.208 17.496 ;
     RECT  8.245 19.488 13.208 19.512 ;
     RECT  10.865 21.504 13.208 21.528 ;
     RECT  8.104 26.544 13.208 26.568 ;
     RECT  12.089 38.112 13.208 40.632 ;
     RECT  13.208 1.728 13.237 41.052 ;
     RECT  13.237 1.728 13.421 41.208 ;
     RECT  13.421 1.728 13.504 41.016 ;
     RECT  13.504 1.728 14.285 1.8 ;
     RECT  14.389 0.096 14.753 0.12 ;
     RECT  13.504 17.328 14.821 17.496 ;
     RECT  13.504 21.6 14.821 21.624 ;
     RECT  13.504 38.112 14.825 41.016 ;
     RECT  14.821 21.504 14.861 21.624 ;
     RECT  14.857 11.76 15.109 11.784 ;
     RECT  15.109 11.424 15.193 11.784 ;
     RECT  14.389 42.144 15.689 42.168 ;
     RECT  14.825 38.112 15.857 40.44 ;
     RECT  14.285 1.728 15.941 1.752 ;
     RECT  13.504 2.832 16.081 7.752 ;
     RECT  15.937 31.728 16.124 31.752 ;
     RECT  16.124 31.728 16.211 31.896 ;
     RECT  15.857 38.112 16.261 41.016 ;
     RECT  16.261 38.112 16.409 41.592 ;
     RECT  16.409 38.112 16.733 41.016 ;
     RECT  16.081 2.256 17.075 7.752 ;
     RECT  17.413 1.728 17.561 1.752 ;
     RECT  17.413 42.144 17.921 42.168 ;
     RECT  16.733 38.112 18.161 40.488 ;
     RECT  17.075 2.832 18.181 7.752 ;
     RECT  18.161 38.112 18.493 41.016 ;
     RECT  18.181 2.016 18.608 7.752 ;
     RECT  15.193 11.76 18.608 11.784 ;
     RECT  14.821 17.184 18.608 17.496 ;
     RECT  13.504 19.488 18.608 19.512 ;
     RECT  14.861 21.504 18.608 21.528 ;
     RECT  13.504 26.544 18.608 26.568 ;
     RECT  16.211 31.728 18.608 31.752 ;
     RECT  18.493 38.112 18.608 41.208 ;
     RECT  18.608 2.016 18.611 41.208 ;
     RECT  18.611 2.016 18.712 41.052 ;
     RECT  18.712 2.016 18.904 41.016 ;
     RECT  16.645 0.096 19.037 0.12 ;
     RECT  18.904 17.184 19.091 17.496 ;
     RECT  18.904 5.472 19.505 8.52 ;
     RECT  19.091 17.472 19.667 17.496 ;
     RECT  19.505 7.632 20.003 8.52 ;
     RECT  18.901 42.144 20.189 42.168 ;
     RECT  19.277 1.728 20.429 1.752 ;
     RECT  20.429 1.728 20.513 1.848 ;
     RECT  21.205 0.096 21.305 0.12 ;
     RECT  18.904 38.16 21.341 41.016 ;
     RECT  21.341 38.16 21.485 40.968 ;
     RECT  18.904 2.832 21.553 4.44 ;
     RECT  19.505 5.472 21.553 6.6 ;
     RECT  18.904 11.76 22.021 11.784 ;
     RECT  22.021 11.232 22.067 11.784 ;
     RECT  18.904 21.6 22.163 21.624 ;
     RECT  20.513 1.728 22.337 1.752 ;
     RECT  22.337 1.728 22.421 1.8 ;
     RECT  18.904 19.488 22.499 19.512 ;
     RECT  21.485 38.16 22.693 40.392 ;
     RECT  22.661 0.096 22.745 0.12 ;
     RECT  21.553 2.832 22.745 6.6 ;
     RECT  21.973 42.144 23.213 42.168 ;
     RECT  22.421 1.728 23.813 1.752 ;
     RECT  23.813 1.728 24.008 1.8 ;
     RECT  22.745 2.832 24.008 6.072 ;
     RECT  20.003 7.632 24.008 8.184 ;
     RECT  22.067 11.232 24.008 11.256 ;
     RECT  18.904 26.544 24.008 26.568 ;
     RECT  18.904 31.728 24.008 31.752 ;
     RECT  22.693 38.16 24.008 41.016 ;
     RECT  24.008 1.728 24.209 41.052 ;
     RECT  24.209 1.728 24.293 41.16 ;
     RECT  24.293 1.728 24.304 41.016 ;
     RECT  24.304 37.584 25.381 41.016 ;
     RECT  24.613 42.144 25.381 42.168 ;
     RECT  25.381 37.584 25.481 42.168 ;
     RECT  25.481 42.144 25.849 42.168 ;
     RECT  24.304 11.232 26.345 11.256 ;
     RECT  25.481 37.584 26.444 41.016 ;
     RECT  26.444 37.584 26.531 41.64 ;
     RECT  26.437 10.848 26.561 10.872 ;
     RECT  26.531 37.584 26.627 41.016 ;
     RECT  24.304 31.728 27.497 31.752 ;
     RECT  26.627 38.112 28.115 41.016 ;
     RECT  28.033 31.872 28.117 31.896 ;
     RECT  24.304 1.728 29.408 6.072 ;
     RECT  24.304 7.632 29.408 8.184 ;
     RECT  24.304 26.544 29.408 26.568 ;
     RECT  28.115 38.16 29.408 41.016 ;
     RECT  29.408 1.728 29.512 41.052 ;
     RECT  29.512 1.728 29.621 41.016 ;
     RECT  29.545 42.144 29.629 42.168 ;
     RECT  29.621 2.418 29.704 41.016 ;
     RECT  29.704 2.496 29.765 6.072 ;
     RECT  29.933 0.096 30.485 0.12 ;
     RECT  29.704 26.544 30.515 26.568 ;
     RECT  29.704 31.152 30.515 31.32 ;
     RECT  30.62 0.528 30.707 0.552 ;
     RECT  29.765 2.496 30.733 4.488 ;
     RECT  29.765 5.472 30.733 6.072 ;
     RECT  29.704 38.208 30.769 41.016 ;
     RECT  30.733 2.496 31.045 6.072 ;
     RECT  30.769 38.112 31.897 41.016 ;
     RECT  31.897 38.112 31.925 40.968 ;
     RECT  31.925 38.112 33.061 40.584 ;
     RECT  32.165 42.144 33.692 42.168 ;
     RECT  33.692 42.144 33.779 42.216 ;
     RECT  30.515 31.152 33.937 31.176 ;
     RECT  33.061 37.92 34.153 40.584 ;
     RECT  34.009 41.616 34.163 41.64 ;
     RECT  31.045 1.728 34.193 6.072 ;
     RECT  34.153 37.056 34.513 40.584 ;
     RECT  34.453 0.576 34.729 0.6 ;
     RECT  34.729 0.096 34.733 0.6 ;
     RECT  34.193 2.148 34.765 6.072 ;
     RECT  29.704 7.632 34.765 8.184 ;
     RECT  34.765 2.148 34.808 8.184 ;
     RECT  33.937 11.136 34.808 11.16 ;
     RECT  33.937 14.256 34.808 14.28 ;
     RECT  33.937 16.896 34.808 16.92 ;
     RECT  34.765 22.8 34.808 22.824 ;
     RECT  33.937 26.256 34.808 26.28 ;
     RECT  33.937 31.152 34.808 31.224 ;
     RECT  34.261 33.312 34.808 33.336 ;
     RECT  34.513 37.056 34.808 41.052 ;
     RECT  34.433 43.056 34.883 43.08 ;
     RECT  34.808 2.148 34.912 41.052 ;
     RECT  34.912 2.304 35.104 41.016 ;
     RECT  35.104 25.68 35.201 26.28 ;
     RECT  35.104 34.752 35.219 36.168 ;
     RECT  35.104 30.528 35.237 31.224 ;
     RECT  34.765 1.104 35.267 1.128 ;
     RECT  35.104 10.896 35.267 11.928 ;
     RECT  35.104 12.96 35.273 13.56 ;
     RECT  35.273 12.96 35.281 13.224 ;
     RECT  35.104 37.2 35.345 41.016 ;
     RECT  35.267 11.136 35.381 11.928 ;
     RECT  35.104 15.744 35.381 17.016 ;
     RECT  35.381 11.136 35.411 11.352 ;
     RECT  35.104 22.128 35.597 24.36 ;
     RECT  35.411 11.136 35.669 11.16 ;
     RECT  35.597 22.128 35.891 23.448 ;
     RECT  34.733 0.096 35.989 0.12 ;
     RECT  35.104 19.008 35.993 19.992 ;
     RECT  35.891 23.424 36.029 23.448 ;
     RECT  35.773 42.192 36.035 42.216 ;
     RECT  35.989 0.096 36.073 0.6 ;
     RECT  35.104 2.304 36.101 9.72 ;
     RECT  35.891 22.128 36.133 22.2 ;
     RECT  35.381 16.992 36.137 17.016 ;
     RECT  36.101 2.304 36.173 8.184 ;
     RECT  35.993 19.392 36.181 19.992 ;
     RECT  36.133 21.504 36.181 22.2 ;
     RECT  35.381 15.744 36.281 16.008 ;
     RECT  35.104 18 36.281 18.024 ;
     RECT  35.219 34.8 36.281 35.448 ;
     RECT  35.345 37.2 36.373 40.824 ;
     RECT  36.281 15.984 36.421 16.008 ;
     RECT  35.237 30.528 36.457 31.176 ;
     RECT  36.421 15.984 36.467 16.488 ;
     RECT  36.181 19.392 36.467 22.2 ;
     RECT  36.313 13.104 36.493 13.128 ;
     RECT  35.201 25.68 36.493 25.704 ;
     RECT  36.493 12.528 36.497 13.128 ;
     RECT  36.467 19.776 36.497 22.2 ;
     RECT  36.373 37.2 36.497 40.968 ;
     RECT  36.101 9.36 36.529 9.72 ;
     RECT  36.497 12.528 36.637 12.552 ;
     RECT  36.497 37.2 36.781 40.824 ;
     RECT  36.757 43.056 36.893 43.08 ;
     RECT  36.497 19.776 36.921 19.8 ;
     RECT  36.637 11.856 37.037 12.552 ;
     RECT  36.457 30.528 37.043 31.944 ;
     RECT  36.457 34.608 37.043 34.728 ;
     RECT  37.043 31.152 37.073 31.944 ;
     RECT  37.043 34.608 37.073 34.632 ;
     RECT  36.493 14.448 37.177 14.472 ;
     RECT  36.467 16.416 37.217 16.488 ;
     RECT  37.141 42.144 37.253 42.168 ;
     RECT  37.177 14.448 37.261 14.856 ;
     RECT  36.173 2.544 37.285 8.184 ;
     RECT  36.529 9.36 37.285 9.864 ;
     RECT  36.073 0.096 37.288 0.12 ;
     RECT  37.037 12 37.361 12.552 ;
     RECT  37.288 0.048 37.379 0.12 ;
     RECT  37.285 2.544 37.427 9.864 ;
     RECT  37.427 2.544 37.433 2.808 ;
     RECT  37.427 3.792 37.433 9.864 ;
     RECT  36.497 22.128 37.525 22.2 ;
     RECT  37.217 16.416 37.649 16.44 ;
     RECT  37.433 3.792 37.721 8.424 ;
     RECT  37.261 14.448 37.753 14.472 ;
     RECT  37.433 9.6 37.789 9.864 ;
     RECT  37.753 14.208 37.793 14.472 ;
     RECT  37.573 23.328 37.829 23.352 ;
     RECT  36.277 27.312 37.829 27.336 ;
     RECT  37.379 0.096 37.889 0.12 ;
     RECT  37.721 3.792 37.901 8.328 ;
     RECT  37.889 0.096 38.045 0.168 ;
     RECT  36.493 25.68 38.081 25.992 ;
     RECT  38.041 34.608 38.225 34.632 ;
     RECT  36.781 36.864 38.245 40.824 ;
     RECT  37.793 14.208 38.257 14.232 ;
     RECT  37.909 35.856 38.293 35.88 ;
     RECT  38.213 0.576 38.297 0.6 ;
     RECT  38.257 13.632 38.297 14.232 ;
     RECT  38.293 35.28 38.369 35.88 ;
     RECT  38.245 36.864 38.405 41.592 ;
     RECT  37.433 2.592 38.437 2.808 ;
     RECT  37.789 9.6 38.509 10.584 ;
     RECT  38.437 2.256 38.675 2.808 ;
     RECT  38.581 42.144 38.675 42.168 ;
     RECT  37.901 8.304 38.725 8.328 ;
     RECT  38.509 9.312 38.725 10.584 ;
     RECT  37.901 3.792 38.771 7.32 ;
     RECT  38.725 8.304 38.771 10.584 ;
     RECT  37.789 28.32 38.821 28.344 ;
     RECT  38.821 28.32 38.867 29.208 ;
     RECT  38.297 13.632 38.873 13.656 ;
     RECT  38.365 16.464 38.873 16.488 ;
     RECT  37.525 21.936 38.873 22.2 ;
     RECT  38.867 29.184 38.908 29.208 ;
     RECT  38.081 25.968 38.909 25.992 ;
     RECT  37.573 33.072 38.909 33.096 ;
     RECT  38.828 18.192 38.915 18.216 ;
     RECT  37.573 19.92 38.973 19.944 ;
     RECT  38.873 21.936 39.053 21.96 ;
     RECT  37.073 31.152 39.053 31.176 ;
     RECT  38.771 8.304 39.059 9.672 ;
     RECT  39.013 19.392 39.097 19.416 ;
     RECT  39.013 0.096 39.365 0.12 ;
     RECT  38.675 2.304 39.373 2.808 ;
     RECT  38.771 3.792 39.373 7.08 ;
     RECT  38.405 36.864 39.397 40.968 ;
     RECT  38.369 35.28 39.409 35.304 ;
     RECT  39.365 0.096 39.449 0.168 ;
     RECT  39.409 34.848 39.481 35.304 ;
     RECT  39.449 0.096 39.557 0.12 ;
     RECT  39.481 34.848 39.589 35.352 ;
     RECT  39.397 36.864 39.661 41.592 ;
     RECT  39.661 36.816 39.737 41.592 ;
     RECT  39.373 2.304 39.769 7.08 ;
     RECT  39.769 2.256 39.781 7.08 ;
     RECT  39.737 36.816 39.805 41.208 ;
     RECT  39.781 1.728 39.917 7.08 ;
     RECT  39.917 2.148 40.208 7.08 ;
     RECT  39.059 8.688 40.208 9.672 ;
     RECT  40.165 33.552 40.208 33.576 ;
     RECT  39.589 34.8 40.208 35.352 ;
     RECT  39.805 36.576 40.208 41.208 ;
     RECT  40.057 1.104 40.211 1.128 ;
     RECT  40.208 2.148 40.312 41.208 ;
     RECT  40.312 2.352 40.385 41.208 ;
     RECT  40.385 2.352 40.504 41.16 ;
     RECT  40.549 0.096 40.637 0.12 ;
     RECT  40.504 2.352 40.673 6.648 ;
     RECT  40.504 35.616 40.745 41.16 ;
     RECT  40.504 28.992 41.533 30.504 ;
     RECT  40.673 2.448 41.569 6.648 ;
     RECT  40.504 7.92 41.569 7.944 ;
     RECT  40.504 10.032 41.569 14.808 ;
     RECT  40.504 16.848 41.569 17.64 ;
     RECT  40.504 19.104 41.569 19.128 ;
     RECT  40.504 21.024 41.569 21.432 ;
     RECT  40.504 22.896 41.569 22.92 ;
     RECT  40.504 26.688 41.569 27.48 ;
     RECT  41.533 28.608 41.569 30.504 ;
     RECT  40.504 32.016 41.569 33.576 ;
     RECT  41.569 20.64 41.605 21.432 ;
     RECT  41.569 22.56 41.605 23.496 ;
     RECT  41.569 25.392 41.605 30.504 ;
     RECT  40.745 35.616 41.605 40.392 ;
     RECT  41.569 2.448 42.109 14.808 ;
     RECT  41.569 16.08 42.109 19.128 ;
     RECT  42.109 2.448 42.145 19.128 ;
     RECT  41.605 20.64 42.145 30.504 ;
     RECT  41.569 32.016 42.145 33.768 ;
     RECT  41.605 34.848 42.145 40.392 ;
     RECT  42.145 2.448 42.181 40.584 ;
     RECT  42.181 2.448 43.081 40.776 ;
     RECT  43.081 2.256 43.116 2.28 ;
     RECT  43.081 2.28 43.164 2.448 ;
     RECT  43.081 2.448 43.116 2.472 ;
     RECT  43.081 2.472 43.164 2.64 ;
     RECT  43.081 2.64 43.116 2.664 ;
     RECT  43.081 2.664 43.164 2.832 ;
     RECT  43.081 2.832 43.116 2.856 ;
     RECT  43.081 2.856 43.164 3.024 ;
     RECT  43.081 3.024 43.116 3.048 ;
     RECT  43.081 3.048 43.164 3.168 ;
     RECT  43.081 3.168 43.116 3.192 ;
     RECT  43.081 3.192 43.164 3.36 ;
     RECT  43.081 3.36 43.116 3.384 ;
     RECT  43.081 3.384 43.164 3.552 ;
     RECT  43.081 3.552 43.116 3.576 ;
     RECT  43.081 3.576 43.164 3.744 ;
     RECT  43.081 3.744 43.116 3.768 ;
     RECT  43.081 3.768 43.164 3.936 ;
     RECT  43.081 3.936 43.116 3.96 ;
     RECT  43.081 3.96 43.164 4.128 ;
     RECT  43.081 4.128 43.116 4.152 ;
     RECT  43.081 4.152 43.164 4.32 ;
     RECT  43.081 4.32 43.116 4.344 ;
     RECT  43.081 4.344 43.164 4.512 ;
     RECT  43.081 4.512 43.116 4.536 ;
     RECT  43.081 4.536 43.164 4.704 ;
     RECT  43.081 4.704 43.116 4.728 ;
     RECT  43.081 4.728 43.164 4.896 ;
     RECT  43.081 4.896 43.116 4.92 ;
     RECT  43.081 4.92 43.164 5.088 ;
     RECT  43.081 5.088 43.116 5.112 ;
     RECT  43.081 5.112 43.164 5.28 ;
     RECT  43.081 5.28 43.116 5.304 ;
     RECT  43.081 5.304 43.164 5.472 ;
     RECT  43.081 5.472 43.116 5.496 ;
     RECT  43.081 5.496 43.164 5.664 ;
     RECT  43.081 5.664 43.116 5.688 ;
     RECT  43.081 5.688 43.164 5.856 ;
     RECT  43.081 5.856 43.116 5.88 ;
     RECT  43.081 5.88 43.164 6.048 ;
     RECT  43.081 6.048 43.116 6.072 ;
     RECT  43.081 6.072 43.164 6.24 ;
     RECT  43.081 6.24 43.116 6.264 ;
     RECT  43.081 6.264 43.164 6.432 ;
     RECT  43.081 6.432 43.116 6.456 ;
     RECT  43.081 6.456 43.164 6.624 ;
     RECT  43.081 6.624 43.116 6.648 ;
     RECT  43.081 6.648 43.164 6.816 ;
     RECT  43.081 6.816 43.116 6.84 ;
     RECT  43.081 6.84 43.164 7.008 ;
     RECT  43.081 7.008 43.116 7.032 ;
     RECT  43.081 7.032 43.164 7.152 ;
     RECT  43.081 7.152 43.116 7.176 ;
     RECT  43.081 7.176 43.164 7.344 ;
     RECT  43.081 7.344 43.116 7.368 ;
     RECT  43.081 7.368 43.164 7.536 ;
     RECT  43.081 7.536 43.116 7.56 ;
     RECT  43.081 7.56 43.164 7.728 ;
     RECT  43.081 7.728 43.116 7.752 ;
     RECT  43.081 7.752 43.164 7.92 ;
     RECT  43.081 7.92 43.116 7.944 ;
     RECT  43.081 7.944 43.164 8.112 ;
     RECT  43.081 8.112 43.116 8.136 ;
     RECT  43.081 8.136 43.164 8.304 ;
     RECT  43.081 8.304 43.116 8.328 ;
     RECT  43.081 8.328 43.164 8.496 ;
     RECT  43.081 8.496 43.116 8.52 ;
     RECT  43.081 8.52 43.164 8.688 ;
     RECT  43.081 8.688 43.116 8.712 ;
     RECT  43.081 8.712 43.164 8.88 ;
     RECT  43.081 8.88 43.116 8.904 ;
     RECT  43.081 8.904 43.164 9.072 ;
     RECT  43.081 9.072 43.116 9.096 ;
     RECT  43.081 9.096 43.164 9.264 ;
     RECT  43.081 9.264 43.116 9.288 ;
     RECT  43.081 9.288 43.164 9.456 ;
     RECT  43.081 9.456 43.116 9.48 ;
     RECT  43.081 9.48 43.164 9.648 ;
     RECT  43.081 9.648 43.116 9.672 ;
     RECT  43.081 9.672 43.164 9.84 ;
     RECT  43.081 9.84 43.116 9.864 ;
     RECT  43.081 9.864 43.164 10.032 ;
     RECT  43.081 10.032 43.116 10.056 ;
     RECT  43.081 10.056 43.164 10.224 ;
     RECT  43.081 10.224 43.116 10.248 ;
     RECT  43.081 10.248 43.164 10.416 ;
     RECT  43.081 10.416 43.116 10.44 ;
     RECT  43.081 10.44 43.164 10.608 ;
     RECT  43.081 10.608 43.116 10.632 ;
     RECT  43.081 10.632 43.164 10.8 ;
     RECT  43.081 10.8 43.116 10.824 ;
     RECT  43.081 10.824 43.164 10.944 ;
     RECT  43.081 10.944 43.116 10.968 ;
     RECT  43.081 10.968 43.164 11.136 ;
     RECT  43.081 11.136 43.116 11.16 ;
     RECT  43.081 11.16 43.164 11.328 ;
     RECT  43.081 11.328 43.116 11.352 ;
     RECT  43.081 11.352 43.164 11.52 ;
     RECT  43.081 11.52 43.116 11.544 ;
     RECT  43.081 11.544 43.164 11.712 ;
     RECT  43.081 11.712 43.116 11.736 ;
     RECT  43.081 11.736 43.164 11.904 ;
     RECT  43.081 11.904 43.116 11.928 ;
     RECT  43.081 11.928 43.164 12.096 ;
     RECT  43.081 12.096 43.116 12.12 ;
     RECT  43.081 12.12 43.164 12.288 ;
     RECT  43.081 12.288 43.116 12.312 ;
     RECT  43.081 12.312 43.164 12.48 ;
     RECT  43.081 12.48 43.116 12.504 ;
     RECT  43.081 12.504 43.164 12.672 ;
     RECT  43.081 12.672 43.116 12.696 ;
     RECT  43.081 12.696 43.164 12.864 ;
     RECT  43.081 12.864 43.116 12.888 ;
     RECT  43.081 12.888 43.164 13.056 ;
     RECT  43.081 13.056 43.116 13.08 ;
     RECT  43.081 13.08 43.164 13.248 ;
     RECT  43.081 13.248 43.116 13.272 ;
     RECT  43.081 13.272 43.164 13.44 ;
     RECT  43.081 13.44 43.116 13.464 ;
     RECT  43.081 13.464 43.164 13.632 ;
     RECT  43.081 13.632 43.116 13.656 ;
     RECT  43.081 13.656 43.164 13.824 ;
     RECT  43.081 13.824 43.116 13.848 ;
     RECT  43.081 13.848 43.164 14.016 ;
     RECT  43.081 14.016 43.116 14.04 ;
     RECT  43.081 14.04 43.164 14.208 ;
     RECT  43.081 14.208 43.116 14.232 ;
     RECT  43.081 14.232 43.164 14.4 ;
     RECT  43.081 14.4 43.116 14.424 ;
     RECT  43.081 14.424 43.164 14.592 ;
     RECT  43.081 14.592 43.116 14.616 ;
     RECT  43.081 14.616 43.164 14.784 ;
     RECT  43.081 14.784 43.116 14.808 ;
     RECT  43.081 14.808 43.164 14.928 ;
     RECT  43.081 14.928 43.116 14.952 ;
     RECT  43.081 14.952 43.164 15.12 ;
     RECT  43.081 15.12 43.116 15.144 ;
     RECT  43.081 15.144 43.164 15.312 ;
     RECT  43.081 15.312 43.116 15.336 ;
     RECT  43.081 15.336 43.164 15.504 ;
     RECT  43.081 15.504 43.116 15.528 ;
     RECT  43.081 15.528 43.164 15.696 ;
     RECT  43.081 15.696 43.116 15.72 ;
     RECT  43.081 15.72 43.164 15.888 ;
     RECT  43.081 15.888 43.116 15.912 ;
     RECT  43.081 15.912 43.164 16.08 ;
     RECT  43.081 16.08 43.116 16.104 ;
     RECT  43.081 16.104 43.164 16.272 ;
     RECT  43.081 16.272 43.116 16.296 ;
     RECT  43.081 16.296 43.164 16.464 ;
     RECT  43.081 16.464 43.116 16.488 ;
     RECT  43.081 16.488 43.164 16.656 ;
     RECT  43.081 16.656 43.116 16.68 ;
     RECT  43.081 16.68 43.164 16.848 ;
     RECT  43.081 16.848 43.116 16.872 ;
     RECT  43.081 16.872 43.164 17.04 ;
     RECT  43.081 17.04 43.116 17.064 ;
     RECT  43.081 17.064 43.164 17.232 ;
     RECT  43.081 17.232 43.116 17.256 ;
     RECT  43.081 17.256 43.164 17.424 ;
     RECT  43.081 17.424 43.116 17.448 ;
     RECT  43.081 17.448 43.164 17.616 ;
     RECT  43.081 17.616 43.116 17.64 ;
     RECT  43.081 17.64 43.164 17.808 ;
     RECT  43.081 17.808 43.116 17.832 ;
     RECT  43.081 17.832 43.164 18 ;
     RECT  43.081 18 43.116 18.024 ;
     RECT  43.081 18.024 43.164 18.192 ;
     RECT  43.081 18.192 43.116 18.216 ;
     RECT  43.081 18.216 43.164 18.384 ;
     RECT  43.081 18.384 43.116 18.408 ;
     RECT  43.081 18.408 43.164 18.576 ;
     RECT  43.081 18.576 43.116 18.6 ;
     RECT  43.081 18.6 43.164 18.72 ;
     RECT  43.081 18.72 43.116 18.744 ;
     RECT  43.081 18.744 43.164 18.912 ;
     RECT  43.081 18.912 43.116 18.936 ;
     RECT  43.081 18.936 43.164 19.104 ;
     RECT  43.081 19.104 43.116 19.128 ;
     RECT  43.081 19.128 43.164 19.296 ;
     RECT  43.081 19.296 43.116 19.32 ;
     RECT  43.081 19.32 43.164 19.488 ;
     RECT  43.081 19.488 43.116 19.512 ;
     RECT  43.081 19.512 43.164 19.68 ;
     RECT  43.081 19.68 43.116 19.704 ;
     RECT  43.081 19.704 43.164 19.872 ;
     RECT  43.081 19.872 43.116 19.896 ;
     RECT  43.081 19.896 43.164 20.064 ;
     RECT  43.081 20.064 43.116 20.088 ;
     RECT  43.081 20.088 43.164 20.256 ;
     RECT  43.081 20.256 43.116 20.28 ;
     RECT  43.081 20.28 43.164 20.448 ;
     RECT  43.081 20.448 43.116 20.472 ;
     RECT  43.081 20.472 43.164 20.64 ;
     RECT  43.081 20.64 43.116 20.664 ;
     RECT  43.081 20.664 43.164 20.832 ;
     RECT  43.081 20.832 43.116 20.856 ;
     RECT  43.081 20.856 43.164 21.024 ;
     RECT  43.081 21.024 43.116 21.048 ;
     RECT  43.081 21.048 43.164 21.216 ;
     RECT  43.081 21.216 43.116 21.24 ;
     RECT  43.081 21.24 43.164 21.408 ;
     RECT  43.081 21.408 43.116 21.432 ;
     RECT  43.081 21.432 43.164 21.6 ;
     RECT  43.081 21.6 43.116 21.624 ;
     RECT  43.081 21.624 43.164 21.792 ;
     RECT  43.081 21.792 43.116 21.816 ;
     RECT  43.081 21.816 43.164 21.984 ;
     RECT  43.081 21.984 43.116 22.008 ;
     RECT  43.081 22.008 43.164 22.176 ;
     RECT  43.081 22.176 43.116 22.2 ;
     RECT  43.081 22.2 43.164 22.368 ;
     RECT  43.081 22.368 43.116 22.392 ;
     RECT  43.081 22.392 43.164 22.56 ;
     RECT  43.081 22.56 43.116 22.584 ;
     RECT  43.081 22.584 43.164 22.704 ;
     RECT  43.081 22.704 43.116 22.728 ;
     RECT  43.081 22.728 43.164 22.896 ;
     RECT  43.081 22.896 43.116 22.92 ;
     RECT  43.081 22.92 43.164 23.088 ;
     RECT  43.081 23.088 43.116 23.112 ;
     RECT  43.081 23.112 43.164 23.28 ;
     RECT  43.081 23.28 43.116 23.304 ;
     RECT  43.081 23.304 43.164 23.472 ;
     RECT  43.081 23.472 43.116 23.496 ;
     RECT  43.081 23.496 43.164 23.664 ;
     RECT  43.081 23.664 43.116 23.688 ;
     RECT  43.081 23.688 43.164 23.856 ;
     RECT  43.081 23.856 43.116 23.88 ;
     RECT  43.081 23.88 43.164 24.048 ;
     RECT  43.081 24.048 43.116 24.072 ;
     RECT  43.081 24.072 43.164 24.24 ;
     RECT  43.081 24.24 43.116 24.264 ;
     RECT  43.081 24.264 43.164 24.432 ;
     RECT  43.081 24.432 43.116 24.456 ;
     RECT  43.081 24.456 43.164 24.624 ;
     RECT  43.081 24.624 43.116 24.648 ;
     RECT  43.081 24.648 43.164 24.816 ;
     RECT  43.081 24.816 43.116 24.84 ;
     RECT  43.081 24.84 43.164 25.008 ;
     RECT  43.081 25.008 43.116 25.032 ;
     RECT  43.081 25.032 43.164 25.2 ;
     RECT  43.081 25.2 43.116 25.224 ;
     RECT  43.081 25.224 43.164 25.392 ;
     RECT  43.081 25.392 43.116 25.416 ;
     RECT  43.081 25.416 43.164 25.584 ;
     RECT  43.081 25.584 43.116 25.608 ;
     RECT  43.081 25.608 43.164 25.776 ;
     RECT  43.081 25.776 43.116 25.8 ;
     RECT  43.081 25.8 43.164 25.968 ;
     RECT  43.081 25.968 43.116 25.992 ;
     RECT  43.081 25.992 43.164 26.16 ;
     RECT  43.081 26.16 43.116 26.184 ;
     RECT  43.081 26.184 43.164 26.352 ;
     RECT  43.081 26.352 43.116 26.376 ;
     RECT  43.081 26.376 43.164 26.496 ;
     RECT  43.081 26.496 43.116 26.52 ;
     RECT  43.081 26.52 43.164 26.688 ;
     RECT  43.081 26.688 43.116 26.712 ;
     RECT  43.081 26.712 43.164 26.88 ;
     RECT  43.081 26.88 43.116 26.904 ;
     RECT  43.081 26.904 43.164 27.072 ;
     RECT  43.081 27.072 43.116 27.096 ;
     RECT  43.081 27.096 43.164 27.264 ;
     RECT  43.081 27.264 43.116 27.288 ;
     RECT  43.081 27.288 43.164 27.456 ;
     RECT  43.081 27.456 43.116 27.48 ;
     RECT  43.081 27.48 43.164 27.648 ;
     RECT  43.081 27.648 43.116 27.672 ;
     RECT  43.081 27.672 43.164 27.84 ;
     RECT  43.081 27.84 43.116 27.864 ;
     RECT  43.081 27.864 43.164 28.032 ;
     RECT  43.081 28.032 43.116 28.056 ;
     RECT  43.081 28.056 43.164 28.224 ;
     RECT  43.081 28.224 43.116 28.248 ;
     RECT  43.081 28.248 43.164 28.416 ;
     RECT  43.081 28.416 43.116 28.44 ;
     RECT  43.081 28.44 43.164 28.608 ;
     RECT  43.081 28.608 43.116 28.632 ;
     RECT  43.081 28.632 43.164 28.8 ;
     RECT  43.081 28.8 43.116 28.824 ;
     RECT  43.081 28.824 43.164 28.992 ;
     RECT  43.081 28.992 43.116 29.016 ;
     RECT  43.081 29.016 43.164 29.184 ;
     RECT  43.081 29.184 43.116 29.208 ;
     RECT  43.081 29.208 43.164 29.376 ;
     RECT  43.081 29.376 43.116 29.4 ;
     RECT  43.081 29.4 43.164 29.568 ;
     RECT  43.081 29.568 43.116 29.592 ;
     RECT  43.081 29.592 43.164 29.76 ;
     RECT  43.081 29.76 43.116 29.784 ;
     RECT  43.081 29.784 43.164 29.952 ;
     RECT  43.081 29.952 43.116 29.976 ;
     RECT  43.081 29.976 43.164 30.144 ;
     RECT  43.081 30.144 43.116 30.168 ;
     RECT  43.081 30.168 43.164 30.336 ;
     RECT  43.081 30.336 43.116 30.36 ;
     RECT  43.081 30.36 43.164 30.48 ;
     RECT  43.081 30.48 43.116 30.504 ;
     RECT  43.081 30.504 43.164 30.672 ;
     RECT  43.081 30.672 43.116 30.696 ;
     RECT  43.081 30.696 43.164 30.864 ;
     RECT  43.081 30.864 43.116 30.888 ;
     RECT  43.081 30.888 43.164 31.056 ;
     RECT  43.081 31.056 43.116 31.08 ;
     RECT  43.081 31.08 43.164 31.248 ;
     RECT  43.081 31.248 43.116 31.272 ;
     RECT  43.081 31.272 43.164 31.44 ;
     RECT  43.081 31.44 43.116 31.464 ;
     RECT  43.081 31.464 43.164 31.632 ;
     RECT  43.081 31.632 43.116 31.656 ;
     RECT  43.081 31.656 43.164 31.824 ;
     RECT  43.081 31.824 43.116 31.848 ;
     RECT  43.081 31.848 43.164 32.016 ;
     RECT  43.081 32.016 43.116 32.04 ;
     RECT  43.081 32.04 43.164 32.208 ;
     RECT  43.081 32.208 43.116 32.232 ;
     RECT  43.081 32.232 43.164 32.4 ;
     RECT  43.081 32.4 43.116 32.424 ;
     RECT  43.081 32.424 43.164 32.592 ;
     RECT  43.081 32.592 43.116 32.616 ;
     RECT  43.081 32.616 43.164 32.784 ;
     RECT  43.081 32.784 43.116 32.808 ;
     RECT  43.081 32.808 43.164 32.976 ;
     RECT  43.081 32.976 43.116 33 ;
     RECT  43.081 33 43.164 33.168 ;
     RECT  43.081 33.168 43.116 33.192 ;
     RECT  43.081 33.192 43.164 33.36 ;
     RECT  43.081 33.36 43.116 33.384 ;
     RECT  43.081 33.384 43.164 33.552 ;
     RECT  43.081 33.552 43.116 33.576 ;
     RECT  43.081 33.576 43.164 33.744 ;
     RECT  43.081 33.744 43.116 33.768 ;
     RECT  43.081 33.768 43.164 33.936 ;
     RECT  43.081 33.936 43.116 33.96 ;
     RECT  43.081 33.96 43.164 34.128 ;
     RECT  43.081 34.128 43.116 34.152 ;
     RECT  43.081 34.152 43.164 34.272 ;
     RECT  43.081 34.272 43.116 34.296 ;
     RECT  43.081 34.296 43.164 34.464 ;
     RECT  43.081 34.464 43.116 34.488 ;
     RECT  43.081 34.488 43.164 34.656 ;
     RECT  43.081 34.656 43.116 34.68 ;
     RECT  43.081 34.68 43.164 34.848 ;
     RECT  43.081 34.848 43.116 34.872 ;
     RECT  43.081 34.872 43.164 35.04 ;
     RECT  43.081 35.04 43.116 35.064 ;
     RECT  43.081 35.064 43.164 35.232 ;
     RECT  43.081 35.232 43.116 35.256 ;
     RECT  43.081 35.256 43.164 35.424 ;
     RECT  43.081 35.424 43.116 35.448 ;
     RECT  43.081 35.448 43.164 35.616 ;
     RECT  43.081 35.616 43.116 35.64 ;
     RECT  43.081 35.64 43.164 35.808 ;
     RECT  43.081 35.808 43.116 35.832 ;
     RECT  43.081 35.832 43.164 36 ;
     RECT  43.081 36 43.116 36.024 ;
     RECT  43.081 36.024 43.164 36.192 ;
     RECT  43.081 36.192 43.116 36.216 ;
     RECT  43.081 36.216 43.164 36.384 ;
     RECT  43.081 36.384 43.116 36.408 ;
     RECT  43.081 36.408 43.164 36.576 ;
     RECT  43.081 36.576 43.116 36.6 ;
     RECT  43.081 36.6 43.164 36.768 ;
     RECT  43.081 36.768 43.116 36.792 ;
     RECT  43.081 36.792 43.164 36.96 ;
     RECT  43.081 36.96 43.116 36.984 ;
     RECT  43.081 36.984 43.164 37.152 ;
     RECT  43.081 37.152 43.116 37.176 ;
     RECT  43.081 37.176 43.164 37.344 ;
     RECT  43.081 37.344 43.116 37.368 ;
     RECT  43.081 37.368 43.164 37.536 ;
     RECT  43.081 37.536 43.116 37.56 ;
     RECT  43.081 37.56 43.164 37.728 ;
     RECT  43.081 37.728 43.116 37.752 ;
     RECT  43.081 37.752 43.164 37.92 ;
     RECT  43.081 37.92 43.116 37.944 ;
     RECT  43.081 37.944 43.164 38.112 ;
     RECT  43.081 38.112 43.116 38.136 ;
     RECT  43.081 38.136 43.164 38.256 ;
     RECT  43.081 38.256 43.116 38.28 ;
     RECT  43.081 38.28 43.164 38.448 ;
     RECT  43.081 38.448 43.116 38.472 ;
     RECT  43.081 38.472 43.164 38.64 ;
     RECT  43.081 38.64 43.116 38.664 ;
     RECT  43.081 38.664 43.164 38.832 ;
     RECT  43.081 38.832 43.116 38.856 ;
     RECT  43.081 38.856 43.164 39.024 ;
     RECT  43.081 39.024 43.116 39.048 ;
     RECT  43.081 39.048 43.164 39.216 ;
     RECT  43.081 39.216 43.116 39.24 ;
     RECT  43.081 39.24 43.164 39.408 ;
     RECT  43.081 39.408 43.116 39.432 ;
     RECT  43.081 39.432 43.164 39.6 ;
     RECT  43.081 39.6 43.116 39.624 ;
     RECT  43.081 39.624 43.164 39.792 ;
     RECT  43.081 39.792 43.116 39.816 ;
     RECT  43.081 39.816 43.164 39.984 ;
     RECT  43.081 39.984 43.116 40.008 ;
     RECT  43.081 40.008 43.164 40.176 ;
     RECT  43.081 40.176 43.116 40.2 ;
     RECT  43.081 40.2 43.164 40.368 ;
     RECT  43.081 40.368 43.116 40.392 ;
     RECT  43.081 40.392 43.164 40.56 ;
     RECT  43.081 40.56 43.116 40.584 ;
     RECT  43.081 40.584 43.164 40.752 ;
     RECT  43.081 40.752 43.116 40.776 ;
     RECT  43.081 40.776 43.164 40.944 ;
     RECT  43.081 40.944 43.116 40.968 ;
    LAYER M5 ;
     RECT  2.472 0.016 2.832 0.084 ;
     RECT  2.856 0.016 3.168 0.084 ;
     RECT  3.192 0.016 3.552 0.084 ;
     RECT  3.576 0.016 3.936 0.084 ;
     RECT  3.96 0.016 4.32 0.084 ;
     RECT  4.344 0.016 4.704 0.084 ;
     RECT  4.728 0.016 5.088 0.084 ;
     RECT  5.112 0.016 5.472 0.084 ;
     RECT  5.496 0.016 5.856 0.084 ;
     RECT  5.88 0.016 6.24 0.084 ;
     RECT  6.264 0.016 6.624 0.084 ;
     RECT  6.648 0.016 7.008 0.084 ;
     RECT  7.032 0.016 7.344 0.084 ;
     RECT  7.368 0.016 7.728 0.084 ;
     RECT  7.752 0.016 8.112 0.084 ;
     RECT  8.136 0.016 8.496 0.084 ;
     RECT  8.52 0.016 8.88 0.084 ;
     RECT  8.904 0.016 9.264 0.084 ;
     RECT  9.288 0.016 9.648 0.084 ;
     RECT  9.672 0.016 10.224 0.084 ;
     RECT  10.248 0.016 10.608 0.084 ;
     RECT  10.632 0.016 10.944 0.084 ;
     RECT  10.968 0.016 11.328 0.084 ;
     RECT  11.352 0.016 11.712 0.084 ;
     RECT  11.736 0.016 12.096 0.084 ;
     RECT  12.12 0.016 12.48 0.084 ;
     RECT  12.504 0.016 12.864 0.084 ;
     RECT  12.888 0.016 13.248 0.084 ;
     RECT  13.272 0.016 13.632 0.084 ;
     RECT  13.656 0.016 14.016 0.084 ;
     RECT  14.04 0.016 14.4 0.084 ;
     RECT  14.424 0.016 14.784 0.084 ;
     RECT  14.808 0.016 15.12 0.084 ;
     RECT  15.144 0.016 15.504 0.084 ;
     RECT  15.528 0.016 15.888 0.084 ;
     RECT  15.912 0.016 16.272 0.084 ;
     RECT  16.296 0.016 16.656 0.084 ;
     RECT  16.68 0.016 17.04 0.084 ;
     RECT  17.064 0.016 17.424 0.084 ;
     RECT  17.448 0.016 17.808 0.084 ;
     RECT  17.832 0.016 18.192 0.084 ;
     RECT  18.216 0.016 18.576 0.084 ;
     RECT  18.6 0.016 18.912 0.084 ;
     RECT  18.936 0.016 19.296 0.084 ;
     RECT  19.32 0.016 19.68 0.084 ;
     RECT  19.704 0.016 20.064 0.084 ;
     RECT  20.088 0.016 20.448 0.084 ;
     RECT  20.472 0.016 20.832 0.084 ;
     RECT  20.856 0.016 21.216 0.084 ;
     RECT  21.24 0.016 21.6 0.084 ;
     RECT  21.624 0.016 21.984 0.084 ;
     RECT  22.008 0.016 22.368 0.084 ;
     RECT  22.392 0.016 22.704 0.084 ;
     RECT  22.728 0.016 23.088 0.084 ;
     RECT  23.112 0.016 23.472 0.084 ;
     RECT  23.496 0.016 23.856 0.084 ;
     RECT  23.88 0.016 24.24 0.084 ;
     RECT  24.264 0.016 24.624 0.084 ;
     RECT  24.648 0.016 25.008 0.084 ;
     RECT  25.032 0.016 25.392 0.084 ;
     RECT  25.416 0.016 25.776 0.084 ;
     RECT  25.8 0.016 26.16 0.084 ;
     RECT  26.184 0.016 26.496 0.084 ;
     RECT  26.52 0.016 26.88 0.084 ;
     RECT  26.904 0.016 27.264 0.084 ;
     RECT  27.288 0.016 27.648 0.084 ;
     RECT  27.672 0.016 28.032 0.084 ;
     RECT  28.056 0.016 28.416 0.084 ;
     RECT  28.44 0.016 28.8 0.084 ;
     RECT  28.824 0.016 29.184 0.084 ;
     RECT  29.208 0.016 29.568 0.084 ;
     RECT  29.592 0.016 29.952 0.084 ;
     RECT  29.976 0.016 30.336 0.084 ;
     RECT  30.36 0.016 30.672 0.084 ;
     RECT  30.696 0.016 31.056 0.084 ;
     RECT  31.08 0.016 31.44 0.084 ;
     RECT  31.464 0.016 31.824 0.084 ;
     RECT  31.848 0.016 32.208 0.084 ;
     RECT  32.232 0.016 32.592 0.084 ;
     RECT  32.616 0.016 32.976 0.084 ;
     RECT  33 0.016 33.36 0.084 ;
     RECT  33.384 0.016 33.744 0.084 ;
     RECT  33.768 0.016 34.128 0.084 ;
     RECT  34.152 0.016 34.464 0.084 ;
     RECT  34.488 0.016 34.848 0.084 ;
     RECT  34.872 0.016 35.232 0.084 ;
     RECT  35.256 0.016 35.616 0.084 ;
     RECT  35.64 0.016 36 0.084 ;
     RECT  36.024 0.016 36.384 0.084 ;
     RECT  36.408 0.016 36.768 0.084 ;
     RECT  36.792 0.016 37.152 0.084 ;
     RECT  37.176 0.016 37.536 0.084 ;
     RECT  37.56 0.016 37.92 0.084 ;
     RECT  37.944 0.016 38.256 0.084 ;
     RECT  38.28 0.016 38.64 0.084 ;
     RECT  38.664 0.016 39.024 0.084 ;
     RECT  39.048 0.016 39.408 0.084 ;
     RECT  39.432 0.016 39.792 0.084 ;
     RECT  39.816 0.016 40.176 0.084 ;
     RECT  40.2 0.016 40.56 0.084 ;
     RECT  40.584 0.016 40.944 0.084 ;
     RECT  2.448 0.084 40.968 0.131 ;
     RECT  30.672 0.131 40.968 0.179 ;
     RECT  30.672 0.179 38.664 0.563 ;
     RECT  31.056 0.563 38.664 0.611 ;
     RECT  35.232 0.611 35.256 1.139 ;
     RECT  39.792 0.179 40.968 1.139 ;
     RECT  2.448 0.131 29.592 1.763 ;
     RECT  31.056 0.611 34.152 1.763 ;
     RECT  11.328 1.763 11.352 1.811 ;
     RECT  12.48 1.763 13.656 1.811 ;
     RECT  22.368 1.763 22.392 1.811 ;
     RECT  23.856 1.763 25.032 1.811 ;
     RECT  12.48 1.811 13.512 1.859 ;
     RECT  20.448 1.763 20.472 1.859 ;
     RECT  2.448 1.763 8.112 2.137 ;
     RECT  39.792 1.139 39.816 2.137 ;
     RECT  40.944 1.139 40.968 2.137 ;
     RECT  28.416 1.763 29.592 2.151 ;
     RECT  34.8 2.137 34.92 2.151 ;
     RECT  18.192 1.763 18.912 2.195 ;
     RECT  26.448 1.763 26.52 2.195 ;
     RECT  2.4 2.137 8.112 2.291 ;
     RECT  9.648 1.763 10.152 2.291 ;
     RECT  16.272 1.763 17.064 2.291 ;
     RECT  28.416 2.151 29.712 2.291 ;
     RECT  31.44 1.763 33 2.291 ;
     RECT  38.64 0.611 38.664 2.291 ;
     RECT  31.44 2.291 32.232 2.339 ;
     RECT  34.8 2.151 35.112 2.485 ;
     RECT  4.416 2.291 8.112 2.771 ;
     RECT  34.8 2.485 35.4 2.821 ;
     RECT  36.768 0.611 37.368 2.821 ;
     RECT  4.512 2.771 8.112 2.869 ;
     RECT  10.128 2.291 10.152 2.869 ;
     RECT  34.8 2.821 37.368 2.915 ;
     RECT  39.792 2.137 40.968 2.915 ;
     RECT  32.208 2.339 32.232 2.963 ;
     RECT  10.128 2.869 10.632 3.011 ;
     RECT  4.512 2.869 8.232 3.013 ;
     RECT  13.2 1.859 13.512 3.013 ;
     RECT  24 1.811 24.312 3.013 ;
     RECT  37.296 2.915 37.368 3.109 ;
     RECT  23.904 3.013 24.312 3.203 ;
     RECT  13.2 3.013 14.184 3.395 ;
     RECT  39.792 2.915 40.512 3.397 ;
     RECT  4.512 3.013 8.328 3.443 ;
     RECT  10.128 3.011 10.152 3.539 ;
     RECT  26.448 2.195 26.472 3.637 ;
     RECT  29.4 2.291 29.712 3.685 ;
     RECT  29.184 3.685 29.712 3.827 ;
     RECT  18.6 2.195 18.912 3.829 ;
     RECT  19.968 3.205 19.992 3.829 ;
     RECT  26.448 3.637 26.76 3.875 ;
     RECT  37.296 3.109 37.416 3.877 ;
     RECT  9.168 3.589 9.288 3.923 ;
     RECT  9.264 3.923 9.288 3.971 ;
     RECT  2.4 2.291 2.856 4.259 ;
     RECT  25.392 4.117 25.416 4.357 ;
     RECT  37.296 3.877 38.04 4.501 ;
     RECT  25.296 4.357 25.416 4.547 ;
     RECT  39.6 3.397 40.512 4.981 ;
     RECT  39.6 4.981 40.632 5.123 ;
     RECT  37.296 4.501 38.232 5.125 ;
     RECT  39.6 5.123 40.512 5.125 ;
     RECT  34.8 2.915 36.072 5.557 ;
     RECT  37.296 5.125 40.512 5.557 ;
     RECT  4.512 3.443 8.112 5.605 ;
     RECT  4.512 5.605 8.52 5.701 ;
     RECT  4.512 5.701 8.616 5.747 ;
     RECT  34.8 5.557 40.512 5.747 ;
     RECT  5.616 5.747 8.616 5.891 ;
     RECT  5.616 5.891 8.112 6.083 ;
     RECT  34.8 5.747 38.232 6.899 ;
     RECT  4.512 5.747 4.632 7.141 ;
     RECT  5.664 6.083 8.112 7.141 ;
     RECT  39.6 5.747 40.512 7.285 ;
     RECT  22.752 3.397 22.776 7.669 ;
     RECT  22.464 7.669 22.776 7.715 ;
     RECT  4.512 7.141 8.112 7.765 ;
     RECT  18.6 3.829 19.992 8.531 ;
     RECT  38.736 7.285 40.512 10.595 ;
     RECT  26.448 3.875 26.472 10.883 ;
     RECT  2.4 4.259 2.712 10.981 ;
     RECT  2.304 10.981 2.712 11.171 ;
     RECT  22.464 7.715 22.488 11.221 ;
     RECT  15.12 5.173 15.144 11.459 ;
     RECT  2.4 11.171 2.712 12.325 ;
     RECT  2.304 12.325 2.712 12.515 ;
     RECT  2.4 12.515 2.712 13.669 ;
     RECT  4.368 7.765 8.112 13.669 ;
     RECT  2.4 13.669 8.112 14.339 ;
     RECT  4.368 14.339 8.112 17.123 ;
     RECT  18.6 8.531 19.656 17.507 ;
     RECT  4.368 17.123 4.44 17.509 ;
     RECT  39.024 10.595 40.512 18.181 ;
     RECT  5.664 17.123 8.112 18.421 ;
     RECT  5.664 18.421 8.232 19.427 ;
     RECT  22.032 11.221 22.488 19.523 ;
     RECT  38.88 18.181 40.512 19.955 ;
     RECT  22.032 19.523 22.056 21.589 ;
     RECT  22.032 21.589 22.152 21.635 ;
     RECT  34.8 6.899 37.56 22.211 ;
     RECT  2.4 14.339 2.712 23.029 ;
     RECT  2.304 23.029 2.712 23.267 ;
     RECT  5.664 19.427 8.112 23.411 ;
     RECT  34.8 22.211 37.32 23.459 ;
     RECT  2.4 23.267 2.712 24.997 ;
     RECT  6 23.411 8.112 25.045 ;
     RECT  2.304 24.997 2.712 25.187 ;
     RECT  4.176 17.509 4.44 26.101 ;
     RECT  3.984 26.101 4.44 26.243 ;
     RECT  29.4 3.827 29.712 26.533 ;
     RECT  3.984 26.243 4.2 26.819 ;
     RECT  4.176 26.819 4.2 27.011 ;
     RECT  39.6 19.955 40.512 28.309 ;
     RECT  5.616 25.045 8.112 28.597 ;
     RECT  5.376 28.597 8.112 28.691 ;
     RECT  5.376 28.691 6.024 29.219 ;
     RECT  38.832 28.309 40.512 29.219 ;
     RECT  7.104 28.691 8.112 30.035 ;
     RECT  2.4 25.187 2.712 30.277 ;
     RECT  2.304 30.277 2.712 30.419 ;
     RECT  29.4 26.533 30.504 31.331 ;
     RECT  22.128 21.635 22.152 31.763 ;
     RECT  7.8 30.035 8.112 33.445 ;
     RECT  7.104 33.445 8.112 34.691 ;
     RECT  34.8 23.459 35.736 34.835 ;
     RECT  5.376 29.219 5.4 35.317 ;
     RECT  39.6 29.219 40.512 35.317 ;
     RECT  5.088 35.317 5.4 35.363 ;
     RECT  7.8 34.691 8.112 35.797 ;
     RECT  36.768 23.459 37.32 35.845 ;
     RECT  39.552 35.317 40.512 37.043 ;
     RECT  0.192 21.493 0.216 37.091 ;
     RECT  2.4 30.419 2.712 37.573 ;
     RECT  34.8 34.835 35.208 37.957 ;
     RECT  5.088 35.363 5.112 38.147 ;
     RECT  16.176 31.861 16.2 38.147 ;
     RECT  2.4 37.573 2.904 38.243 ;
     RECT  7.8 35.797 8.28 38.483 ;
     RECT  33.072 37.909 33.096 38.531 ;
     RECT  13.2 3.395 13.512 38.533 ;
     RECT  22.128 38.437 22.152 38.579 ;
     RECT  34.8 37.957 35.256 38.579 ;
     RECT  26.592 37.573 26.616 38.675 ;
     RECT  13.2 38.533 13.608 38.723 ;
     RECT  39.6 37.043 40.512 38.725 ;
     RECT  24 3.203 24.312 38.773 ;
     RECT  34.8 38.579 35.208 38.819 ;
     RECT  18.6 17.507 19.512 39.395 ;
     RECT  39.6 38.725 40.968 39.443 ;
     RECT  24 38.773 24.792 39.493 ;
     RECT  22.8 39.253 22.824 39.539 ;
     RECT  24 39.493 25.032 39.635 ;
     RECT  29.4 31.331 30.36 39.877 ;
     RECT  9.504 37.957 9.528 39.923 ;
     RECT  39.984 39.443 40.968 40.405 ;
     RECT  13.2 38.723 13.512 40.453 ;
     RECT  36.768 35.845 37.944 40.547 ;
     RECT  28.08 31.861 28.104 40.645 ;
     RECT  29.184 39.877 30.36 40.645 ;
     RECT  34.8 38.819 35.112 40.693 ;
     RECT  28.08 40.645 30.36 40.885 ;
     RECT  18.6 39.395 18.912 40.933 ;
     RECT  21.6 39.781 21.624 40.933 ;
     RECT  24 39.635 24.312 40.933 ;
     RECT  28.08 40.885 30.792 40.933 ;
     RECT  34.8 40.693 35.64 40.933 ;
     RECT  2.4 38.243 2.712 40.981 ;
     RECT  5.088 40.933 5.112 40.981 ;
     RECT  6.624 40.453 6.648 40.981 ;
     RECT  7.8 38.483 8.112 40.981 ;
     RECT  9.648 40.453 10.632 40.981 ;
     RECT  12.48 40.453 13.512 40.981 ;
     RECT  17.04 40.453 17.064 40.981 ;
     RECT  18.6 40.933 19.704 40.981 ;
     RECT  20.832 40.933 21.624 40.981 ;
     RECT  23.856 40.933 24.312 40.981 ;
     RECT  26.16 40.453 26.184 40.981 ;
     RECT  27.264 40.933 31.464 40.981 ;
     RECT  2.4 40.981 14.808 41.063 ;
     RECT  34.8 40.933 36.408 41.063 ;
     RECT  37.536 40.547 37.944 41.557 ;
     RECT  39.024 40.405 40.968 41.557 ;
     RECT  22.704 40.981 25.032 41.749 ;
     RECT  26.16 40.981 31.848 41.749 ;
     RECT  2.448 41.063 14.808 42.133 ;
     RECT  15.888 40.981 17.064 42.133 ;
     RECT  18.192 40.981 21.624 42.133 ;
     RECT  22.704 41.749 31.848 42.133 ;
     RECT  32.976 40.453 33 42.133 ;
     RECT  34.128 41.605 34.152 42.133 ;
     RECT  35.232 41.063 36.408 42.133 ;
     RECT  37.536 41.557 40.968 42.133 ;
     RECT  2.448 42.133 34.152 43.045 ;
     RECT  35.232 42.133 40.968 43.045 ;
     RECT  2.448 43.045 40.968 43.116 ;
     RECT  2.472 43.116 2.832 43.152 ;
     RECT  2.856 43.116 3.168 43.152 ;
     RECT  3.192 43.116 3.552 43.152 ;
     RECT  3.576 43.116 3.936 43.152 ;
     RECT  3.96 43.116 4.32 43.152 ;
     RECT  4.344 43.116 4.704 43.152 ;
     RECT  4.728 43.116 5.088 43.152 ;
     RECT  5.112 43.116 5.472 43.152 ;
     RECT  5.496 43.116 5.856 43.152 ;
     RECT  5.88 43.116 6.24 43.152 ;
     RECT  6.264 43.116 6.624 43.152 ;
     RECT  6.648 43.116 7.008 43.152 ;
     RECT  7.032 43.116 7.344 43.152 ;
     RECT  7.368 43.116 7.728 43.152 ;
     RECT  7.752 43.116 8.112 43.152 ;
     RECT  8.136 43.116 8.496 43.152 ;
     RECT  8.52 43.116 8.88 43.152 ;
     RECT  8.904 43.116 9.264 43.152 ;
     RECT  9.288 43.116 9.648 43.152 ;
     RECT  9.672 43.116 10.224 43.152 ;
     RECT  10.248 43.116 10.608 43.152 ;
     RECT  10.632 43.116 10.944 43.152 ;
     RECT  10.968 43.116 11.328 43.152 ;
     RECT  11.352 43.116 11.712 43.152 ;
     RECT  11.736 43.116 12.096 43.152 ;
     RECT  12.12 43.116 12.48 43.152 ;
     RECT  12.504 43.116 12.864 43.152 ;
     RECT  12.888 43.116 13.248 43.152 ;
     RECT  13.272 43.116 13.632 43.152 ;
     RECT  13.656 43.116 14.016 43.152 ;
     RECT  14.04 43.116 14.4 43.152 ;
     RECT  14.424 43.116 14.784 43.152 ;
     RECT  14.808 43.116 15.12 43.152 ;
     RECT  15.144 43.116 15.504 43.152 ;
     RECT  15.528 43.116 15.888 43.152 ;
     RECT  15.912 43.116 16.272 43.152 ;
     RECT  16.296 43.116 16.656 43.152 ;
     RECT  16.68 43.116 17.04 43.152 ;
     RECT  17.064 43.116 17.424 43.152 ;
     RECT  17.448 43.116 17.808 43.152 ;
     RECT  17.832 43.116 18.192 43.152 ;
     RECT  18.216 43.116 18.576 43.152 ;
     RECT  18.6 43.116 18.912 43.152 ;
     RECT  18.936 43.116 19.296 43.152 ;
     RECT  19.32 43.116 19.68 43.152 ;
     RECT  19.704 43.116 20.064 43.152 ;
     RECT  20.088 43.116 20.448 43.152 ;
     RECT  20.472 43.116 20.832 43.152 ;
     RECT  20.856 43.116 21.216 43.152 ;
     RECT  21.24 43.116 21.6 43.152 ;
     RECT  21.624 43.116 21.984 43.152 ;
     RECT  22.008 43.116 22.368 43.152 ;
     RECT  22.392 43.116 22.704 43.152 ;
     RECT  22.728 43.116 23.088 43.152 ;
     RECT  23.112 43.116 23.472 43.152 ;
     RECT  23.496 43.116 23.856 43.152 ;
     RECT  23.88 43.116 24.24 43.152 ;
     RECT  24.264 43.116 24.624 43.152 ;
     RECT  24.648 43.116 25.008 43.152 ;
     RECT  25.032 43.116 25.392 43.152 ;
     RECT  25.416 43.116 25.776 43.152 ;
     RECT  25.8 43.116 26.16 43.152 ;
     RECT  26.184 43.116 26.496 43.152 ;
     RECT  26.52 43.116 26.88 43.152 ;
     RECT  26.904 43.116 27.264 43.152 ;
     RECT  27.288 43.116 27.648 43.152 ;
     RECT  27.672 43.116 28.032 43.152 ;
     RECT  28.056 43.116 28.416 43.152 ;
     RECT  28.44 43.116 28.8 43.152 ;
     RECT  28.824 43.116 29.184 43.152 ;
     RECT  29.208 43.116 29.568 43.152 ;
     RECT  29.592 43.116 29.952 43.152 ;
     RECT  29.976 43.116 30.336 43.152 ;
     RECT  30.36 43.116 30.672 43.152 ;
     RECT  30.696 43.116 31.056 43.152 ;
     RECT  31.08 43.116 31.44 43.152 ;
     RECT  31.464 43.116 31.824 43.152 ;
     RECT  31.848 43.116 32.208 43.152 ;
     RECT  32.232 43.116 32.592 43.152 ;
     RECT  32.616 43.116 32.976 43.152 ;
     RECT  33 43.116 33.36 43.152 ;
     RECT  33.384 43.116 33.744 43.152 ;
     RECT  33.768 43.116 34.128 43.152 ;
     RECT  34.152 43.116 34.464 43.152 ;
     RECT  34.488 43.116 34.848 43.152 ;
     RECT  34.872 43.116 35.232 43.152 ;
     RECT  35.256 43.116 35.616 43.152 ;
     RECT  35.64 43.116 36 43.152 ;
     RECT  36.024 43.116 36.384 43.152 ;
     RECT  36.408 43.116 36.768 43.152 ;
     RECT  36.792 43.116 37.152 43.152 ;
     RECT  37.176 43.116 37.536 43.152 ;
     RECT  37.56 43.116 37.92 43.152 ;
     RECT  37.944 43.116 38.256 43.152 ;
     RECT  38.28 43.116 38.64 43.152 ;
     RECT  38.664 43.116 39.024 43.152 ;
     RECT  39.048 43.116 39.408 43.152 ;
     RECT  39.432 43.116 39.792 43.152 ;
     RECT  39.816 43.116 40.176 43.152 ;
     RECT  40.2 43.116 40.56 43.152 ;
     RECT  40.584 43.116 40.944 43.152 ;
     RECT  29.64 0.131 29.904 0.132 ;
     RECT  30.024 0.131 30.288 0.132 ;
     RECT  30.408 0.131 30.624 0.132 ;
     RECT  29.592 0.132 30.672 0.563 ;
     RECT  38.664 0.179 39.792 2.291 ;
     RECT  29.592 0.563 31.056 1.763 ;
     RECT  34.152 0.611 35.232 1.139 ;
     RECT  35.256 0.611 36.768 1.139 ;
     RECT  37.368 0.611 38.64 2.291 ;
     RECT  34.152 1.139 36.768 1.763 ;
     RECT  39.816 1.139 40.944 2.137 ;
     RECT  8.112 1.763 9.648 2.291 ;
     RECT  10.152 1.763 11.328 1.811 ;
     RECT  11.352 1.763 12.48 1.811 ;
     RECT  13.656 1.763 14.184 1.811 ;
     RECT  17.064 1.763 18.192 2.195 ;
     RECT  18.912 1.763 20.448 1.859 ;
     RECT  22.392 1.763 23.856 1.811 ;
     RECT  25.032 1.763 26.448 1.811 ;
     RECT  29.592 1.763 29.712 2.151 ;
     RECT  34.8 1.763 36.768 2.137 ;
     RECT  10.152 1.811 10.632 2.869 ;
     RECT  13.512 1.811 14.184 3.013 ;
     RECT  23.904 1.811 24 3.013 ;
     RECT  18.912 1.859 19.992 3.205 ;
     RECT  34.92 2.137 36.768 2.151 ;
     RECT  35.112 2.151 36.768 2.485 ;
     RECT  26.472 2.195 26.52 3.637 ;
     RECT  8.112 2.291 10.128 2.869 ;
     RECT  29.184 2.291 29.4 3.685 ;
     RECT  37.368 2.291 37.416 3.109 ;
     RECT  39.6 2.291 39.792 3.397 ;
     RECT  35.4 2.485 36.768 2.821 ;
     RECT  8.232 2.869 10.128 3.013 ;
     RECT  36.072 2.915 37.296 5.557 ;
     RECT  8.328 3.013 10.128 3.443 ;
     RECT  23.904 3.203 24 3.397 ;
     RECT  18.912 3.205 19.968 3.829 ;
     RECT  22.776 3.397 24 7.715 ;
     RECT  8.112 3.443 10.128 3.539 ;
     RECT  8.112 3.539 9.288 3.589 ;
     RECT  8.112 3.589 9.168 3.923 ;
     RECT  8.112 3.923 9.264 3.971 ;
     RECT  24.312 4.117 25.392 4.357 ;
     RECT  25.416 4.117 26.448 4.547 ;
     RECT  24.312 4.357 25.296 4.547 ;
     RECT  38.232 4.501 39.6 5.125 ;
     RECT  4.632 5.747 5.616 6.083 ;
     RECT  38.232 5.747 39.6 6.899 ;
     RECT  4.632 6.083 5.664 7.141 ;
     RECT  37.56 6.899 39.6 7.285 ;
     RECT  37.56 7.285 38.736 10.595 ;
     RECT  22.488 7.715 24 19.523 ;
     RECT  37.56 10.595 39.024 18.181 ;
     RECT  2.304 11.171 2.4 12.325 ;
     RECT  4.44 17.123 5.664 23.411 ;
     RECT  2.712 17.509 4.176 26.101 ;
     RECT  37.56 18.181 38.88 19.955 ;
     RECT  35.736 23.459 36.768 34.835 ;
     RECT  4.44 25.045 5.616 26.243 ;
     RECT  2.712 26.101 3.984 26.819 ;
     RECT  4.2 26.243 5.616 27.011 ;
     RECT  2.712 26.819 4.176 27.011 ;
     RECT  37.32 28.309 38.832 29.219 ;
     RECT  6.024 28.691 7.104 29.219 ;
     RECT  28.104 31.861 29.4 39.877 ;
     RECT  26.616 37.573 28.08 38.675 ;
     RECT  8.28 37.957 9.504 38.483 ;
     RECT  35.256 37.957 36.768 38.579 ;
     RECT  8.112 38.483 9.504 39.923 ;
     RECT  22.128 38.579 22.152 39.253 ;
     RECT  22.128 39.253 22.8 39.539 ;
     RECT  22.824 39.253 24 39.539 ;
     RECT  39.6 39.443 39.984 40.405 ;
     RECT  22.128 39.539 24 39.781 ;
     RECT  24.312 39.635 25.032 40.453 ;
     RECT  21.624 39.781 24 40.933 ;
     RECT  28.104 39.877 29.184 40.645 ;
     RECT  8.112 39.923 9.528 40.453 ;
     RECT  37.944 40.405 39.024 41.557 ;
     RECT  6.648 40.453 7.8 40.981 ;
     RECT  8.112 40.453 9.648 40.981 ;
     RECT  24.312 40.453 26.16 40.981 ;
     RECT  36.768 40.547 37.536 40.693 ;
     RECT  35.64 40.693 37.536 40.933 ;
     RECT  5.112 40.933 6.624 40.981 ;
     RECT  19.704 40.933 20.832 40.981 ;
     RECT  21.624 40.933 23.856 40.981 ;
     RECT  26.184 40.933 27.264 40.981 ;
     RECT  31.464 40.933 32.976 40.981 ;
     RECT  36.408 40.933 37.536 42.133 ;
     RECT  14.808 40.981 15.888 42.133 ;
     RECT  17.064 40.981 18.192 42.133 ;
     RECT  21.624 40.981 22.704 42.133 ;
     RECT  25.032 40.981 26.16 41.749 ;
     RECT  31.848 40.981 32.976 42.133 ;
     RECT  34.8 41.063 35.232 41.605 ;
     RECT  33 41.605 34.128 42.133 ;
     RECT  34.152 41.605 35.232 43.045 ;
  END
END ot_hbm_su_stree_root
END LIBRARY
